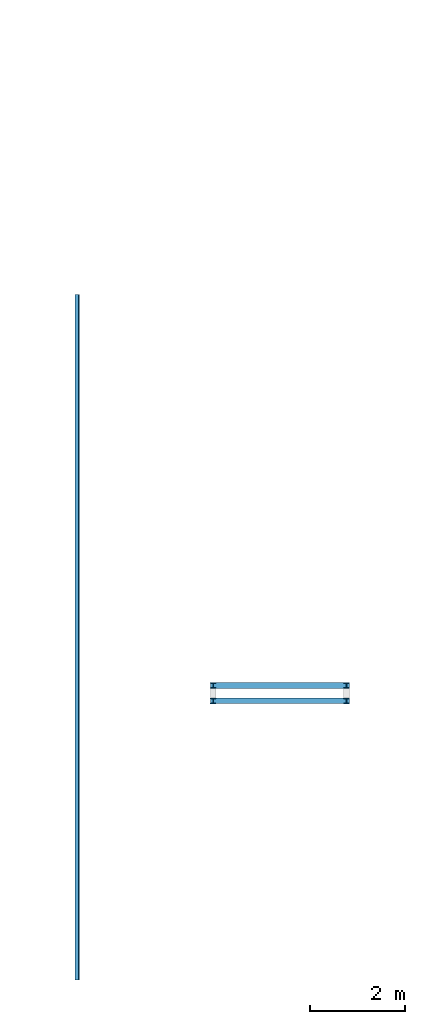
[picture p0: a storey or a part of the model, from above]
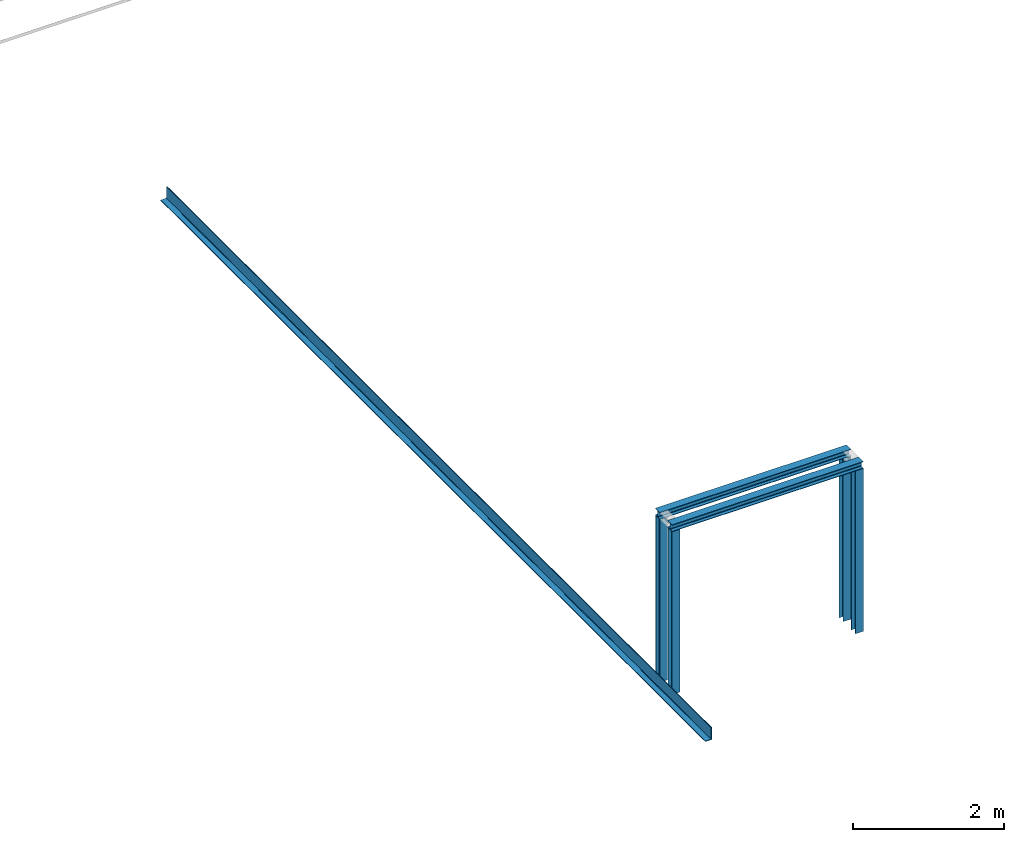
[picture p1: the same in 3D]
Properties of the parts of a building model (IFC4X3_ADD2), part 1 of 4

# File
Description: ViewDefinition [CoordinationView_V2.0], ExchangeRequirement [Architecture], Option [IfcExportBaseQuantities: Off], Option [IfcExportElementOnOffAndFrozenLayers: On], Option [IfcExplodeExternalReferences: Off], Option [IfcTesselateBSplineCurvesAndSurfaces: Off], Option [IfcExportSweptSolidAsBRep: Off], Option [IfcExportProfileCenterOfGravity: Off], Option [IfcExportMultiPlyElementsAsAggregated: Off], Option [IfcExportTesselation: 0.000000], Option [IfcCreateUniqueGuidForBlocks: On], Option [IfcCreateUniqueGuidForXrefs: On], Option [IfcExportSubtractOpenings: Off], Option [IfcExportAllVisibilityStates: Off]
File name: C:\\Users\\info\\Documents\\00 Elearning geodata BIMform\\1.2 Coördinatensystemen en projecties\\1.2.2 Georeferentie in IFC modellen\\IFC files\\BIM_Architecture__stabilite-IFC4_subset.ifc
Time: 2026-02-23T21:27:19
Author: Undefined
Organization: Undefined
Written by: BricsCAD BIM 26.1.08
Made in: BricsCAD BIM 26.1.08
Authorization: Undefined

# IfcSite, Site
RefLatitude: 42, 23, 13, 199999; RefLongitude: -71, -14, -31, -199998; RefElevation: 0 mm

# IfcBuilding, IFC Building Story
ElevationOfRefHeight: 0 mm; ElevationOfTerrain: 0 mm

# IfcBuildingStorey (6)
In: IFC Building Story
Name | LongName | Elevation (mm)
ETAGE -1 | ETAGE -1 | -3000
FOND 00 (0) | FOND 00 (0) | -800
ETAGE 00 (0) | ETAGE 00 (0) | 0
ETAGE 10 (1) | ETAGE 10 (1) | 4370
ETAGE 20 (2) | ETAGE 20 (2) | 8640
ACROTERE (4) | ACROTERE (4) | 10000

# IfcBeam: 1*1 (8)
Description: 1*1; Group: Groupe de modèles:IFC ERGON 14122021 (membre exclu):2154686
Pset_XX_AsBuilt - Catégorie: Ossature; Famille: Forme directe; Type: 1*1; Durée de garantie (mois): 0; Périodicité de contrôle (mois): 0
Pset_XX_Poutres - Résistance au feu: RF60
Name | In | Identifiant
RAV200 | ETAGE 00 (0) | 57 | Material: STEEL/Accessory
2 x ZW1 | ETAGE 00 (0) | 62 | Material: STEEL/Accessory_invisible
RAV200 | ETAGE 00 (0) | 58 | Material: STEEL/Accessory
4 x MP15 | ETAGE 20 (2) | 336

# IfcBeam: 1*1 10 (12)
In: ETAGE 10 (1)
Description: 1*1; Material: STEEL/Accessory_invisible; Group: Groupe de modèles:IFC ERGON 14122021 (membre exclu):2154686
Pset_XX_AsBuilt - Catégorie: Ossature; Famille: Forme directe; Type: 1*1; Identifiant: 193; Durée de garantie (mois): 0; Périodicité de contrôle (mois): 0
Pset_XX_Poutres - Résistance au feu: RF60

# IfcBeam: 1*1 11 (6)
In: ETAGE 10 (1)
Description: 1*1; Material: STEEL/Accessory_invisible; Group: Groupe de modèles:IFC ERGON 14122021 (membre exclu):2154686
Pset_XX_AsBuilt - Catégorie: Ossature; Famille: Forme directe; Type: 1*1; Identifiant: 296; Durée de garantie (mois): 0; Périodicité de contrôle (mois): 0
Pset_XX_Poutres - Résistance au feu: RF60

# IfcBeam: 1*1 12 (29)
Description: 1*1; Material: STEEL/Accessory_invisible; Group: Groupe de modèles:IFC ERGON 14122021 (membre exclu):2154686
Pset_XX_AsBuilt - Catégorie: Ossature; Famille: Forme directe; Type: 1*1; Identifiant: 310; Durée de garantie (mois): 0; Périodicité de contrôle (mois): 0
Pset_XX_Poutres - Résistance au feu: RF60
Name | In
19 x ZW1 | ETAGE 10 (1)
10 x ZW1 | ETAGE 20 (2)

# IfcBeam: 1*1 13 (12)
In: ETAGE 10 (1)
Description: 1*1; Material: STEEL/Accessory_invisible 261; Group: Groupe de modèles:IFC ERGON 14122021 (membre exclu):2154686
Pset_XX_AsBuilt - Catégorie: Ossature; Famille: Forme directe; Type: 1*1; Identifiant: 291; Durée de garantie (mois): 0; Périodicité de contrôle (mois): 0
Pset_XX_Poutres - Résistance au feu: RF60

# IfcBeam: 1*1 14 (12)
In: ETAGE 10 (1)
Description: 1*1; Material: STEEL/Accessory_invisible; Group: Groupe de modèles:IFC ERGON 14122021 (membre exclu):2154686
Pset_XX_AsBuilt - Catégorie: Ossature; Famille: Forme directe; Type: 1*1; Identifiant: 293; Durée de garantie (mois): 0; Périodicité de contrôle (mois): 0
Pset_XX_Poutres - Résistance au feu: RF60

# IfcBeam: 1*1 15 (3)
In: ETAGE 10 (1)
Description: 1*1; Material: STEEL/Accessory_invisible; Group: Groupe de modèles:IFC ERGON 14122021 (membre exclu):2154686
Pset_XX_AsBuilt - Catégorie: Ossature; Famille: Forme directe; Type: 1*1; Identifiant: 314; Durée de garantie (mois): 0; Périodicité de contrôle (mois): 0
Pset_XX_Poutres - Résistance au feu: RF60

# IfcBeam: 1*1 16 (4)
In: ETAGE 20 (2)
Description: 1*1; Material: STEEL/Accessory_invisible; Group: Groupe de modèles:IFC ERGON 14122021 (membre exclu):2154686
Pset_XX_AsBuilt - Catégorie: Ossature; Famille: Forme directe; Type: 1*1; Identifiant: 180; Durée de garantie (mois): 0; Périodicité de contrôle (mois): 0
Pset_XX_Poutres - Résistance au feu: RF60

# IfcBeam: 1*1 17 (6)
In: ETAGE 20 (2)
Description: 1*1; Material: STEEL/Accessory_invisible; Group: Groupe de modèles:IFC ERGON 14122021 (membre exclu):2154686
Pset_XX_AsBuilt - Catégorie: Ossature; Famille: Forme directe; Type: 1*1; Identifiant: 188; Durée de garantie (mois): 0; Périodicité de contrôle (mois): 0
Pset_XX_Poutres - Résistance au feu: RF60

# IfcBeam: 1*1 18 (12)
In: ETAGE 20 (2)
Description: 1*1; Material: STEEL/Accessory_invisible 261; Group: Groupe de modèles:IFC ERGON 14122021 (membre exclu):2154686
Pset_XX_AsBuilt - Catégorie: Ossature; Famille: Forme directe; Type: 1*1; Durée de garantie (mois): 0; Périodicité de contrôle (mois): 0
Pset_XX_Poutres - Résistance au feu: RF60
Name | Identifiant
6 x 50 | L1
6 x ZN342 | L2

# IfcBeam: 1*1 19 (6)
In: ETAGE 20 (2)
Description: 1*1; Material: STEEL/Accessory_invisible 261; Group: Groupe de modèles:IFC ERGON 14122021 (membre exclu):2154686
Pset_XX_AsBuilt - Catégorie: Ossature; Famille: Forme directe; Type: 1*1; Identifiant: L3; Durée de garantie (mois): 0; Périodicité de contrôle (mois): 0
Pset_XX_Poutres - Résistance au feu: RF60

# IfcBeam: 1*1 2 (66)
In: ETAGE 00 (0)
Description: 1*1; Material: STEEL/Accessory_invisible 261; Group: Groupe de modèles:IFC ERGON 14122021 (membre exclu):2154686
Pset_XX_AsBuilt - Catégorie: Ossature; Famille: Forme directe; Type: 1*1; Identifiant: 47; Durée de garantie (mois): 0; Périodicité de contrôle (mois): 0
Pset_XX_Poutres - Résistance au feu: RF60

# IfcBeam: 1*1 20 (12)
In: ETAGE 20 (2)
Description: 1*1; Material: STEEL/Accessory_invisible; Group: Groupe de modèles:IFC ERGON 14122021 (membre exclu):2154686
Pset_XX_AsBuilt - Catégorie: Ossature; Famille: Forme directe; Type: 1*1; Durée de garantie (mois): 0; Périodicité de contrôle (mois): 0
Pset_XX_Poutres - Résistance au feu: RF60
Name | Identifiant
6 x MP14 | 331
6 x MP14 | 332

# IfcBeam: 1*1 21 (4)
In: ETAGE 20 (2)
Description: 1*1; Material: STEEL/Accessory_invisible; Group: Groupe de modèles:IFC ERGON 14122021 (membre exclu):2154686
Pset_XX_AsBuilt - Catégorie: Ossature; Famille: Forme directe; Type: 1*1; Identifiant: 337; Durée de garantie (mois): 0; Périodicité de contrôle (mois): 0
Pset_XX_Poutres - Résistance au feu: RF60

# IfcBeam: 1*1 22, ZW1
In: ETAGE 20 (2)
Description: 1*1; Material: STEEL/Accessory_invisible; Group: Groupe de modèles:IFC ERGON 14122021 (membre exclu):2154686
Pset_XX_AsBuilt - Catégorie: Ossature; Famille: Forme directe; Type: 1*1; Identifiant: 333; Durée de garantie (mois): 0; Périodicité de contrôle (mois): 0
Pset_XX_Poutres - Résistance au feu: RF60

# IfcBeam: 1*1 3 (239)
Description: 1*1; Group: Groupe de modèles:IFC ERGON 14122021 (membre exclu):2154686
Pset_XX_AsBuilt - Catégorie: Ossature; Famille: Forme directe; Type: 1*1; Durée de garantie (mois): 0; Périodicité de contrôle (mois): 0
Pset_XX_Poutres - Résistance au feu: RF60
Name | In | Material | Identifiant
46 x ES31 | ETAGE 00 (0) | STEEL/Accessory_invisible 261 | 48
9 x ES31 | ETAGE 00 (0) | STEEL/Accessory_invisible 261 | 100
2 x ES31 | ETAGE 00 (0) | STEEL/Accessory_invisible 261 | 101
ES31 | ETAGE 00 (0) | STEEL/Accessory_invisible 261 | 103
2 x ES31 | ETAGE 00 (0) | STEEL/Accessory_invisible 261 | 104
ES31 | ETAGE 00 (0) | STEEL/Accessory_invisible 261 | 105
ES31 | ETAGE 00 (0) | STEEL/Accessory_invisible 261 | 106
2 x ES31 | ETAGE 00 (0) | STEEL/Accessory_invisible 261 | 260
4 x ES31 | ETAGE 00 (0) | STEEL/Accessory_invisible 261 | 262
8 x ZW3 | ETAGE 00 (0) | STEEL/Accessory_invisible | 282
4 x ZW3 | ETAGE 00 (0) | STEEL/Accessory_invisible | 283
9 x ZW3 | ETAGE 00 (0) | STEEL/Accessory_invisible | 284
10 x ZW3 | ETAGE 00 (0) | STEEL/Accessory_invisible | 285
6 x ZW3 | ETAGE 00 (0) | STEEL/Accessory_invisible | 280
ZW3 | ETAGE 00 (0) | STEEL/Accessory_invisible | 286
3 x 51 | ETAGE 00 (0) | STEEL/Accessory_invisible 261 | 303
ZW3 | ETAGE 00 (0) | STEEL/Accessory_invisible | 278
2 x ZW3 | ETAGE 00 (0) | STEEL/Accessory_invisible | 275
16 x RH14 | ETAGE 10 (1) | STEEL/Accessory_invisible | 264
16 x MP21 | ETAGE 10 (1) | STEEL/Accessory_invisible | 267
2 x RH15 | ETAGE 10 (1) | STEEL/Accessory_invisible | 188
6 x ZW3 | ETAGE 10 (1) | STEEL/Accessory_invisible | 296
MP12 | ETAGE 10 (1) | STEEL/Accessory_invisible | 182
4 x RH15 | ETAGE 10 (1) | STEEL/Accessory_invisible | 199
4 x RH14 | ETAGE 20 (2) | STEEL/Accessory_invisible | 264
16 x MP21 | ETAGE 20 (2) | STEEL/Accessory_invisible | 267
4 x ZW3 | ETAGE 20 (2) | STEEL/Accessory_invisible | 296
12 x ZW1 | ETAGE 20 (2) | STEEL/Accessory_invisible | 333
4 x ZW3 | ETAGE 20 (2) | STEEL/Accessory_invisible | 280
3 x 52 | ETAGE 10 (1) | STEEL/Accessory_invisible 261 | 307
11 x 54 | ETAGE 10 (1) | STEEL/Accessory_invisible 261 | 321
8 x 54 | ETAGE 10 (1) | STEEL/Accessory_invisible 261 | 319
10 x 54 | ETAGE 20 (2) | STEEL/Accessory_invisible 261 | 319
3 x 53 | ETAGE 10 (1) | STEEL/Accessory_invisible 261 | 311
MP12 | ETAGE 10 (1) | STEEL/Accessory_invisible | 183
5 x ZW3 | ETAGE 10 (1) | STEEL/Accessory_invisible | 280
55 | ETAGE 20 (2) | STEEL/Accessory_invisible | 338

# IfcBeam: 1*1 4 (3)
In: ETAGE 00 (0)
Description: 1*1; Material: STEEL/Accessory_invisible; Group: Groupe de modèles:IFC ERGON 14122021 (membre exclu):2154686
Pset_XX_AsBuilt - Catégorie: Ossature; Famille: Forme directe; Type: 1*1; Identifiant: 306; Durée de garantie (mois): 0; Périodicité de contrôle (mois): 0
Pset_XX_Poutres - Résistance au feu: RF60

# IfcBeam: 1*1 5 (6)
In: ETAGE 00 (0)
Description: 1*1; Material: STEEL/Accessory_invisible; Group: Groupe de modèles:IFC ERGON 14122021 (membre exclu):2154686
Pset_XX_AsBuilt - Catégorie: Ossature; Famille: Forme directe; Type: 1*1; Identifiant: 343; Durée de garantie (mois): 0; Périodicité de contrôle (mois): 0
Pset_XX_Poutres - Résistance au feu: RF60

# IfcBeam: 1*1 6 (20)
Description: 1*1; Material: STEEL/Accessory_invisible; Group: Groupe de modèles:IFC ERGON 14122021 (membre exclu):2154686
Pset_XX_AsBuilt - Catégorie: Ossature; Famille: Forme directe; Type: 1*1; Identifiant: 264; Durée de garantie (mois): 0; Périodicité de contrôle (mois): 0
Pset_XX_Poutres - Résistance au feu: RF60
Name | In
10 x RH14 | ETAGE 10 (1)
10 x RH14 | ETAGE 20 (2)

# IfcBeam: 1*1 7 (2)
In: ETAGE 10 (1)
Description: 1*1; Material: STEEL/Accessory_invisible; Group: Groupe de modèles:IFC ERGON 14122021 (membre exclu):2154686
Pset_XX_AsBuilt - Catégorie: Ossature; Famille: Forme directe; Type: 1*1; Durée de garantie (mois): 0; Périodicité de contrôle (mois): 0
Pset_XX_Poutres - Résistance au feu: RF60
Name | Identifiant
MP12 | 182
MP12 | 183

# IfcBeam: 1*1 8 (4)
In: ETAGE 10 (1)
Description: 1*1; Material: STEEL/Accessory_invisible; Group: Groupe de modèles:IFC ERGON 14122021 (membre exclu):2154686
Pset_XX_AsBuilt - Catégorie: Ossature; Famille: Forme directe; Type: 1*1; Identifiant: 185; Durée de garantie (mois): 0; Périodicité de contrôle (mois): 0
Pset_XX_Poutres - Résistance au feu: RF60

# IfcBeam: 1*1 9 (35)
Description: 1*1; Material: STEEL/Accessory_invisible; Group: Groupe de modèles:IFC ERGON 14122021 (membre exclu):2154686
Pset_XX_AsBuilt - Catégorie: Ossature; Famille: Forme directe; Type: 1*1; Durée de garantie (mois): 0; Périodicité de contrôle (mois): 0
Pset_XX_Poutres - Résistance au feu: RF60
Name | In | Identifiant
28 x MP21 | ETAGE 10 (1) | 267
3 x ZW1 | ETAGE 10 (1) | 310
4 x MP21 | ETAGE 20 (2) | 267

# IfcBeam: 10*1 (5)
In: ETAGE 10 (1)
Description: 10*1; Material: STEEL/Accessory_invisible 261; Group: Groupe de modèles:IFC ERGON 14122021 (membre exclu):2154686
Pset_XX_AsBuilt - Catégorie: Ossature; Famille: Forme directe; Type: 10*1; Durée de garantie (mois): 0; Périodicité de contrôle (mois): 0
Pset_XX_Poutres - Résistance au feu: RF60
Name | Identifiant
2 x BEK4 | 134
3 x BEK4 | 151

# IfcBeam: 100*100 (221)
In: ETAGE 00 (0)
Description: 100*100; Material: STEEL/Accessory_invisible; Group: Groupe de modèles:IFC ERGON 14122021 (membre exclu):2154686
Pset_XX_AsBuilt - Catégorie: Ossature; Famille: Forme directe; Type: 100*100; Identifiant: 46; Durée de garantie (mois): 0; Périodicité de contrôle (mois): 0
Pset_XX_Poutres - Résistance au feu: RF60

# IfcBeam: 100*80 (6)
In: ETAGE 00 (0)
Description: 100*80; Material: STEEL/Accessory_invisible; Group: Groupe de modèles:IFC ERGON 14122021 (membre exclu):2154686
Pset_XX_AsBuilt - Catégorie: Ossature; Famille: Forme directe; Type: 100*80; Identifiant: 102; Durée de garantie (mois): 0; Périodicité de contrôle (mois): 0
Pset_XX_Poutres - Résistance au feu: RF60

# IfcBeam: 11*1 (2)
In: ETAGE 10 (1)
Description: 11*1; Material: STEEL/Accessory_invisible 261; Group: Groupe de modèles:IFC ERGON 14122021 (membre exclu):2154686
Pset_XX_AsBuilt - Catégorie: Ossature; Famille: Forme directe; Type: 11*1; Durée de garantie (mois): 0; Périodicité de contrôle (mois): 0
Pset_XX_Poutres - Résistance au feu: RF60
Name | Identifiant
BEK4 | 126
BEK4 | 146

# IfcBeam: 11*1 2, BEK4
In: ETAGE 10 (1)
Description: 11*1; Material: STEEL/Accessory_invisible 261; Group: Groupe de modèles:IFC ERGON 14122021 (membre exclu):2154686
Pset_XX_AsBuilt - Catégorie: Ossature; Famille: Forme directe; Type: 11*1; Identifiant: 242; Durée de garantie (mois): 0; Périodicité de contrôle (mois): 0
Pset_XX_Poutres - Résistance au feu: RF60

# IfcBeam: 11*1 3, BEK4
In: ETAGE 10 (1)
Description: 11*1; Material: STEEL/Accessory_invisible 261; Group: Groupe de modèles:IFC ERGON 14122021 (membre exclu):2154686
Pset_XX_AsBuilt - Catégorie: Ossature; Famille: Forme directe; Type: 11*1; Identifiant: 117; Durée de garantie (mois): 0; Périodicité de contrôle (mois): 0
Pset_XX_Poutres - Résistance au feu: RF60

# IfcBeam: 11*1 4, BEK4
In: ETAGE 10 (1)
Description: 11*1; Material: STEEL/Accessory_invisible 261; Group: Groupe de modèles:IFC ERGON 14122021 (membre exclu):2154686
Pset_XX_AsBuilt - Catégorie: Ossature; Famille: Forme directe; Type: 11*1; Identifiant: 146; Durée de garantie (mois): 0; Périodicité de contrôle (mois): 0
Pset_XX_Poutres - Résistance au feu: RF60

# IfcBeam: 11*1 5, BEK4
In: ETAGE 20 (2)
Description: 11*1; Material: STEEL/Accessory_invisible 261; Group: Groupe de modèles:IFC ERGON 14122021 (membre exclu):2154686
Pset_XX_AsBuilt - Catégorie: Ossature; Famille: Forme directe; Type: 11*1; Identifiant: 117; Durée de garantie (mois): 0; Périodicité de contrôle (mois): 0
Pset_XX_Poutres - Résistance au feu: RF60

# IfcBeam: 11*1 6, BEK4
In: ETAGE 20 (2)
Description: 11*1; Material: STEEL/Accessory_invisible 261; Group: Groupe de modèles:IFC ERGON 14122021 (membre exclu):2154686
Pset_XX_AsBuilt - Catégorie: Ossature; Famille: Forme directe; Type: 11*1; Identifiant: 111; Durée de garantie (mois): 0; Périodicité de contrôle (mois): 0
Pset_XX_Poutres - Résistance au feu: RF60

# IfcBeam: 11*1 7, BEK4
In: ETAGE 20 (2)
Description: 11*1; Material: STEEL/Accessory_invisible 261; Group: Groupe de modèles:IFC ERGON 14122021 (membre exclu):2154686
Pset_XX_AsBuilt - Catégorie: Ossature; Famille: Forme directe; Type: 11*1; Identifiant: 111; Durée de garantie (mois): 0; Périodicité de contrôle (mois): 0
Pset_XX_Poutres - Résistance au feu: RF60

# IfcBeam: 11*1 8, BEK4
In: ETAGE 20 (2)
Description: 11*1; Material: STEEL/Accessory_invisible 261; Group: Groupe de modèles:IFC ERGON 14122021 (membre exclu):2154686
Pset_XX_AsBuilt - Catégorie: Ossature; Famille: Forme directe; Type: 11*1; Identifiant: 126; Durée de garantie (mois): 0; Périodicité de contrôle (mois): 0
Pset_XX_Poutres - Résistance au feu: RF60

# IfcBeam: 11*1 9, BEK4
In: ETAGE 20 (2)
Description: 11*1; Material: STEEL/Accessory_invisible 261; Group: Groupe de modèles:IFC ERGON 14122021 (membre exclu):2154686
Pset_XX_AsBuilt - Catégorie: Ossature; Famille: Forme directe; Type: 11*1; Identifiant: 126; Durée de garantie (mois): 0; Périodicité de contrôle (mois): 0
Pset_XX_Poutres - Résistance au feu: RF60

# IfcBeam: 12*1 (3)
In: ETAGE 10 (1)
Description: 12*1; Material: STEEL/Accessory_invisible 261; Group: Groupe de modèles:IFC ERGON 14122021 (membre exclu):2154686
Pset_XX_AsBuilt - Catégorie: Ossature; Famille: Forme directe; Type: 12*1; Identifiant: 248; Durée de garantie (mois): 0; Périodicité de contrôle (mois): 0
Pset_XX_Poutres - Résistance au feu: RF60

# IfcBeam: 200*170 (2)
In: ETAGE 00 (0)
Description: 200*170; Material: STEEL/Accessory_invisible; Group: Groupe de modèles:IFC ERGON 14122021 (membre exclu):2154686
Pset_XX_AsBuilt - Catégorie: Ossature; Famille: Forme directe; Type: 200*170; Durée de garantie (mois): 0; Périodicité de contrôle (mois): 0
Pset_XX_Poutres - Résistance au feu: RF60
Name | Identifiant
ES32 | 76
ES32 | 157

# IfcBeam: 200*190 (2)
In: ETAGE 00 (0)
Description: 200*190; Material: STEEL/Accessory_invisible; Group: Groupe de modèles:IFC ERGON 14122021 (membre exclu):2154686
Pset_XX_AsBuilt - Catégorie: Ossature; Famille: Forme directe; Type: 200*190; Identifiant: 263; Durée de garantie (mois): 0; Périodicité de contrôle (mois): 0
Pset_XX_Poutres - Résistance au feu: RF60

# IfcBeam: 200*210 (2)
In: ETAGE 00 (0)
Description: 200*210; Material: STEEL/Accessory_invisible; Group: Groupe de modèles:IFC ERGON 14122021 (membre exclu):2154686
Pset_XX_AsBuilt - Catégorie: Ossature; Famille: Forme directe; Type: 200*210; Identifiant: 43; Durée de garantie (mois): 0; Périodicité de contrôle (mois): 0
Pset_XX_Poutres - Résistance au feu: RF60

# IfcBeam: 200*260, ES32
In: ETAGE 00 (0)
Description: 200*260; Material: STEEL/Accessory_invisible; Group: Groupe de modèles:IFC ERGON 14122021 (membre exclu):2154686
Pset_XX_AsBuilt - Catégorie: Ossature; Famille: Forme directe; Type: 200*260; Identifiant: 75; Durée de garantie (mois): 0; Périodicité de contrôle (mois): 0
Pset_XX_Poutres - Résistance au feu: RF60

# IfcBeam: 200*350, ES32
In: ETAGE 00 (0)
Description: 200*350; Material: STEEL/Accessory_invisible; Group: Groupe de modèles:IFC ERGON 14122021 (membre exclu):2154686
Pset_XX_AsBuilt - Catégorie: Ossature; Famille: Forme directe; Type: 200*350; Identifiant: 70; Durée de garantie (mois): 0; Périodicité de contrôle (mois): 0
Pset_XX_Poutres - Résistance au feu: RF60

# IfcBeam: 200*360, ES32
In: ETAGE 00 (0)
Description: 200*360; Material: STEEL/Accessory_invisible; Group: Groupe de modèles:IFC ERGON 14122021 (membre exclu):2154686
Pset_XX_AsBuilt - Catégorie: Ossature; Famille: Forme directe; Type: 200*360; Identifiant: 261; Durée de garantie (mois): 0; Périodicité de contrôle (mois): 0
Pset_XX_Poutres - Résistance au feu: RF60

# IfcBeam: 200*380, ES32
In: ETAGE 00 (0)
Description: 200*380; Material: STEEL/Accessory_invisible; Group: Groupe de modèles:IFC ERGON 14122021 (membre exclu):2154686
Pset_XX_AsBuilt - Catégorie: Ossature; Famille: Forme directe; Type: 200*380; Identifiant: 54; Durée de garantie (mois): 0; Périodicité de contrôle (mois): 0
Pset_XX_Poutres - Résistance au feu: RF60

# IfcBeam: 200*410 (2)
In: ETAGE 00 (0)
Description: 200*410; Material: STEEL/Accessory_invisible; Group: Groupe de modèles:IFC ERGON 14122021 (membre exclu):2154686
Pset_XX_AsBuilt - Catégorie: Ossature; Famille: Forme directe; Type: 200*410; Identifiant: 72; Durée de garantie (mois): 0; Périodicité de contrôle (mois): 0
Pset_XX_Poutres - Résistance au feu: RF60

# IfcBeam: 200*430 (4)
In: ETAGE 00 (0)
Description: 200*430; Material: STEEL/Accessory_invisible; Group: Groupe de modèles:IFC ERGON 14122021 (membre exclu):2154686
Pset_XX_AsBuilt - Catégorie: Ossature; Famille: Forme directe; Type: 200*430; Identifiant: 158; Durée de garantie (mois): 0; Périodicité de contrôle (mois): 0
Pset_XX_Poutres - Résistance au feu: RF60

# IfcBeam: 200*460, ES32
In: ETAGE 00 (0)
Description: 200*460; Material: STEEL/Accessory_invisible; Group: Groupe de modèles:IFC ERGON 14122021 (membre exclu):2154686
Pset_XX_AsBuilt - Catégorie: Ossature; Famille: Forme directe; Type: 200*460; Identifiant: 78; Durée de garantie (mois): 0; Périodicité de contrôle (mois): 0
Pset_XX_Poutres - Résistance au feu: RF60

# IfcBeam: 200*490, ES32
In: ETAGE 00 (0)
Description: 200*490; Material: STEEL/Accessory_invisible; Group: Groupe de modèles:IFC ERGON 14122021 (membre exclu):2154686
Pset_XX_AsBuilt - Catégorie: Ossature; Famille: Forme directe; Type: 200*490; Identifiant: 96; Durée de garantie (mois): 0; Périodicité de contrôle (mois): 0
Pset_XX_Poutres - Résistance au feu: RF60

# IfcBeam: 200*50 (2)
In: ETAGE 00 (0)
Description: 200*50; Material: STEEL/Accessory_invisible; Group: Groupe de modèles:IFC ERGON 14122021 (membre exclu):2154686
Pset_XX_AsBuilt - Catégorie: Ossature; Famille: Forme directe; Type: 200*50; Durée de garantie (mois): 0; Périodicité de contrôle (mois): 0
Pset_XX_Poutres - Résistance au feu: RF60
Name | Identifiant
ES32 | 55
ES32 | 56

# IfcBeam: 200*560 (2)
In: ETAGE 00 (0)
Description: 200*560; Material: STEEL/Accessory_invisible; Group: Groupe de modèles:IFC ERGON 14122021 (membre exclu):2154686
Pset_XX_AsBuilt - Catégorie: Ossature; Famille: Forme directe; Type: 200*560; Identifiant: 69; Durée de garantie (mois): 0; Périodicité de contrôle (mois): 0
Pset_XX_Poutres - Résistance au feu: RF60

# IfcBeam: 200*90, ES32
In: ETAGE 00 (0)
Description: 200*90; Material: STEEL/Accessory_invisible; Group: Groupe de modèles:IFC ERGON 14122021 (membre exclu):2154686
Pset_XX_AsBuilt - Catégorie: Ossature; Famille: Forme directe; Type: 200*90; Identifiant: 71; Durée de garantie (mois): 0; Périodicité de contrôle (mois): 0
Pset_XX_Poutres - Résistance au feu: RF60

# IfcBeam: 203*1, BEK4
In: ETAGE 10 (1)
Description: 203*1; Material: STEEL/Accessory_invisible 261; Group: Groupe de modèles:IFC ERGON 14122021 (membre exclu):2154686
Pset_XX_AsBuilt - Catégorie: Ossature; Famille: Forme directe; Type: 203*1; Identifiant: 255; Durée de garantie (mois): 0; Périodicité de contrôle (mois): 0
Pset_XX_Poutres - Résistance au feu: RF60

# IfcBeam: 210*1 (4)
In: ETAGE 10 (1)
Description: 210*1; Material: STEEL/Accessory_invisible 261; Group: Groupe de modèles:IFC ERGON 14122021 (membre exclu):2154686
Pset_XX_AsBuilt - Catégorie: Ossature; Famille: Forme directe; Type: 210*1; Durée de garantie (mois): 0; Périodicité de contrôle (mois): 0
Pset_XX_Poutres - Résistance au feu: RF60
Name | Identifiant
3 x BEK4 | 137
BEK4 | 145

# IfcBeam: 210*1 2 (2)
In: ETAGE 10 (1)
Description: 210*1; Material: STEEL/Accessory_invisible 261; Group: Groupe de modèles:IFC ERGON 14122021 (membre exclu):2154686
Pset_XX_AsBuilt - Catégorie: Ossature; Famille: Forme directe; Type: 210*1; Durée de garantie (mois): 0; Périodicité de contrôle (mois): 0
Pset_XX_Poutres - Résistance au feu: RF60
Name | Identifiant
BEK4 | 145
BEK4 | 137

# IfcBeam: 210*1 3, BEK4
In: ETAGE 10 (1)
Description: 210*1; Material: STEEL/Accessory_invisible 261; Group: Groupe de modèles:IFC ERGON 14122021 (membre exclu):2154686
Pset_XX_AsBuilt - Catégorie: Ossature; Famille: Forme directe; Type: 210*1; Identifiant: 145; Durée de garantie (mois): 0; Périodicité de contrôle (mois): 0
Pset_XX_Poutres - Résistance au feu: RF60

# IfcBeam: 211*1, BEK4
In: ETAGE 10 (1)
Description: 211*1; Material: STEEL/Accessory_invisible 261; Group: Groupe de modèles:IFC ERGON 14122021 (membre exclu):2154686
Pset_XX_AsBuilt - Catégorie: Ossature; Famille: Forme directe; Type: 211*1; Identifiant: 250; Durée de garantie (mois): 0; Périodicité de contrôle (mois): 0
Pset_XX_Poutres - Résistance au feu: RF60

# IfcBeam: 218*1, BEK4
In: ETAGE 10 (1)
Description: 218*1; Material: STEEL/Accessory_invisible 261; Group: Groupe de modèles:IFC ERGON 14122021 (membre exclu):2154686
Pset_XX_AsBuilt - Catégorie: Ossature; Famille: Forme directe; Type: 218*1; Identifiant: 252; Durée de garantie (mois): 0; Périodicité de contrôle (mois): 0
Pset_XX_Poutres - Résistance au feu: RF60

# IfcBeam: 30*200, POL4
In: ETAGE 10 (1)
Description: 30*200; Material: STEEL/Accessory_EPS; Group: Groupe de modèles:IFC ERGON 14122021 (membre exclu):2154686
Pset_XX_AsBuilt - Catégorie: Ossature; Famille: Forme directe; Type: 30*200; Identifiant: 231; Durée de garantie (mois): 0; Périodicité de contrôle (mois): 0
Pset_XX_Poutres - Résistance au feu: RF60

# IfcBeam: 30*300 (19)
Description: 30*300; Material: STEEL/Accessory_EPS; Group: Groupe de modèles:IFC ERGON 14122021 (membre exclu):2154686
Pset_XX_AsBuilt - Catégorie: Ossature; Famille: Forme directe; Type: 30*300; Identifiant: 13; Durée de garantie (mois): 0; Périodicité de contrôle (mois): 0
Pset_XX_Poutres - Résistance au feu: RF60
Name | In
17 x POL4 | ETAGE 00 (0)
2 x POL4 | ETAGE 10 (1)

# IfcBeam: 30*300 2 (5)
In: ETAGE 00 (0)
Description: 30*300; Material: STEEL/Accessory_EPS; Group: Groupe de modèles:IFC ERGON 14122021 (membre exclu):2154686
Pset_XX_AsBuilt - Catégorie: Ossature; Famille: Forme directe; Type: 30*300; Identifiant: 226; Durée de garantie (mois): 0; Périodicité de contrôle (mois): 0
Pset_XX_Poutres - Résistance au feu: RF60

# IfcBeam: 30*300 3 (3)
In: ETAGE 00 (0)
Description: 30*300; Material: STEEL/Accessory_EPS; Group: Groupe de modèles:IFC ERGON 14122021 (membre exclu):2154686
Pset_XX_AsBuilt - Catégorie: Ossature; Famille: Forme directe; Type: 30*300; Identifiant: 81; Durée de garantie (mois): 0; Périodicité de contrôle (mois): 0
Pset_XX_Poutres - Résistance au feu: RF60

# IfcBeam: 30*300 4 (10)
In: ETAGE 10 (1)
Description: 30*300; Material: STEEL/Accessory_EPS; Group: Groupe de modèles:IFC ERGON 14122021 (membre exclu):2154686
Pset_XX_AsBuilt - Catégorie: Ossature; Famille: Forme directe; Type: 30*300; Identifiant: 81; Durée de garantie (mois): 0; Périodicité de contrôle (mois): 0
Pset_XX_Poutres - Résistance au feu: RF60

# IfcBeam: 30*340, POL4
In: ETAGE 00 (0)
Description: 30*340; Material: STEEL/Accessory_EPS; Group: Groupe de modèles:IFC ERGON 14122021 (membre exclu):2154686
Pset_XX_AsBuilt - Catégorie: Ossature; Famille: Forme directe; Type: 30*340; Identifiant: 9; Durée de garantie (mois): 0; Périodicité de contrôle (mois): 0
Pset_XX_Poutres - Résistance au feu: RF60

# IfcBeam: 4*1 (5)
In: ETAGE 20 (2)
Description: 4*1; Material: STEEL/Accessory_invisible 261; Group: Groupe de modèles:IFC ERGON 14122021 (membre exclu):2154686
Pset_XX_AsBuilt - Catégorie: Ossature; Famille: Forme directe; Type: 4*1; Durée de garantie (mois): 0; Périodicité de contrôle (mois): 0
Pset_XX_Poutres - Résistance au feu: RF60
Name | Identifiant
4 x BEK4 | 112
BEK4 | 208

# IfcBeam: 4*1 2 (3)
In: ETAGE 20 (2)
Description: 4*1; Material: STEEL/Accessory_invisible 261; Group: Groupe de modèles:IFC ERGON 14122021 (membre exclu):2154686
Pset_XX_AsBuilt - Catégorie: Ossature; Famille: Forme directe; Type: 4*1; Identifiant: 115; Durée de garantie (mois): 0; Périodicité de contrôle (mois): 0
Pset_XX_Poutres - Résistance au feu: RF60

# IfcBeam: 4*1 3 (2)
In: ETAGE 20 (2)
Description: 4*1; Material: STEEL/Accessory_invisible 261; Group: Groupe de modèles:IFC ERGON 14122021 (membre exclu):2154686
Pset_XX_AsBuilt - Catégorie: Ossature; Famille: Forme directe; Type: 4*1; Durée de garantie (mois): 0; Périodicité de contrôle (mois): 0
Pset_XX_Poutres - Résistance au feu: RF60
Name | Identifiant
BEK4 | 161
BEK4 | 209

# IfcBeam: 4*30 (2)
In: ETAGE 00 (0)
Description: 4*30; Material: STEEL/Accessory_Rubber; Group: Groupe de modèles:IFC ERGON 14122021 (membre exclu):2154686
Pset_XX_AsBuilt - Catégorie: Ossature; Famille: Forme directe; Type: 4*30; Identifiant: 36; Durée de garantie (mois): 0; Périodicité de contrôle (mois): 0
Pset_XX_Poutres - Résistance au feu: RF60

# IfcBeam: 4*30 10, NE6
In: ETAGE 00 (0)
Description: 4*30; Material: STEEL/Accessory_Rubber; Group: Groupe de modèles:IFC ERGON 14122021 (membre exclu):2154686
Pset_XX_AsBuilt - Catégorie: Ossature; Famille: Forme directe; Type: 4*30; Identifiant: 31; Durée de garantie (mois): 0; Périodicité de contrôle (mois): 0
Pset_XX_Poutres - Résistance au feu: RF60

# IfcBeam: 4*30 11, NE6
In: ETAGE 00 (0)
Description: 4*30; Material: STEEL/Accessory_Rubber; Group: Groupe de modèles:IFC ERGON 14122021 (membre exclu):2154686
Pset_XX_AsBuilt - Catégorie: Ossature; Famille: Forme directe; Type: 4*30; Identifiant: 30; Durée de garantie (mois): 0; Périodicité de contrôle (mois): 0
Pset_XX_Poutres - Résistance au feu: RF60

# IfcBeam: 4*30 12, NE6
In: ETAGE 00 (0)
Description: 4*30; Material: STEEL/Accessory_Rubber; Group: Groupe de modèles:IFC ERGON 14122021 (membre exclu):2154686
Pset_XX_AsBuilt - Catégorie: Ossature; Famille: Forme directe; Type: 4*30; Identifiant: 29; Durée de garantie (mois): 0; Périodicité de contrôle (mois): 0
Pset_XX_Poutres - Résistance au feu: RF60

# IfcBeam: 4*30 13, NE6
In: ETAGE 00 (0)
Description: 4*30; Material: STEEL/Accessory_Rubber; Group: Groupe de modèles:IFC ERGON 14122021 (membre exclu):2154686
Pset_XX_AsBuilt - Catégorie: Ossature; Famille: Forme directe; Type: 4*30; Identifiant: 53; Durée de garantie (mois): 0; Périodicité de contrôle (mois): 0
Pset_XX_Poutres - Résistance au feu: RF60

# IfcBeam: 4*30 14 (4)
In: ETAGE 00 (0)
Description: 4*30; Material: STEEL/Accessory_Rubber; Group: Groupe de modèles:IFC ERGON 14122021 (membre exclu):2154686
Pset_XX_AsBuilt - Catégorie: Ossature; Famille: Forme directe; Type: 4*30; Identifiant: 25; Durée de garantie (mois): 0; Périodicité de contrôle (mois): 0
Pset_XX_Poutres - Résistance au feu: RF60

# IfcBeam: 4*30 15 (4)
In: ETAGE 00 (0)
Description: 4*30; Material: STEEL/Accessory_Rubber; Group: Groupe de modèles:IFC ERGON 14122021 (membre exclu):2154686
Pset_XX_AsBuilt - Catégorie: Ossature; Famille: Forme directe; Type: 4*30; Identifiant: 20; Durée de garantie (mois): 0; Périodicité de contrôle (mois): 0
Pset_XX_Poutres - Résistance au feu: RF60

# IfcBeam: 4*30 2 (2)
In: ETAGE 00 (0)
Description: 4*30; Material: STEEL/Accessory_Rubber; Group: Groupe de modèles:IFC ERGON 14122021 (membre exclu):2154686
Pset_XX_AsBuilt - Catégorie: Ossature; Famille: Forme directe; Type: 4*30; Identifiant: 37; Durée de garantie (mois): 0; Périodicité de contrôle (mois): 0
Pset_XX_Poutres - Résistance au feu: RF60

# IfcBeam: 4*30 3 (2)
In: ETAGE 00 (0)
Description: 4*30; Material: STEEL/Accessory_Rubber; Group: Groupe de modèles:IFC ERGON 14122021 (membre exclu):2154686
Pset_XX_AsBuilt - Catégorie: Ossature; Famille: Forme directe; Type: 4*30; Identifiant: 38; Durée de garantie (mois): 0; Périodicité de contrôle (mois): 0
Pset_XX_Poutres - Résistance au feu: RF60

# IfcBeam: 4*30 4 (2)
In: ETAGE 00 (0)
Description: 4*30; Material: STEEL/Accessory_Rubber; Group: Groupe de modèles:IFC ERGON 14122021 (membre exclu):2154686
Pset_XX_AsBuilt - Catégorie: Ossature; Famille: Forme directe; Type: 4*30; Identifiant: 39; Durée de garantie (mois): 0; Périodicité de contrôle (mois): 0
Pset_XX_Poutres - Résistance au feu: RF60

# IfcBeam: 4*30 5, NE6
In: ETAGE 00 (0)
Description: 4*30; Material: STEEL/Accessory_Rubber; Group: Groupe de modèles:IFC ERGON 14122021 (membre exclu):2154686
Pset_XX_AsBuilt - Catégorie: Ossature; Famille: Forme directe; Type: 4*30; Identifiant: 41; Durée de garantie (mois): 0; Périodicité de contrôle (mois): 0
Pset_XX_Poutres - Résistance au feu: RF60

# IfcBeam: 4*30 6, NE6
In: ETAGE 00 (0)
Description: 4*30; Material: STEEL/Accessory_Rubber; Group: Groupe de modèles:IFC ERGON 14122021 (membre exclu):2154686
Pset_XX_AsBuilt - Catégorie: Ossature; Famille: Forme directe; Type: 4*30; Identifiant: 42; Durée de garantie (mois): 0; Périodicité de contrôle (mois): 0
Pset_XX_Poutres - Résistance au feu: RF60

# IfcBeam: 4*30 7, NE6
In: ETAGE 00 (0)
Description: 4*30; Material: STEEL/Accessory_Rubber; Group: Groupe de modèles:IFC ERGON 14122021 (membre exclu):2154686
Pset_XX_AsBuilt - Catégorie: Ossature; Famille: Forme directe; Type: 4*30; Identifiant: 32; Durée de garantie (mois): 0; Périodicité de contrôle (mois): 0
Pset_XX_Poutres - Résistance au feu: RF60

# IfcBeam: 4*30 8 (2)
In: ETAGE 00 (0)
Description: 4*30; Material: STEEL/Accessory_Rubber; Group: Groupe de modèles:IFC ERGON 14122021 (membre exclu):2154686
Pset_XX_AsBuilt - Catégorie: Ossature; Famille: Forme directe; Type: 4*30; Identifiant: 179; Durée de garantie (mois): 0; Périodicité de contrôle (mois): 0
Pset_XX_Poutres - Résistance au feu: RF60

# IfcBeam: 4*30 9, NE6
In: ETAGE 00 (0)
Description: 4*30; Material: STEEL/Accessory_Rubber; Group: Groupe de modèles:IFC ERGON 14122021 (membre exclu):2154686
Pset_XX_AsBuilt - Catégorie: Ossature; Famille: Forme directe; Type: 4*30; Identifiant: 160; Durée de garantie (mois): 0; Périodicité de contrôle (mois): 0
Pset_XX_Poutres - Résistance au feu: RF60

# IfcBeam: 5*1 (3)
In: ETAGE 20 (2)
Description: 5*1; Material: STEEL/Accessory_invisible 261; Group: Groupe de modèles:IFC ERGON 14122021 (membre exclu):2154686
Pset_XX_AsBuilt - Catégorie: Ossature; Famille: Forme directe; Type: 5*1; Identifiant: 141; Durée de garantie (mois): 0; Périodicité de contrôle (mois): 0
Pset_XX_Poutres - Résistance au feu: RF60

# IfcBeam: 5*1 2 (3)
In: ETAGE 20 (2)
Description: 5*1; Material: STEEL/Accessory_invisible 261; Group: Groupe de modèles:IFC ERGON 14122021 (membre exclu):2154686
Pset_XX_AsBuilt - Catégorie: Ossature; Famille: Forme directe; Type: 5*1; Identifiant: 142; Durée de garantie (mois): 0; Périodicité de contrôle (mois): 0
Pset_XX_Poutres - Résistance au feu: RF60

# IfcBeam: 500*102 (8)
In: ETAGE 00 (0)
Description: 500*102; Group: Groupe de modèles:IFC ERGON 14122021 (membre exclu):2154686
Pset_XX_AsBuilt - Catégorie: Ossature; Famille: Forme directe; Type: 500*102; Identifiant: 99; Durée de garantie (mois): 0; Périodicité de contrôle (mois): 0
Pset_XX_Poutres - Résistance au feu: RF60

# IfcBeam: 500*149 (24)
In: ETAGE 00 (0)
Description: 500*149; Group: Groupe de modèles:IFC ERGON 14122021 (membre exclu):2154686
Pset_XX_AsBuilt - Catégorie: Ossature; Famille: Forme directe; Type: 500*149; Identifiant: 257; Durée de garantie (mois): 0; Périodicité de contrôle (mois): 0
Pset_XX_Poutres - Résistance au feu: RF60

# IfcBeam: 6*1 (5)
In: ETAGE 10 (1)
Description: 6*1; Material: STEEL/Accessory_invisible 261; Group: Groupe de modèles:IFC ERGON 14122021 (membre exclu):2154686
Pset_XX_AsBuilt - Catégorie: Ossature; Famille: Forme directe; Type: 6*1; Durée de garantie (mois): 0; Périodicité de contrôle (mois): 0
Pset_XX_Poutres - Résistance au feu: RF60
Name | Identifiant
4 x BEK4 | 130
BEK4 | 149

# IfcBeam: 6*1 2, BEK4
In: ETAGE 10 (1)
Description: 6*1; Material: STEEL/Accessory_invisible 261; Group: Groupe de modèles:IFC ERGON 14122021 (membre exclu):2154686
Pset_XX_AsBuilt - Catégorie: Ossature; Famille: Forme directe; Type: 6*1; Identifiant: 249; Durée de garantie (mois): 0; Périodicité de contrôle (mois): 0
Pset_XX_Poutres - Résistance au feu: RF60

# IfcBeam: 6*1 3 (4)
In: ETAGE 10 (1)
Description: 6*1; Material: STEEL/Accessory_invisible 261; Group: Groupe de modèles:IFC ERGON 14122021 (membre exclu):2154686
Pset_XX_AsBuilt - Catégorie: Ossature; Famille: Forme directe; Type: 6*1; Durée de garantie (mois): 0; Périodicité de contrôle (mois): 0
Pset_XX_Poutres - Résistance au feu: RF60
Name | Identifiant
2 x BEK4 | 127
2 x BEK4 | 150

# IfcBeam: 6*1 4 (5)
In: ETAGE 10 (1)
Description: 6*1; Material: STEEL/Accessory_invisible 261; Group: Groupe de modèles:IFC ERGON 14122021 (membre exclu):2154686
Pset_XX_AsBuilt - Catégorie: Ossature; Famille: Forme directe; Type: 6*1; Durée de garantie (mois): 0; Périodicité de contrôle (mois): 0
Pset_XX_Poutres - Résistance au feu: RF60
Name | Identifiant
2 x BEK4 | 135
3 x BEK4 | 152

# IfcBeam: 6*1 5 (3)
In: ETAGE 10 (1)
Description: 6*1; Material: STEEL/Accessory_invisible 261; Group: Groupe de modèles:IFC ERGON 14122021 (membre exclu):2154686
Pset_XX_AsBuilt - Catégorie: Ossature; Famille: Forme directe; Type: 6*1; Identifiant: 138; Durée de garantie (mois): 0; Périodicité de contrôle (mois): 0
Pset_XX_Poutres - Résistance au feu: RF60

# IfcBeam: 6*1 6, BEK4
In: ETAGE 10 (1)
Description: 6*1; Material: STEEL/Accessory_invisible 261; Group: Groupe de modèles:IFC ERGON 14122021 (membre exclu):2154686
Pset_XX_AsBuilt - Catégorie: Ossature; Famille: Forme directe; Type: 6*1; Identifiant: 253; Durée de garantie (mois): 0; Périodicité de contrôle (mois): 0
Pset_XX_Poutres - Résistance au feu: RF60

# IfcBeam: 6*1 7, BEK4
In: ETAGE 10 (1)
Description: 6*1; Material: STEEL/Accessory_invisible 261; Group: Groupe de modèles:IFC ERGON 14122021 (membre exclu):2154686
Pset_XX_AsBuilt - Catégorie: Ossature; Famille: Forme directe; Type: 6*1; Identifiant: 243; Durée de garantie (mois): 0; Périodicité de contrôle (mois): 0
Pset_XX_Poutres - Résistance au feu: RF60

# IfcBeam: 6*1 8, BEK4
In: ETAGE 10 (1)
Description: 6*1; Material: STEEL/Accessory_invisible 261; Group: Groupe de modèles:IFC ERGON 14122021 (membre exclu):2154686
Pset_XX_AsBuilt - Catégorie: Ossature; Famille: Forme directe; Type: 6*1; Identifiant: 147; Durée de garantie (mois): 0; Périodicité de contrôle (mois): 0
Pset_XX_Poutres - Résistance au feu: RF60

# IfcBeam: 6*1 9, BEK4
In: ETAGE 10 (1)
Description: 6*1; Material: STEEL/Accessory_invisible 261; Group: Groupe de modèles:IFC ERGON 14122021 (membre exclu):2154686
Pset_XX_AsBuilt - Catégorie: Ossature; Famille: Forme directe; Type: 6*1; Identifiant: 150; Durée de garantie (mois): 0; Périodicité de contrôle (mois): 0
Pset_XX_Poutres - Résistance au feu: RF60

# IfcBeam: 8*1 (11)
Description: 8*1; Material: STEEL/Accessory_invisible 261; Group: Groupe de modèles:IFC ERGON 14122021 (membre exclu):2154686
Pset_XX_AsBuilt - Catégorie: Ossature; Famille: Forme directe; Type: 8*1; Durée de garantie (mois): 0; Périodicité de contrôle (mois): 0
Pset_XX_Poutres - Résistance au feu: RF60
Name | In | Identifiant
4 x BEK4 | ETAGE 10 (1) | 129
BEK4 | ETAGE 10 (1) | 114
3 x BEK4 | ETAGE 20 (2) | 129
3 x BEK4 | ETAGE 20 (2) | 114

# IfcBeam: 8*1 2, BEK4
In: ETAGE 10 (1)
Description: 8*1; Material: STEEL/Accessory_invisible 261; Group: Groupe de modèles:IFC ERGON 14122021 (membre exclu):2154686
Pset_XX_AsBuilt - Catégorie: Ossature; Famille: Forme directe; Type: 8*1; Identifiant: 114; Durée de garantie (mois): 0; Périodicité de contrôle (mois): 0
Pset_XX_Poutres - Résistance au feu: RF60

# IfcBeam: 8*1 3 (2)
In: ETAGE 20 (2)
Description: 8*1; Material: STEEL/Accessory_invisible 261; Group: Groupe de modèles:IFC ERGON 14122021 (membre exclu):2154686
Pset_XX_AsBuilt - Catégorie: Ossature; Famille: Forme directe; Type: 8*1; Identifiant: 129; Durée de garantie (mois): 0; Périodicité de contrôle (mois): 0
Pset_XX_Poutres - Résistance au feu: RF60

# IfcBeam: 8*1 4 (3)
In: ETAGE 20 (2)
Description: 8*1; Material: STEEL/Accessory_invisible 261; Group: Groupe de modèles:IFC ERGON 14122021 (membre exclu):2154686
Pset_XX_AsBuilt - Catégorie: Ossature; Famille: Forme directe; Type: 8*1; Durée de garantie (mois): 0; Périodicité de contrôle (mois): 0
Pset_XX_Poutres - Résistance au feu: RF60
Name | Identifiant
2 x BEK4 | 114
BEK4 | 129

# IfcBeam: 9*1 (2)
In: ETAGE 10 (1)
Description: 9*1; Material: STEEL/Accessory_invisible 261; Group: Groupe de modèles:IFC ERGON 14122021 (membre exclu):2154686
Pset_XX_AsBuilt - Catégorie: Ossature; Famille: Forme directe; Type: 9*1; Identifiant: 132; Durée de garantie (mois): 0; Périodicité de contrôle (mois): 0
Pset_XX_Poutres - Résistance au feu: RF60

# IfcBeam: 9*1 2, BEK4
In: ETAGE 10 (1)
Description: 9*1; Material: STEEL/Accessory_invisible 261; Group: Groupe de modèles:IFC ERGON 14122021 (membre exclu):2154686
Pset_XX_AsBuilt - Catégorie: Ossature; Famille: Forme directe; Type: 9*1; Identifiant: 251; Durée de garantie (mois): 0; Périodicité de contrôle (mois): 0
Pset_XX_Poutres - Résistance au feu: RF60

# IfcBeam: ACC_ANKRA_A5 (30)
In: ETAGE 20 (2)
Description: ACC_ANKRA_A5; Group: Groupe de modèles:IFC ERGON 14122021 (membre exclu):2154686
Pset_XX_AsBuilt - Catégorie: Ossature; Famille: Forme directe; Type: ACC_ANKRA_A5; Durée de garantie (mois): 0; Périodicité de contrôle (mois): 0
Pset_XX_Poutres - Résistance au feu: RF60
Name | Identifiant
7 x RA51 | 327
5 x RA51 | 326
2 x RA51 | 328
2 x RA51 | 329
14 x RA51 | 330

# IfcBeam: B.A. 20x(23+27)cm (C30/37) (2)
In: ETAGE 00 (0)
Classification: 28. OSSATURE (https://www.csiresources.org/standards/uniformat); Material: BS_28_Ossature en béton armé - Eléments coulé sur place
Pset_XX_AsBuilt - Catégorie: Ossature; Classification BBsfB: 28.; Numéro d'article du CCTB: 22.11.1a; Fabricant: De Graeve; Fournisseur/Installateur: De Graeve; Famille: BS_28_SF_LE_Poutre rectangulaire_coulé; Type: B.A. 20x(23+27)cm (C30/37); Durée de garantie (mois): 0; Périodicité de contrôle (mois): 0
Pset_XX_Poutres - Résistance au feu: RF60
Name (BS_28_SF_LE_Poutre rectangulaire_coulé:B.A. 20x(23+27)cm (C30/37):...)
1304709
1304804

# IfcBeam: B.A. 20x60cm (3)
In: FOND 00 (0)
Classification: 17. PIEUX (https://www.csiresources.org/standards/uniformat); Material: BS_16_Plot en béton armé coulé sur place
Pset_XX_AsBuilt - Catégorie: Ossature; Classification BBsfB: 17.; Numéro d'article du CCTB: 13.31.1a.05; Fabricant: De Graeve; Fournisseur/Installateur: De Graeve; Famille: BS_17_SFO_LE_Poutre de fondation; Type: B.A. 20x60cm; Durée de garantie (mois): 0; Périodicité de contrôle (mois): 0
Pset_XX_Poutres - Résistance au feu: RF60; Construction: Coulé; Taux de ferraillage (kg/m³): 140; sets with these values: 2
Name (BS_17_SFO_LE_Poutre de fondation:B.A. 20x60cm:...)
1702620
1703419
1703609

# IfcBeam: B.A. 40x40cm (6)
In: FOND 00 (0)
Classification: 17. PIEUX (https://www.csiresources.org/standards/uniformat); Material: BS_16_Plot en béton armé coulé sur place
Pset_XX_AsBuilt - Catégorie: Ossature; Classification BBsfB: 17.; Numéro d'article du CCTB: 13.31.1a.05; Fabricant: De Graeve; Fournisseur/Installateur: De Graeve; Famille: BS_17_SFO_LE_Poutre de fondation; Type: B.A. 40x40cm; Durée de garantie (mois): 0; Périodicité de contrôle (mois): 0
Pset_XX_Poutres - Résistance au feu: RF60; Construction: Coulé; Taux de ferraillage (kg/m³): 140; sets with these values: 2
Name (BS_17_SFO_LE_Poutre de fondation:B.A. 40x40cm:...)
2034028
2034478
2034841
2037518
2047790
2048141

# IfcBeam: B.A. 40x50cm (noeud CSP), BS_28_SF_LE_Poutre rectangulaire_coulé:B.A. 40x50cm (noeud CSP):1981608
In: ETAGE 00 (0)
Classification: 28. OSSATURE (https://www.csiresources.org/standards/uniformat); Material: BS_28_Ossature en béton armé - Eléments coulé sur place
Pset_XX_AsBuilt - Catégorie: Ossature; Classification BBsfB: 28.; Numéro d'article du CCTB: 22.15.3d; Fabricant: De Graeve; Fournisseur/Installateur: De Graeve; Famille: BS_28_SF_LE_Poutre rectangulaire_coulé; Type: B.A. 40x50cm (noeud CSP); Durée de garantie (mois): 0; Périodicité de contrôle (mois): 0
Pset_XX_Poutres - Résistance au feu: RF60

# IfcBeam: B.A. 40x50cm (noeud CSP) 2, BS_28_SF_LE_Poutre rectangulaire_coulé:B.A. 40x50cm (noeud CSP):1981722
In: ETAGE 00 (0)
Classification: 28. OSSATURE (https://www.csiresources.org/standards/uniformat); Material: BS_28_Ossature en béton armé - Eléments coulé sur place
Pset_XX_AsBuilt - Catégorie: Ossature; Classification BBsfB: 28.; Numéro d'article du CCTB: 22.15.3d; Fabricant: De Graeve; Fournisseur/Installateur: De Graeve; Famille: BS_28_SF_LE_Poutre rectangulaire_coulé; Type: B.A. 40x50cm (noeud CSP); Durée de garantie (mois): 0; Périodicité de contrôle (mois): 0
Pset_XX_Poutres - Résistance au feu: RF60

# IfcBeam: B.A. 40x50cm (noeud CSP) 3, BS_28_SF_LE_Poutre rectangulaire_coulé:B.A. 40x50cm (noeud CSP):1981756
In: ETAGE 00 (0)
Classification: 28. OSSATURE (https://www.csiresources.org/standards/uniformat); Material: BS_28_Ossature en béton armé - Eléments coulé sur place
Pset_XX_AsBuilt - Catégorie: Ossature; Classification BBsfB: 28.; Numéro d'article du CCTB: 22.15.3d; Fabricant: De Graeve; Fournisseur/Installateur: De Graeve; Famille: BS_28_SF_LE_Poutre rectangulaire_coulé; Type: B.A. 40x50cm (noeud CSP); Durée de garantie (mois): 0; Périodicité de contrôle (mois): 0
Pset_XX_Poutres - Résistance au feu: RF60

# IfcBeam: B.A. 60x40cm (2)
In: FOND 00 (0)
Classification: 17. PIEUX (https://www.csiresources.org/standards/uniformat); Material: BS_16_Plot en béton armé coulé sur place
Pset_XX_AsBuilt - Catégorie: Ossature; Classification BBsfB: 17.; Numéro d'article du CCTB: 13.31.1a.05; Fabricant: De Graeve; Fournisseur/Installateur: De Graeve; Famille: BS_17_SFO_LE_Poutre de fondation; Type: B.A. 60x40cm; Durée de garantie (mois): 0; Périodicité de contrôle (mois): 0
Pset_XX_Poutres - Résistance au feu: RF60; Construction: Coulé; Taux de ferraillage (kg/m³): 140; sets with these values: 2
Name (BS_17_SFO_LE_Poutre de fondation:B.A. 60x40cm:...)
2022326
2022633

# IfcBeam: CORBEL200-150-180 (17)
In: ETAGE 00 (0)
Description: CORBEL200-150-180; Classification: 28. OSSATURE (https://www.csiresources.org/standards/uniformat); Material: STEEL/Accessory_C50/60 64192; Group: Groupe de modèles:IFC ERGON 14122021 (membre exclu):2154686
Pset_XX_AsBuilt - Catégorie: Ossature; Classification BBsfB: 28.; Numéro d'article du CCTB: 22.14.3a; Fabricant: ERGON; Fournisseur/Installateur: De Graeve; Famille: Forme directe; Type: CORBEL200-150-180; Durée de garantie (mois): 0; Périodicité de contrôle (mois): 0
Pset_XX_Poutres - Résistance au feu: RF60; Construction: Préfabriqué
Name | Identifiant
13 x BEK1 | 79
3 x BEK1 | 80
BEK1 | 8

# IfcBeam: CORBEL200-200-175 (10)
In: ETAGE 10 (1)
Description: CORBEL200-200-175; Classification: 28. OSSATURE (https://www.csiresources.org/standards/uniformat); Material: STEEL/Accessory_C60/75; Group: Groupe de modèles:IFC ERGON 14122021 (membre exclu):2154686
Pset_XX_AsBuilt - Catégorie: Ossature; Classification BBsfB: 28.; Numéro d'article du CCTB: 22.14.3a; Fabricant: ERGON; Fournisseur/Installateur: De Graeve; Famille: Forme directe; Type: CORBEL200-200-175; Durée de garantie (mois): 0; Périodicité de contrôle (mois): 0
Pset_XX_Poutres - Résistance au feu: RF60; Construction: Préfabriqué
Name | Identifiant
5 x BEK1 | 297
5 x BEK1 | 298

# IfcBeam: CORBEL300-300-260 (24)
Description: CORBEL300-300-260; Classification: 28. OSSATURE (https://www.csiresources.org/standards/uniformat); Group: Groupe de modèles:IFC ERGON 14122021 (membre exclu):2154686
Pset_XX_AsBuilt - Catégorie: Ossature; Classification BBsfB: 28.; Numéro d'article du CCTB: 22.14.3a; Fabricant: ERGON; Fournisseur/Installateur: De Graeve; Famille: Forme directe; Type: CORBEL300-300-260; Durée de garantie (mois): 0; Périodicité de contrôle (mois): 0
Pset_XX_Poutres - Résistance au feu: RF60; Construction: Préfabriqué
Name | In | Material | Identifiant
6 x BEK1 | ETAGE 00 (0) | STEEL/Accessory_C50/60 64192 | 11
6 x BEK1 | ETAGE 00 (0) | STEEL/Accessory_C50/60 64192 | 12
5 x BEK1 | ETAGE 00 (0) | STEEL/Accessory_C50/60 64192 | 16
BEK1 | ETAGE 00 (0) | STEEL/Accessory_C60/75 | 223
BEK1 | ETAGE 10 (1) | STEEL/Accessory_C50/60 64192 | 224
BEK1 | ETAGE 10 (1) | STEEL/Accessory_C50/60 64192 | 245
BEK1 | ETAGE 10 (1) | STEEL/Accessory_C50/60 64192 | 230
BEK1 | ETAGE 10 (1) | STEEL/Accessory_C50/60 64192 | 5
BEK1 | ETAGE 10 (1) | STEEL/Accessory_C60/75 | 223
BEK1 | ETAGE 10 (1) | STEEL/Accessory_C50/60 64192 | 16

# IfcBeam: CORBEL400-300-360 (6)
In: ETAGE 00 (0)
Description: CORBEL400-300-360; Classification: 28. OSSATURE (https://www.csiresources.org/standards/uniformat); Group: Groupe de modèles:IFC ERGON 14122021 (membre exclu):2154686
Pset_XX_AsBuilt - Catégorie: Ossature; Classification BBsfB: 28.; Numéro d'article du CCTB: 22.14.3a; Fabricant: ERGON; Fournisseur/Installateur: De Graeve; Famille: Forme directe; Type: CORBEL400-300-360; Durée de garantie (mois): 0; Périodicité de contrôle (mois): 0
Pset_XX_Poutres - Résistance au feu: RF60; Construction: Préfabriqué
Name | Material | Identifiant
BEK1 | STEEL/Accessory_C50/60 64192 | 225
BEK1 | STEEL/Accessory_C50/60 64192 | 10
2 x BEK1 | STEEL/Accessory_C60/75 | 227
BEK1 | STEEL/Accessory_C50/60 64192 | 228
BEK1 | STEEL/Accessory_C50/60 64192 | 229

# IfcBeam: CRH_R_300*290*15 (4)
In: ETAGE 20 (2)
Description: CRH_R_300*290*15; Classification: 28. OSSATURE (https://www.csiresources.org/standards/uniformat); Group: Groupe de modèles:IFC ERGON 14122021 (membre exclu):2154686
Pset_XX_AsBuilt - Catégorie: Ossature; Classification BBsfB: 28.; Numéro d'article du CCTB: 22.11.3c; Fabricant: ERGON; Fournisseur/Installateur: De Graeve; Famille: Forme directe; Type: CRH_R_300*290*15; Durée de garantie (mois): 0; Périodicité de contrôle (mois): 0; Référence FT**: PLA_022
Pset_XX_Poutres - Résistance au feu: RF60; Construction: Préfabriqué
Name | Identifiant | Taux de ferraillage (kg/m³)
BEAM | B32 | 122.49
BEAM | B31 | 118.96
BEAM | B30 | 111.39
BEAM | B33 | 106.16

# IfcBeam: CRH_R_300*390*15 (4)
In: ETAGE 20 (2)
Description: CRH_R_300*390*15; Classification: 28. OSSATURE (https://www.csiresources.org/standards/uniformat); Group: Groupe de modèles:IFC ERGON 14122021 (membre exclu):2154686
Pset_XX_AsBuilt - Catégorie: Ossature; Classification BBsfB: 28.; Numéro d'article du CCTB: 22.11.3c; Fabricant: ERGON; Fournisseur/Installateur: De Graeve; Famille: Forme directe; Type: CRH_R_300*390*15; Durée de garantie (mois): 0; Périodicité de contrôle (mois): 0; Référence FT**: PLA_022
Pset_XX_Poutres - Résistance au feu: RF60; Construction: Préfabriqué
Name | Identifiant | Taux de ferraillage (kg/m³)
BEAM | B20 | 124.39
BEAM | B21 | 124.2
BEAM | B19 | 127.29
BEAM | B22 | 124.38

# IfcBeam: CRH_R_400*290*15 (12)
In: ETAGE 10 (1)
Description: CRH_R_400*290*15; Classification: 28. OSSATURE (https://www.csiresources.org/standards/uniformat); Group: Groupe de modèles:IFC ERGON 14122021 (membre exclu):2154686
Pset_XX_AsBuilt - Catégorie: Ossature; Classification BBsfB: 28.; Numéro d'article du CCTB: 22.11.3c; Fabricant: ERGON; Fournisseur/Installateur: De Graeve; Famille: Forme directe; Type: CRH_R_400*290*15; Durée de garantie (mois): 0; Périodicité de contrôle (mois): 0; Référence FT**: PLA_022
Pset_XX_Poutres - Résistance au feu: RF60; Construction: Préfabriqué
Name | Identifiant | Taux de ferraillage (kg/m³)
BEAM | B43 | 105.66
BEAM | B44 | 105.66
BEAM | B46 | 116.91
BEAM | B42 | 149.51
BEAM | B27 | 116.91
2 x BEAM | B37 | 116.66
2 x BEAM | B47 | 102.67
BEAM | B24 | 105.17
BEAM | B28 | 105.17
BEAM | B29 | 93.34

# IfcBeam: CRH_R_400*390*15 (5)
In: ETAGE 10 (1)
Description: CRH_R_400*390*15; Classification: 28. OSSATURE (https://www.csiresources.org/standards/uniformat); Group: Groupe de modèles:IFC ERGON 14122021 (membre exclu):2154686
Pset_XX_AsBuilt - Catégorie: Ossature; Classification BBsfB: 28.; Numéro d'article du CCTB: 22.11.3c; Fabricant: ERGON; Fournisseur/Installateur: De Graeve; Famille: Forme directe; Type: CRH_R_400*390*15; Durée de garantie (mois): 0; Périodicité de contrôle (mois): 0; Référence FT**: PLA_022
Pset_XX_Poutres - Résistance au feu: RF60; Construction: Préfabriqué
Name | Identifiant | Taux de ferraillage (kg/m³)
BEAM | B36 | 118.1
BEAM | B26 | 91.13
BEAM | B25 | 71.14
BEAM | B34 | 116.64
BEAM | B35 | 102.93

# IfcBeam: D14 (12)
In: ETAGE 00 (0)
Description: D14; Material: STEEL/Accessory 32414; Group: Groupe de modèles:IFC ERGON 14122021 (membre exclu):2154686
Pset_XX_AsBuilt - Catégorie: Ossature; Famille: Forme directe; Type: D14; Durée de garantie (mois): 0; Périodicité de contrôle (mois): 0
Pset_XX_Poutres - Résistance au feu: RF60
Name | Identifiant
4 x ZW6 | 279
4 x ZW6 | 270
4 x ZW6 | 269

# IfcBeam: D15 (12)
In: ETAGE 00 (0)
Description: D15; Material: STEEL/Accessory; Group: Groupe de modèles:IFC ERGON 14122021 (membre exclu):2154686
Pset_XX_AsBuilt - Catégorie: Ossature; Famille: Forme directe; Type: D15; Durée de garantie (mois): 0; Périodicité de contrôle (mois): 0
Pset_XX_Poutres - Résistance au feu: RF60
Name | Identifiant
6 x SD12 | 93
6 x SD12 | 90

# IfcBeam: D19 (12)
In: ETAGE 00 (0)
Description: D19; Material: STEEL/Accessory; Group: Groupe de modèles:IFC ERGON 14122021 (membre exclu):2154686
Pset_XX_AsBuilt - Catégorie: Ossature; Famille: Forme directe; Type: D19; Durée de garantie (mois): 0; Périodicité de contrôle (mois): 0
Pset_XX_Poutres - Résistance au feu: RF60
Name | Identifiant
6 x SD12 | 92
6 x SD12 | 87

# IfcBeam: D24 (18)
In: ETAGE 10 (1)
Description: D24; Group: Groupe de modèles:IFC ERGON 14122021 (membre exclu):2154686
Pset_XX_AsBuilt - Catégorie: Ossature; Famille: Forme directe; Type: D24; Durée de garantie (mois): 0; Périodicité de contrôle (mois): 0
Pset_XX_Poutres - Résistance au feu: RF60
Name | Identifiant
16 x SD11 | 237
2 x SD11 | 222

# IfcBeam: D30 (72)
Description: D30; Group: Groupe de modèles:IFC ERGON 14122021 (membre exclu):2154686
Pset_XX_AsBuilt - Catégorie: Ossature; Famille: Forme directe; Type: D30; Durée de garantie (mois): 0; Périodicité de contrôle (mois): 0
Pset_XX_Poutres - Résistance au feu: RF60
Name | In | Identifiant
32 x SD11 | ETAGE 00 (0) | 15
11 x SD11 | ETAGE 00 (0) | 235
SD11 | ETAGE 00 (0) | 238
16 x SD12 | ETAGE 00 (0) | 347 | Material: STEEL/Accessory
12 x SD12 | ETAGE 10 (1) | 317 | Material: STEEL/Accessory

# IfcBeam: D35 (24)
In: ETAGE 10 (1)
Description: D35; Material: STEEL/Accessory_Hole_Concrete 8616; Group: Groupe de modèles:IFC ERGON 14122021 (membre exclu):2154686
Pset_XX_AsBuilt - Catégorie: Ossature; Famille: Forme directe; Type: D35; Durée de garantie (mois): 0; Périodicité de contrôle (mois): 0
Pset_XX_Poutres - Résistance au feu: RF60
Name | Identifiant
12 x ZW9 | 309
12 x ZW9 | 313

# IfcBeam: D56 (80)
Description: D56; Material: STEEL/Accessory 22919; Group: Groupe de modèles:IFC ERGON 14122021 (membre exclu):2154686
Pset_XX_AsBuilt - Catégorie: Ossature; Famille: Forme directe; Type: D56; Identifiant: 213; Durée de garantie (mois): 0; Périodicité de contrôle (mois): 0
Pset_XX_Poutres - Résistance au feu: RF60
Name | In
39 x TA4 | ETAGE 00 (0)
41 x TA4 | ETAGE 10 (1)

# IfcBeam: D7 (32)
In: ETAGE 00 (0)
Description: D7; Group: Groupe de modèles:IFC ERGON 14122021 (membre exclu):2154686
Pset_XX_AsBuilt - Catégorie: Ossature; Famille: Forme directe; Type: D7; Identifiant: 95; Durée de garantie (mois): 0; Périodicité de contrôle (mois): 0
Pset_XX_Poutres - Résistance au feu: RF60

# IfcBeam: EB_I_A290*100*90*60*150*290*120*900*15 (6)
In: ETAGE 10 (1)
Description: EB_I_A290*100*90*60*150*290*120*900*15; Classification: 28. OSSATURE (https://www.csiresources.org/standards/uniformat); Group: Groupe de modèles:IFC ERGON 14122021 (membre exclu):2154686
Pset_XX_AsBuilt - Catégorie: Ossature; Classification BBsfB: 28.; Numéro d'article du CCTB: 22.11.3c; Fabricant: ERGON; Fournisseur/Installateur: De Graeve; Famille: Forme directe; Type: EB_I_A290*100*90*60*150*290*120*900*15; Durée de garantie (mois): 0; Périodicité de contrôle (mois): 0; Référence FT**: PLA_022
Pset_XX_Poutres - Résistance au feu: RF60; Construction: Préfabriqué; Taux de ferraillage (kg/m³): 88.43
Name | Identifiant
BEAM | B50
BEAM | B54
BEAM | B53
BEAM | B52
BEAM | B51
BEAM | B49

# IfcBeam: EB_RL_A500*390*225*150*15 (4)
In: ETAGE 00 (0)
Description: EB_RL_A500*390*225*150*15; Classification: 28. OSSATURE (https://www.csiresources.org/standards/uniformat); Group: Groupe de modèles:IFC ERGON 14122021 (membre exclu):2154686
Pset_XX_AsBuilt - Catégorie: Ossature; Classification BBsfB: 28.; Numéro d'article du CCTB: 22.11.3c; Fabricant: ERGON; Fournisseur/Installateur: De Graeve; Famille: Forme directe; Type: EB_RL_A500*390*225*150*15; Durée de garantie (mois): 0; Périodicité de contrôle (mois): 0; Référence FT**: PLA_022
Pset_XX_Poutres - Résistance au feu: RF60; Construction: Préfabriqué
Name | Identifiant | Taux de ferraillage (kg/m³)
BEAM | B1 | 315.29
BEAM | B2 | 318.35 | Material: CONCRETE/C60/75 114932
BEAM | B4 | 315.36
BEAM | B3 | 318.44 | Material: CONCRETE/C60/75 114932

# IfcBeam: EB_RT_A400*590*225*150*225*150*15 (2)
In: ETAGE 00 (0)
Description: EB_RT_A400*590*225*150*225*150*15; Classification: 28. OSSATURE (https://www.csiresources.org/standards/uniformat); Group: Groupe de modèles:IFC ERGON 14122021 (membre exclu):2154686
Pset_XX_AsBuilt - Catégorie: Ossature; Classification BBsfB: 28.; Numéro d'article du CCTB: 22.11.3c; Fabricant: ERGON; Fournisseur/Installateur: De Graeve; Famille: Forme directe; Type: EB_RT_A400*590*225*150*225*150*15; Durée de garantie (mois): 0; Périodicité de contrôle (mois): 0; Référence FT**: PLA_022
Pset_XX_Poutres - Résistance au feu: RF60; Construction: Préfabriqué
Name | Identifiant | Taux de ferraillage (kg/m³)
BEAM | B5 | 324.54
BEAM | B6 | 256.59 | Material: CONCRETE/C60/75 114932

# IfcBeam: EB_R_300*390*15 (8)
In: ETAGE 00 (0)
Description: EB_R_300*390*15; Classification: 28. OSSATURE (https://www.csiresources.org/standards/uniformat); Material: CONCRETE/C50/60 61830; Group: Groupe de modèles:IFC ERGON 14122021 (membre exclu):2154686
Pset_XX_AsBuilt - Catégorie: Ossature; Classification BBsfB: 28.; Numéro d'article du CCTB: 22.11.3c; Fabricant: ERGON; Fournisseur/Installateur: De Graeve; Famille: Forme directe; Type: EB_R_300*390*15; Durée de garantie (mois): 0; Périodicité de contrôle (mois): 0; Référence FT**: PLA_022
Pset_XX_Poutres - Résistance au feu: RF60; Construction: Préfabriqué
Name | Identifiant | Taux de ferraillage (kg/m³)
BEAM | B11 | 174.62
BEAM | B45 | 164.47
BEAM | B41 | 153.59
BEAM | B48 | 164.47
BEAM | B10 | 157.89
BEAM | B9 | 180.25
BEAM | B8 | 175.64
BEAM | B7 | 165.16

# IfcBeam: EB_R_400*490*15 (4)
In: ETAGE 00 (0)
Description: EB_R_400*490*15; Classification: 28. OSSATURE (https://www.csiresources.org/standards/uniformat); Material: CONCRETE/C50/60 61830; Group: Groupe de modèles:IFC ERGON 14122021 (membre exclu):2154686
Pset_XX_AsBuilt - Catégorie: Ossature; Classification BBsfB: 28.; Numéro d'article du CCTB: 22.11.3c; Fabricant: ERGON; Fournisseur/Installateur: De Graeve; Famille: Forme directe; Type: EB_R_400*490*15; Durée de garantie (mois): 0; Périodicité de contrôle (mois): 0; Référence FT**: PLA_022
Pset_XX_Poutres - Résistance au feu: RF60; Construction: Préfabriqué
Name | Identifiant | Taux de ferraillage (kg/m³)
BEAM | B13 | 120.26
BEAM | B14 | 124.86
BEAM | B15 | 124.82
BEAM | B16 | 143.33

# IfcBeam: EB_R_500*390*15 (2)
In: ETAGE 00 (0)
Description: EB_R_500*390*15; Classification: 28. OSSATURE (https://www.csiresources.org/standards/uniformat); Material: CONCRETE/C50/60 61830; Group: Groupe de modèles:IFC ERGON 14122021 (membre exclu):2154686
Pset_XX_AsBuilt - Catégorie: Ossature; Classification BBsfB: 28.; Numéro d'article du CCTB: 22.11.3c; Fabricant: ERGON; Fournisseur/Installateur: De Graeve; Famille: Forme directe; Type: EB_R_500*390*15; Durée de garantie (mois): 0; Périodicité de contrôle (mois): 0; Référence FT**: PLA_022
Pset_XX_Poutres - Résistance au feu: RF60; Construction: Préfabriqué
Name | Identifiant | Taux de ferraillage (kg/m³)
BEAM | B18 | 134.63
BEAM | B17 | 120.66

# IfcBeam: EB_SP200 (64)
In: ETAGE 00 (0)
Description: EB_SP200; Classification: 28. OSSATURE (https://www.csiresources.org/standards/uniformat); Group: Groupe de modèles:IFC ERGON 14122021 (membre exclu):2154686
Pset_XX_AsBuilt - Catégorie: Ossature; Classification BBsfB: 28.; Numéro d'article du CCTB: 22.15.3d; Fabricant: ERGON; Fournisseur/Installateur: De Graeve; Famille: Forme directe; Type: EB_SP200; Durée de garantie (mois): 0; Périodicité de contrôle (mois): 0; Référence FT**: PLA_004
Pset_XX_Hourdis - Construction: Préfabriqué; Résistance au feu: RF60
Name | Identifiant | Surcharge admissible
2 x HOLLOWCORE SLAB | P28 | 5
HOLLOWCORE SLAB | P22 | 3
HOLLOWCORE SLAB | P23 | 3
11 x HOLLOWCORE SLAB | P13 | 3
HOLLOWCORE SLAB | P24 | 3
HOLLOWCORE SLAB | P14 | 3
4 x HOLLOWCORE SLAB | P29 | 3
HOLLOWCORE SLAB | P20 | 5
9 x HOLLOWCORE SLAB | P12 | 5
HOLLOWCORE SLAB | P17 | 5
HOLLOWCORE SLAB | P16 | 3
HOLLOWCORE SLAB | P26 | 3
HOLLOWCORE SLAB | P19 | 5
HOLLOWCORE SLAB | P18 | 5
HOLLOWCORE SLAB | P21 | 5
2 x HOLLOWCORE SLAB | P34 | 3
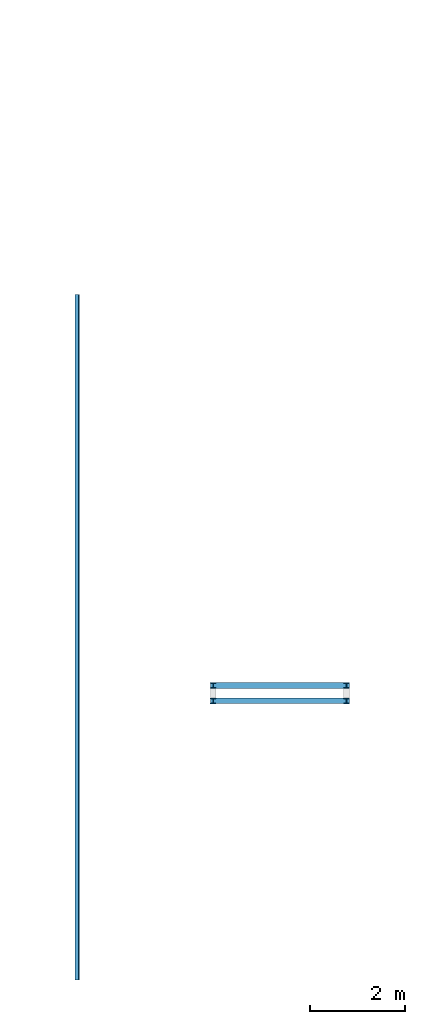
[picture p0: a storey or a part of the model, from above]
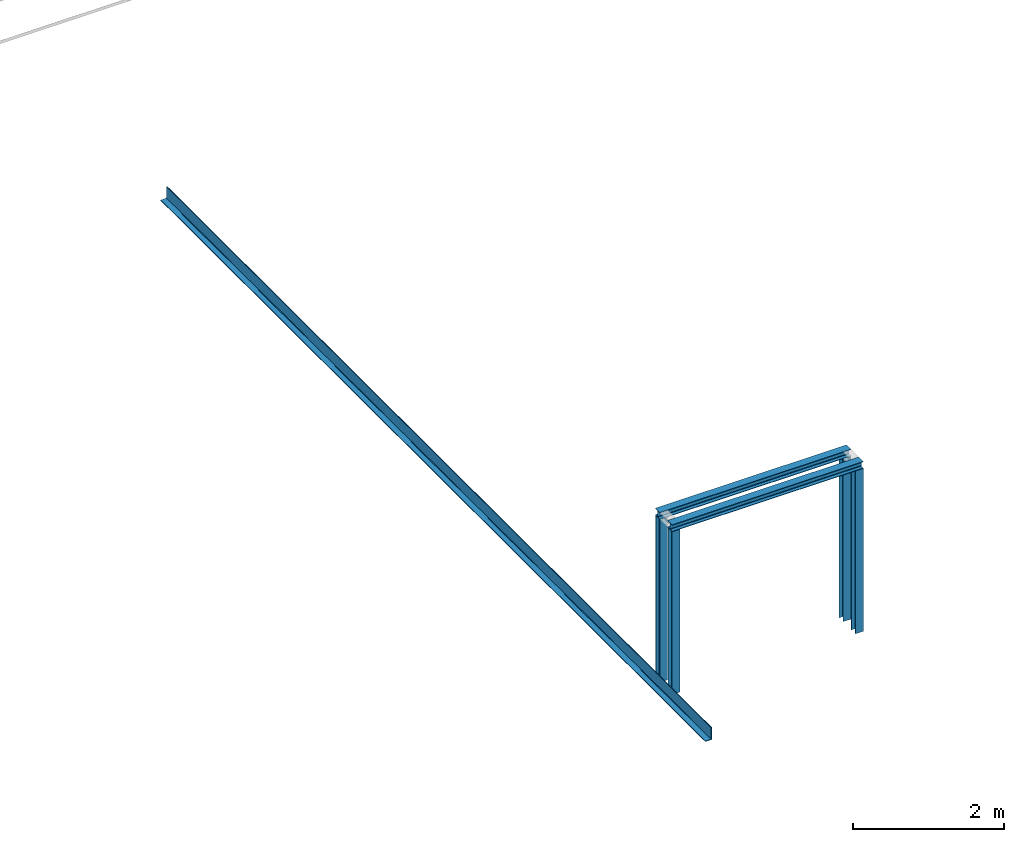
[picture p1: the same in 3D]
Properties of the parts of a building model (IFC4X3_ADD2), part 2 of 4

# IfcBeam: EB_SP200 (64)
Name | Identifiant | Surcharge admissible
5 x HOLLOWCORE SLAB | P30 | 3
3 x HOLLOWCORE SLAB | P3 | 3
HOLLOWCORE SLAB | P1 | 3
HOLLOWCORE SLAB | P32 | 3
HOLLOWCORE SLAB | P31 | 3
HOLLOWCORE SLAB | P2 | 3
HOLLOWCORE SLAB | P35
8 x HOLLOWCORE SLAB | P6 | 3
2 x HOLLOWCORE SLAB | P33 | 3
HOLLOWCORE SLAB | P5 | 3
HOLLOWCORE SLAB | P7 | 3

# IfcBeam: EB_SPN200 (4)
In: ETAGE 00 (0)
Description: EB_SPN200; Classification: 28. OSSATURE (https://www.csiresources.org/standards/uniformat); Group: Groupe de modèles:IFC ERGON 14122021 (membre exclu):2154686
Pset_XX_AsBuilt - Catégorie: Ossature; Classification BBsfB: 28.; Numéro d'article du CCTB: 22.15.3d; Fabricant: ERGON; Fournisseur/Installateur: De Graeve; Famille: Forme directe; Type: EB_SPN200; Durée de garantie (mois): 0; Périodicité de contrôle (mois): 0; Référence FT**: PLA_004
Pset_XX_Hourdis - Construction: Préfabriqué; Résistance au feu: RF60
Name | Identifiant | Surcharge admissible
HOLLOWCORE SLAB | P9 | 5
HOLLOWCORE SLAB | P11 | 5
HOLLOWCORE SLAB | P10 | 5
HOLLOWCORE SLAB | P8 | 3

# IfcBeam: HALF_IPE270_100 (12)
In: ETAGE 10 (1)
Description: HALF_IPE270_100; Classification: 28. OSSATURE (https://www.csiresources.org/standards/uniformat); Group: Groupe de modèles:IFC ERGON 14122021 (membre exclu):2154686
Pset_XX_AsBuilt - Catégorie: Ossature; Classification BBsfB: 28.; Numéro d'article du CCTB: 23.14.1; Fabricant: RS Contruction; Fournisseur/Installateur: De Graeve; Famille: Forme directe; Type: HALF_IPE270_100; Durée de garantie (mois): 0; Périodicité de contrôle (mois): 0; Référence FT**: PLA_015
Pset_XX_Poutres - Résistance au feu: RF60
Name | Identifiant
3 x PS6 | 202
PS6 | 206
2 x PS6 | 194
PS6 | 207
PS6 | 192
PS6 | 195
3 x PS6 | 211

# IfcBeam: HALF_IPE270_135 (6)
In: ETAGE 10 (1)
Description: HALF_IPE270_135; Classification: 28. OSSATURE (https://www.csiresources.org/standards/uniformat); Group: Groupe de modèles:IFC ERGON 14122021 (membre exclu):2154686
Pset_XX_AsBuilt - Catégorie: Ossature; Classification BBsfB: 28.; Numéro d'article du CCTB: 23.14.1; Fabricant: RS Contruction; Fournisseur/Installateur: De Graeve; Famille: Forme directe; Type: HALF_IPE270_135; Identifiant: 203; Durée de garantie (mois): 0; Périodicité de contrôle (mois): 0; Référence FT**: PLA_015
Pset_XX_Poutres - Résistance au feu: RF60

# IfcBeam: HEA120 2 (4)
In: ETAGE -1
Classification: 28. OSSATURE (https://www.csiresources.org/standards/uniformat); Material: BS_28_Métal
Pset_XX_AsBuilt - Catégorie: Ossature; Classification BBsfB: 28.; Numéro d'article du CCTB: 23.11.1a.01; Fabricant: RS Contruction; Fournisseur/Installateur: De Graeve; Famille: BS_28_SF_LE_HE-A; Type: HEA120; Durée de garantie (mois): 0; Périodicité de contrôle (mois): 0; Référence FT**: PLA_015
Pset_XX_Poutres - Résistance au feu: RF60
Name (BS_28_SF_LE_HE-A:HEA120:...)
1698743
1698812
1698873
1698971

# IfcBeam: HEA140 (13)
In: ETAGE 10 (1)
Classification: 28. OSSATURE (https://www.csiresources.org/standards/uniformat); Material: BS_28_Métal
Pset_XX_AsBuilt - Catégorie: Ossature; Classification BBsfB: 28.; Numéro d'article du CCTB: 23.11.1a.02; Fabricant: RS Contruction; Fournisseur/Installateur: De Graeve; Famille: BS_28_SF_LE_HE-A; Type: HEA140; Durée de garantie (mois): 0; Périodicité de contrôle (mois): 0; Référence FT**: PLA_015
Pset_XX_Poutres - Résistance au feu: RF60
Name (BS_28_SF_LE_HE-A:HEA140:...)
1304236
1304326
1377792
1484936
1673888
1678551
1678624
1679880
1945066
1955336
1955462
1955736
2917694

# IfcBeam: HEA180 (21)
Classification: 28. OSSATURE (https://www.csiresources.org/standards/uniformat); Material: BS_28_Métal
Pset_XX_AsBuilt - Catégorie: Ossature; Classification BBsfB: 28.; Numéro d'article du CCTB: 23.11.1a.03; Fabricant: RS Contruction; Fournisseur/Installateur: De Graeve; Famille: BS_28_SF_LE_HE-A; Type: HEA180; Durée de garantie (mois): 0; Périodicité de contrôle (mois): 0; Référence FT**: PLA_015
Pset_XX_Poutres - Résistance au feu: RF60
Name (BS_28_SF_LE_HE-A:HEA180:...) | In
1285061 | ETAGE 10 (1)
1287887 | ETAGE 10 (1)
1287898 | ETAGE 10 (1)
1287967 | ETAGE 10 (1)
1288028 | ETAGE 10 (1)
1288108 | ETAGE 10 (1)
1288121 | ETAGE 10 (1)
1288505 | ETAGE 10 (1)
1288511 | ETAGE 10 (1)
1288513 | ETAGE 10 (1)
1288515 | ETAGE 10 (1)
1288517 | ETAGE 10 (1)
1288519 | ETAGE 10 (1)
1288521 | ETAGE 10 (1)
1391088 | ETAGE 10 (1)
1478971 | ETAGE 10 (1)
1481763 | ETAGE 10 (1)
1481857 | ETAGE 10 (1)
1638472 | ETAGE 10 (1)
1391194 | ETAGE 20 (2)
1391243 | ETAGE 20 (2)

# IfcBeam: HEA200 2 (4)
In: ETAGE 00 (0)
Classification: 28. OSSATURE (https://www.csiresources.org/standards/uniformat); Material: BS_28_Métal
Pset_XX_AsBuilt - Catégorie: Ossature; Classification BBsfB: 28.; Numéro d'article du CCTB: 23.11.1a.04; Fabricant: RS Contruction; Fournisseur/Installateur: De Graeve; Famille: BS_28_SF_LE_HE-A; Type: HEA200; Durée de garantie (mois): 0; Périodicité de contrôle (mois): 0; Référence FT**: PLA_015
Pset_XX_Poutres - Résistance au feu: RF60
Name (BS_28_SF_LE_HE-A:HEA200:...)
1379323
1391495
3634405
3635041

# IfcBeam: HEA300 (2)
In: ETAGE 00 (0)
Classification: 28. OSSATURE (https://www.csiresources.org/standards/uniformat); Material: BS_28_Métal
Pset_XX_AsBuilt - Catégorie: Ossature; Classification BBsfB: 28.; Numéro d'article du CCTB: 23.11.1a.06; Fabricant: RS Contruction; Fournisseur/Installateur: De Graeve; Famille: BS_28_SF_LE_HE-A; Type: HEA300; Durée de garantie (mois): 0; Périodicité de contrôle (mois): 0; Référence FT**: PLA_015
Pset_XX_Poutres - Résistance au feu: RF60
Name (BS_28_SF_LE_HE-A:HEA300:...)
2166231
2166743

# IfcBeam: IPE100 (8)
In: ETAGE 10 (1)
Classification: 28. OSSATURE (https://www.csiresources.org/standards/uniformat); Material: BS_28_Métal
Pset_XX_AsBuilt - Catégorie: Ossature; Classification BBsfB: 28.; Numéro d'article du CCTB: 23.11.1; Fabricant: RS Contruction; Fournisseur/Installateur: De Graeve; Famille: BS_28_SF_LE_IPE; Type: IPE100; Durée de garantie (mois): 0; Périodicité de contrôle (mois): 0; Référence FT**: PLA_015
Pset_XX_Poutres - Résistance au feu: RF60
Name (BS_28_SF_LE_IPE:IPE100:...)
1784736
1784941
1785070
1785072
1785127
1785129
1785147
1785149

# IfcBeam: IPE120 (4)
In: ETAGE -1
Classification: 28 (https://www.csiresources.org/standards/uniformat); Material: BS_28_Métal
Pset_XX_AsBuilt - Catégorie: Ossature; Classification BBsfB: 28; Numéro d'article du CCTB: 23.11.1; Famille: BS_28_SF_LE_IPE; Type: IPE120; Durée de garantie (mois): 0; Périodicité de contrôle (mois): 0
Pset_XX_Poutres - Résistance au feu: RF60
Name (BS_28_SF_LE_IPE:IPE120:...)
1977812
1979261
1979417
1979671

# IfcBeam: IPE220 (4)
In: ETAGE 00 (0)
Classification: 28 (https://www.csiresources.org/standards/uniformat); Material: BS_28_Métal
Pset_XX_AsBuilt - Catégorie: Ossature; Classification BBsfB: 28; Numéro d'article du CCTB: 23.11.1; Famille: BS_28_SF_LE_IPE; Type: IPE220
Name (BS_28_SF_LE_IPE:IPE220:...)
3682893
3682930
3683006
3683008

# IfcBeam: IPE330 (7)
In: ETAGE 10 (1)
Classification: 28. OSSATURE (https://www.csiresources.org/standards/uniformat); Material: BS_28_Métal
Pset_XX_AsBuilt - Catégorie: Ossature; Classification BBsfB: 28.; Numéro d'article du CCTB: 23.11.1; Fabricant: RS Contruction; Fournisseur/Installateur: De Graeve; Famille: BS_28_SF_LE_IPE; Type: IPE330; Durée de garantie (mois): 0; Périodicité de contrôle (mois): 0; Référence FT**: PLA_015
Pset_XX_Poutres - Résistance au feu: RF60
Name (BS_28_SF_LE_IPE:IPE330:...)
1295857
1296301
1298009
1299168
1299181
1299194
1784659

# IfcBeam: K50*80*2 (186)
Description: K50*80*2; Group: Groupe de modèles:IFC ERGON 14122021 (membre exclu):2154686
Pset_XX_AsBuilt - Catégorie: Ossature; Famille: Forme directe; Type: K50*80*2; Durée de garantie (mois): 0; Périodicité de contrôle (mois): 0
Pset_XX_Poutres - Résistance au feu: RF60
Name | In | Identifiant
18 x PS9 | ETAGE 00 (0) | 35
10 x PS9 | ETAGE 00 (0) | 24
32 x PS9 | ETAGE 00 (0) | 28
2 x PS9 | ETAGE 00 (0) | 23
24 x PS9 | ETAGE 10 (1) | 156
12 x PS9 | ETAGE 10 (1) | 131
10 x PS9 | ETAGE 10 (1) | 244
10 x PS9 | ETAGE 10 (1) | 128
2 x PS9 | ETAGE 10 (1) | 256
2 x PS9 | ETAGE 10 (1) | 254
2 x PS9 | ETAGE 10 (1) | 133
6 x PS9 | ETAGE 10 (1) | 139
24 x PS9 | ETAGE 10 (1) | 122
22 x PS9 | ETAGE 20 (2) | 116
2 x PS9 | ETAGE 20 (2) | 118
6 x PS9 | ETAGE 20 (2) | 113
2 x PS9 | ETAGE 20 (2) | 120

# IfcBeam: L.P. (6)
In: ETAGE 00 (0)
Classification: 28. OSSATURE (https://www.csiresources.org/standards/uniformat); Material: BS_28_Ossature en béton armé - Eléments coulé sur place
Pset_XX_AsBuilt - Catégorie: Ossature; Classification BBsfB: 28.; Numéro d'article du CCTB: 26.25; Fabricant: De Graeve; Fournisseur/Installateur: De Graeve; Famille: BS_28_SF_LE_Poutre rectangulaire_coulé; Type: L.P.; Durée de garantie (mois): 0; Périodicité de contrôle (mois): 0
Pset_XX_Poutres - Résistance au feu: RF60
Name (BS_28_SF_LE_Poutre rectangulaire_coulé:L.P.:...)
1396800
1397631
1399059
1399778
1825529
1943534

# IfcBeam: L100/100/10 (4)
In: ETAGE 10 (1)
Description: L100/100/10; Group: Groupe de modèles:IFC ERGON 14122021 (membre exclu):2154686
Pset_XX_AsBuilt - Catégorie: Ossature; Famille: Forme directe; Type: L100/100/10; Durée de garantie (mois): 0; Périodicité de contrôle (mois): 0
Pset_XX_Poutres - Résistance au feu: RF60
Name | Identifiant
2 x PS3 | 184
2 x PS3 | 196

# IfcBeam: L120x120x12 (30)
Classification: 28. OSSATURE (https://www.csiresources.org/standards/uniformat); Material: BS_28_Métal
Pset_XX_AsBuilt - Catégorie: Ossature; Classification BBsfB: 28.; Numéro d'article du CCTB: 23.11.1a; Fabricant: RS Contruction; Fournisseur/Installateur: De Graeve; Famille: C_28_104 - Cornière symétrique; Type: L120x120x12; Durée de garantie (mois): 0; Périodicité de contrôle (mois): 0; Référence FT**: PLA_015
Pset_XX_Poutres - Résistance au feu: RF60
Name (C_28_104 - Cornière symétrique:L120x120x12:...) | In
2737837 | ETAGE 10 (1)
2742375 | ETAGE 10 (1)
2742473 | ETAGE 10 (1)
2742529 | ETAGE 10 (1)
2742641 | ETAGE 10 (1)
2742700 | ETAGE 10 (1)
2742913 | ETAGE 10 (1)
2742982 | ETAGE 10 (1)
2743073 | ETAGE 10 (1)
2743151 | ETAGE 10 (1)
2743987 | ETAGE 10 (1)
2744029 | ETAGE 10 (1)
2744086 | ETAGE 10 (1)
2744656 | ETAGE 10 (1)
2749529 | ETAGE 10 (1)
2751230 | ETAGE 10 (1)
2751583 | ETAGE 10 (1)
2751664 | ETAGE 10 (1)
2751760 | ETAGE 10 (1)
2762928 | ETAGE 10 (1)
2763097 | ETAGE 10 (1)
2763282 | ETAGE 20 (2)
2763438 | ETAGE 20 (2)
2768105 | ETAGE 20 (2)
2768107 | ETAGE 20 (2)
2768223 | ETAGE 20 (2)
2768323 | ETAGE 20 (2)
2768412 | ETAGE 20 (2)
2917075 | ETAGE 20 (2)
2918111 | ETAGE 20 (2)

# IfcBeam: L150/100/10 (2)
In: ETAGE 00 (0)
Description: L150/100/10; Material: STEEL/Accessory; Group: Groupe de modèles:IFC ERGON 14122021 (membre exclu):2154686
Pset_XX_AsBuilt - Catégorie: Ossature; Famille: Forme directe; Type: L150/100/10; Identifiant: 59; Durée de garantie (mois): 0; Périodicité de contrôle (mois): 0
Pset_XX_Poutres - Résistance au feu: RF60

# IfcBeam: L150/100/10 2 (2)
In: ETAGE 00 (0)
Description: L150/100/10; Material: STEEL/Accessory; Group: Groupe de modèles:IFC ERGON 14122021 (membre exclu):2154686
Pset_XX_AsBuilt - Catégorie: Ossature; Famille: Forme directe; Type: L150/100/10; Identifiant: 59; Durée de garantie (mois): 0; Périodicité de contrôle (mois): 0
Pset_XX_Poutres - Résistance au feu: RF60

# IfcBeam: L200/100/10, PS3
In: ETAGE 00 (0)
Description: L200/100/10; Material: STEEL/Accessory; Group: Groupe de modèles:IFC ERGON 14122021 (membre exclu):2154686
Pset_XX_AsBuilt - Catégorie: Ossature; Famille: Forme directe; Type: L200/100/10; Identifiant: 61; Durée de garantie (mois): 0; Périodicité de contrôle (mois): 0
Pset_XX_Poutres - Résistance au feu: RF60

# IfcBeam: L200/100/10 2, PS3
In: ETAGE 00 (0)
Description: L200/100/10; Material: STEEL/Accessory; Group: Groupe de modèles:IFC ERGON 14122021 (membre exclu):2154686
Pset_XX_AsBuilt - Catégorie: Ossature; Famille: Forme directe; Type: L200/100/10; Identifiant: 61; Durée de garantie (mois): 0; Périodicité de contrôle (mois): 0
Pset_XX_Poutres - Résistance au feu: RF60

# IfcBeam: L200x100x10 (4)
In: ETAGE -1
Classification: 28. OSSATURE (https://www.csiresources.org/standards/uniformat); Material: BS_28_Métal
Pset_XX_AsBuilt - Catégorie: Ossature; Classification BBsfB: 28.; Numéro d'article du CCTB: 23.11.1a.12; Fabricant: Phoenix metalworks; Fournisseur/Installateur: Phoenix metalworks; Famille: BS_28_SF_LE_Cornière à ailes inégales; Type: L200x100x10; Durée de garantie (mois): 0; Périodicité de contrôle (mois): 0
Pset_XX_Poutres - Résistance au feu: RF60
Name (BS_28_SF_LE_Cornière à ailes inégales:L200x100x10:...)
1952930
1953076
1953255
2033600

# IfcBeam: L50x5 (16)
In: ETAGE -1
Classification: 28. OSSATURE (https://www.csiresources.org/standards/uniformat); Material: BS_28_Métal
Pset_XX_AsBuilt - Catégorie: Ossature; Classification BBsfB: 28.; Numéro d'article du CCTB: 23.11.1a.09; Famille: BS_28_SF_LE_Cornière à ailes égales; Type: L50x5; Durée de garantie (mois): 0; Périodicité de contrôle (mois): 0
Pset_XX_Poutres - Résistance au feu: RF60
Name (BS_28_SF_LE_Cornière à ailes égales:L50x5:...)
1977269
1977422
1977590
1977935
1978023
1978128
1978187
1978299
1978408
1978580
1978645
1979042
1996418
1997920
1997985
1998049

# IfcBeam: L60x4 (6)
In: ETAGE 10 (1)
Classification: 28. OSSATURE (https://www.csiresources.org/standards/uniformat); Material: BS_28_Métal
Pset_XX_AsBuilt - Catégorie: Ossature; Classification BBsfB: 28.; Numéro d'article du CCTB: 23.11.1a.10; Fabricant: RS Contruction; Fournisseur/Installateur: De Graeve; Famille: BS_28_SF_LE_Cornière à ailes égales; Type: L60x4; Durée de garantie (mois): 0; Périodicité de contrôle (mois): 0; Référence FT**: PLA_015
Pset_XX_Poutres - Résistance au feu: RF60
Name (BS_28_SF_LE_Cornière à ailes égales:L60x4:...)
1786672
1786726
1786883
1787303
1787521
2676332

# IfcBeam: L80x8 (12)
Classification: 28. OSSATURE (https://www.csiresources.org/standards/uniformat); Material: BS_28_Métal
Pset_XX_AsBuilt - Catégorie: Ossature; Classification BBsfB: 28.; Numéro d'article du CCTB: 23.11.1a.11; Fabricant: RS Contruction; Fournisseur/Installateur: De Graeve; Famille: BS_28_SF_LE_Cornière à ailes égales; Type: L80x8; Durée de garantie (mois): 0; Périodicité de contrôle (mois): 0; Référence FT**: PLA_015
Pset_XX_Poutres - Résistance au feu: RF60
Name (BS_28_SF_LE_Cornière à ailes égales:L80x8:...) | In
1315745 | ETAGE 10 (1)
1421327 | ETAGE 10 (1)
1766494 | ETAGE 10 (1)
1767077 | ETAGE 10 (1)
1400006 | ETAGE 20 (2)
1401163 | ETAGE 20 (2)
1403211 | ETAGE 20 (2)
1403213 | ETAGE 20 (2)
1403228 | ETAGE 20 (2)
1403230 | ETAGE 20 (2)
2664624 | ETAGE 20 (2)
2664794 | ETAGE 20 (2)

# IfcBeam: O160*3.2 (72)
In: ETAGE 20 (2)
Description: O160*3.2; Material: STEEL/Accessory_PVC; Group: Groupe de modèles:IFC ERGON 14122021 (membre exclu):2154686
Pset_XX_AsBuilt - Catégorie: Ossature; Famille: Forme directe; Type: O160*3.2; Identifiant: 295; Durée de garantie (mois): 0; Périodicité de contrôle (mois): 0
Pset_XX_Poutres - Résistance au feu: RF60

# IfcBeam: O56*3 (80)
Description: O56*3; Material: STEEL/Accessory_PVC; Group: Groupe de modèles:IFC ERGON 14122021 (membre exclu):2154686
Pset_XX_AsBuilt - Catégorie: Ossature; Famille: Forme directe; Type: O56*3; Identifiant: 214; Durée de garantie (mois): 0; Périodicité de contrôle (mois): 0
Pset_XX_Poutres - Résistance au feu: RF60
Name | In
39 x PS13 | ETAGE 00 (0)
41 x PS13 | ETAGE 10 (1)

# IfcBeam: SHS100x6, SHS (EN 10219-2):SHS100x6:2741738
In: ETAGE 10 (1)
Classification: 28. OSSATURE (https://www.csiresources.org/standards/uniformat); Material: BS_28_Métal
Pset_XX_AsBuilt - Catégorie: Ossature; Classification BBsfB: 28.; Numéro d'article du CCTB: 23.11.1; Fabricant: RS Contruction; Fournisseur/Installateur: De Graeve; Famille: SHS (EN 10219-2); Type: SHS100x6; Durée de garantie (mois): 0; Périodicité de contrôle (mois): 0; Référence FT**: PLA_015
Pset_XX_Poutres - Résistance au feu: RF60

# IfcBuildingElementProxy: 1, 1:708:3640410
In: ETAGE 00 (0)
Material: <Unnamed>; Group: Groupe de modèles:Garde-corps escalier intérieur:3641175
Pset_XX_AsBuilt - Catégorie: Modèles génériques; Famille: 1; Type: 708

# IfcBuildingElementProxy: 101, 51:18385:3640788
In: ETAGE 00 (0)
Material: <Unnamed>; Group: Groupe de modèles:Garde-corps escalier intérieur:3641175
Pset_XX_AsBuilt - Catégorie: Modèles génériques; Famille: 51; Type: 18385

# IfcBuildingElementProxy: 103, 52:18714:3640795
In: ETAGE 00 (0)
Material: <Unnamed>; Group: Groupe de modèles:Garde-corps escalier intérieur:3641175
Pset_XX_AsBuilt - Catégorie: Modèles génériques; Famille: 52; Type: 18714

# IfcBuildingElementProxy: 105, 53:19291:3640802
In: ETAGE 00 (0)
Material: <Unnamed>; Group: Groupe de modèles:Garde-corps escalier intérieur:3641175
Pset_XX_AsBuilt - Catégorie: Modèles génériques; Famille: 53; Type: 19291

# IfcBuildingElementProxy: 107, 54:19872:3640809
In: ETAGE 00 (0)
Material: <Unnamed>; Group: Groupe de modèles:Garde-corps escalier intérieur:3641175
Pset_XX_AsBuilt - Catégorie: Modèles génériques; Famille: 54; Type: 19872

# IfcBuildingElementProxy: 109, 55:20643:3640816
In: ETAGE 00 (0)
Material: <Unnamed>; Group: Groupe de modèles:Garde-corps escalier intérieur:3641175
Pset_XX_AsBuilt - Catégorie: Modèles génériques; Famille: 55; Type: 20643

# IfcBuildingElementProxy: 11, 6:2062:3640473
In: ETAGE 00 (0)
Material: <Unnamed>; Group: Groupe de modèles:Garde-corps escalier intérieur:3641175
Pset_XX_AsBuilt - Catégorie: Modèles génériques; Famille: 6; Type: 2062

# IfcBuildingElementProxy: 111, 56:20991:3640823
In: ETAGE 00 (0)
Material: <Unnamed>; Group: Groupe de modèles:Garde-corps escalier intérieur:3641175
Pset_XX_AsBuilt - Catégorie: Modèles génériques; Famille: 56; Type: 20991

# IfcBuildingElementProxy: 113, 57:21283:3640830
In: ETAGE 00 (0)
Material: <Unnamed>; Group: Groupe de modèles:Garde-corps escalier intérieur:3641175
Pset_XX_AsBuilt - Catégorie: Modèles génériques; Famille: 57; Type: 21283

# IfcBuildingElementProxy: 115, 60:22682:3640851
In: ETAGE 00 (0)
Material: <Unnamed>; Group: Groupe de modèles:Garde-corps escalier intérieur:3641175
Pset_XX_AsBuilt - Catégorie: Modèles génériques; Famille: 60; Type: 22682

# IfcBuildingElementProxy: 117, 61:22734:3640858
In: ETAGE 00 (0)
Material: <Unnamed>; Group: Groupe de modèles:Garde-corps escalier intérieur:3641175
Pset_XX_AsBuilt - Catégorie: Modèles génériques; Famille: 61; Type: 22734

# IfcBuildingElementProxy: 119, 62:23064:3640865
In: ETAGE 00 (0)
Material: <Unnamed>; Group: Groupe de modèles:Garde-corps escalier intérieur:3641175
Pset_XX_AsBuilt - Catégorie: Modèles génériques; Famille: 62; Type: 23064

# IfcBuildingElementProxy: 121, 63:23116:3640872
In: ETAGE 00 (0)
Material: <Unnamed>; Group: Groupe de modèles:Garde-corps escalier intérieur:3641175
Pset_XX_AsBuilt - Catégorie: Modèles génériques; Famille: 63; Type: 23116

# IfcBuildingElementProxy: 123, 64:23738:3640879
In: ETAGE 00 (0)
Material: <Unnamed>; Group: Groupe de modèles:Garde-corps escalier intérieur:3641175
Pset_XX_AsBuilt - Catégorie: Modèles génériques; Famille: 64; Type: 23738

# IfcBuildingElementProxy: 125, 66:24636:3640893
In: ETAGE 00 (0)
Material: <Unnamed>; Group: Groupe de modèles:Garde-corps escalier intérieur:3641175
Pset_XX_AsBuilt - Catégorie: Modèles génériques; Famille: 66; Type: 24636

# IfcBuildingElementProxy: 127, 67:24688:3640900
In: ETAGE 00 (0)
Material: <Unnamed>; Group: Groupe de modèles:Garde-corps escalier intérieur:3641175
Pset_XX_AsBuilt - Catégorie: Modèles génériques; Famille: 67; Type: 24688

# IfcBuildingElementProxy: 129, 68:24962:3640907
In: ETAGE 00 (0)
Material: <Unnamed>; Group: Groupe de modèles:Garde-corps escalier intérieur:3641175
Pset_XX_AsBuilt - Catégorie: Modèles génériques; Famille: 68; Type: 24962

# IfcBuildingElementProxy: 13, 7:2333:3640480
In: ETAGE 00 (0)
Material: <Unnamed>; Group: Groupe de modèles:Garde-corps escalier intérieur:3641175
Pset_XX_AsBuilt - Catégorie: Modèles génériques; Famille: 7; Type: 2333

# IfcBuildingElementProxy: 131, 70:25571:3640921
In: ETAGE 00 (0)
Material: <Unnamed>; Group: Groupe de modèles:Garde-corps escalier intérieur:3641175
Pset_XX_AsBuilt - Catégorie: Modèles génériques; Famille: 70; Type: 25571

# IfcBuildingElementProxy: 133, 71:25901:3640928
In: ETAGE 00 (0)
Material: <Unnamed>; Group: Groupe de modèles:Garde-corps escalier intérieur:3641175
Pset_XX_AsBuilt - Catégorie: Modèles génériques; Famille: 71; Type: 25901

# IfcBuildingElementProxy: 135, 73:26678:3640942
In: ETAGE 00 (0)
Material: <Unnamed>; Group: Groupe de modèles:Garde-corps escalier intérieur:3641175
Pset_XX_AsBuilt - Catégorie: Modèles génériques; Famille: 73; Type: 26678

# IfcBuildingElementProxy: 137, 74:26966:3640949
In: ETAGE 00 (0)
Material: <Unnamed>; Group: Groupe de modèles:Garde-corps escalier intérieur:3641175
Pset_XX_AsBuilt - Catégorie: Modèles génériques; Famille: 74; Type: 26966

# IfcBuildingElementProxy: 139, 75:27403:3640956
In: ETAGE 00 (0)
Material: <Unnamed>; Group: Groupe de modèles:Garde-corps escalier intérieur:3641175
Pset_XX_AsBuilt - Catégorie: Modèles génériques; Famille: 75; Type: 27403

# IfcBuildingElementProxy: 141, 76:27929:3640963
In: ETAGE 00 (0)
Material: <Unnamed>; Group: Groupe de modèles:Garde-corps escalier intérieur:3641175
Pset_XX_AsBuilt - Catégorie: Modèles génériques; Famille: 76; Type: 27929

# IfcBuildingElementProxy: 143, 77:28467:3640970
In: ETAGE 00 (0)
Material: <Unnamed>; Group: Groupe de modèles:Garde-corps escalier intérieur:3641175
Pset_XX_AsBuilt - Catégorie: Modèles génériques; Famille: 77; Type: 28467

# IfcBuildingElementProxy: 145, 78:28881:3640977
In: ETAGE 00 (0)
Material: <Unnamed>; Group: Groupe de modèles:Garde-corps escalier intérieur:3641175
Pset_XX_AsBuilt - Catégorie: Modèles génériques; Famille: 78; Type: 28881

# IfcBuildingElementProxy: 147, 79:29308:3640984
In: ETAGE 00 (0)
Material: <Unnamed>; Group: Groupe de modèles:Garde-corps escalier intérieur:3641175
Pset_XX_AsBuilt - Catégorie: Modèles génériques; Famille: 79; Type: 29308

# IfcBuildingElementProxy: 149, 80:29731:3640991
In: ETAGE 00 (0)
Material: <Unnamed>; Group: Groupe de modèles:Garde-corps escalier intérieur:3641175
Pset_XX_AsBuilt - Catégorie: Modèles génériques; Famille: 80; Type: 29731

# IfcBuildingElementProxy: 15, 8:2784:3640487
In: ETAGE 00 (0)
Material: <Unnamed>; Group: Groupe de modèles:Garde-corps escalier intérieur:3641175
Pset_XX_AsBuilt - Catégorie: Modèles génériques; Famille: 8; Type: 2784

# IfcBuildingElementProxy: 151, 81:30156:3640998
In: ETAGE 00 (0)
Material: <Unnamed>; Group: Groupe de modèles:Garde-corps escalier intérieur:3641175
Pset_XX_AsBuilt - Catégorie: Modèles génériques; Famille: 81; Type: 30156

# IfcBuildingElementProxy: 153, 82:30581:3641005
In: ETAGE 00 (0)
Material: <Unnamed>; Group: Groupe de modèles:Garde-corps escalier intérieur:3641175
Pset_XX_AsBuilt - Catégorie: Modèles génériques; Famille: 82; Type: 30581

# IfcBuildingElementProxy: 155, 83:30985:3641012
In: ETAGE 00 (0)
Material: <Unnamed>; Group: Groupe de modèles:Garde-corps escalier intérieur:3641175
Pset_XX_AsBuilt - Catégorie: Modèles génériques; Famille: 83; Type: 30985

# IfcBuildingElementProxy: 157, 84:31403:3641019
In: ETAGE 00 (0)
Material: <Unnamed>; Group: Groupe de modèles:Garde-corps escalier intérieur:3641175
Pset_XX_AsBuilt - Catégorie: Modèles génériques; Famille: 84; Type: 31403

# IfcBuildingElementProxy: 159, 85:31802:3641026
In: ETAGE 00 (0)
Material: <Unnamed>; Group: Groupe de modèles:Garde-corps escalier intérieur:3641175
Pset_XX_AsBuilt - Catégorie: Modèles génériques; Famille: 85; Type: 31802

# IfcBuildingElementProxy: 161, 86:31854:3641033
In: ETAGE 00 (0)
Material: <Unnamed>; Group: Groupe de modèles:Garde-corps escalier intérieur:3641175
Pset_XX_AsBuilt - Catégorie: Modèles génériques; Famille: 86; Type: 31854

# IfcBuildingElementProxy: 163, 87:31888:3641040
In: ETAGE 00 (0)
Material: <Unnamed>; Group: Groupe de modèles:Garde-corps escalier intérieur:3641175
Pset_XX_AsBuilt - Catégorie: Modèles génériques; Famille: 87; Type: 31888

# IfcBuildingElementProxy: 165, 88:31924:3641047
In: ETAGE 00 (0)
Material: <Unnamed>; Group: Groupe de modèles:Garde-corps escalier intérieur:3641175
Pset_XX_AsBuilt - Catégorie: Modèles génériques; Famille: 88; Type: 31924

# IfcBuildingElementProxy: 167, 89:32303:3641054
In: ETAGE 00 (0)
Material: <Unnamed>; Group: Groupe de modèles:Garde-corps escalier intérieur:3641175
Pset_XX_AsBuilt - Catégorie: Modèles génériques; Famille: 89; Type: 32303

# IfcBuildingElementProxy: 169, 90:32357:3641061
In: ETAGE 00 (0)
Material: <Unnamed>; Group: Groupe de modèles:Garde-corps escalier intérieur:3641175
Pset_XX_AsBuilt - Catégorie: Modèles génériques; Famille: 90; Type: 32357

# IfcBuildingElementProxy: 17, 9:3076:3640494
In: ETAGE 00 (0)
Material: <Unnamed>; Group: Groupe de modèles:Garde-corps escalier intérieur:3641175
Pset_XX_AsBuilt - Catégorie: Modèles génériques; Famille: 9; Type: 3076

# IfcBuildingElementProxy: 171, 91:32393:3641068
In: ETAGE 00 (0)
Material: <Unnamed>; Group: Groupe de modèles:Garde-corps escalier intérieur:3641175
Pset_XX_AsBuilt - Catégorie: Modèles génériques; Famille: 91; Type: 32393

# IfcBuildingElementProxy: 173, 96:35491:3641103
In: ETAGE 00 (0)
Material: <Unnamed>; Group: Groupe de modèles:Garde-corps escalier intérieur:3641175
Pset_XX_AsBuilt - Catégorie: Modèles génériques; Famille: 96; Type: 35491

# IfcBuildingElementProxy: 175, 97:35853:3641110
In: ETAGE 00 (0)
Material: <Unnamed>; Group: Groupe de modèles:Garde-corps escalier intérieur:3641175
Pset_XX_AsBuilt - Catégorie: Modèles génériques; Famille: 97; Type: 35853

# IfcBuildingElementProxy: 177, 98:35913:3641117
In: ETAGE 00 (0)
Material: <Unnamed>; Group: Groupe de modèles:Garde-corps escalier intérieur:3641175
Pset_XX_AsBuilt - Catégorie: Modèles génériques; Famille: 98; Type: 35913

# IfcBuildingElementProxy: 179, 99:36429:3641124
In: ETAGE 00 (0)
Material: <Unnamed>; Group: Groupe de modèles:Garde-corps escalier intérieur:3641175
Pset_XX_AsBuilt - Catégorie: Modèles génériques; Famille: 99; Type: 36429

# IfcBuildingElementProxy: 181, 100:37131:3641131
In: ETAGE 00 (0)
Material: <Unnamed>; Group: Groupe de modèles:Garde-corps escalier intérieur:3641175
Pset_XX_AsBuilt - Catégorie: Modèles génériques; Famille: 100; Type: 37131

# IfcBuildingElementProxy: 183, 101:37639:3641138
In: ETAGE 00 (0)
Material: <Unnamed>; Group: Groupe de modèles:Garde-corps escalier intérieur:3641175
Pset_XX_AsBuilt - Catégorie: Modèles génériques; Famille: 101; Type: 37639

# IfcBuildingElementProxy: 185, 102:37691:3641145
In: ETAGE 00 (0)
Material: <Unnamed>; Group: Groupe de modèles:Garde-corps escalier intérieur:3641175
Pset_XX_AsBuilt - Catégorie: Modèles génériques; Famille: 102; Type: 37691

# IfcBuildingElementProxy: 187, 103:38028:3641152
In: ETAGE 00 (0)
Material: <Unnamed>; Group: Groupe de modèles:Garde-corps escalier intérieur:3641175
Pset_XX_AsBuilt - Catégorie: Modèles génériques; Famille: 103; Type: 38028

# IfcBuildingElementProxy: 189, 104:38816:3641159
In: ETAGE 00 (0)
Material: <Unnamed>; Group: Groupe de modèles:Garde-corps escalier intérieur:3641175
Pset_XX_AsBuilt - Catégorie: Modèles génériques; Famille: 104; Type: 38816

# IfcBuildingElementProxy: 19, 10:3443:3640501
In: ETAGE 00 (0)
Material: <Unnamed>; Group: Groupe de modèles:Garde-corps escalier intérieur:3641175
Pset_XX_AsBuilt - Catégorie: Modèles génériques; Famille: 10; Type: 3443

# IfcBuildingElementProxy: 191, 105:39211:3641166
In: ETAGE 00 (0)
Material: <Unnamed>; Group: Groupe de modèles:Garde-corps escalier intérieur:3641175
Pset_XX_AsBuilt - Catégorie: Modèles génériques; Famille: 105; Type: 39211

# IfcBuildingElementProxy: 193, 106:39573:3641173
In: ETAGE 00 (0)
Material: <Unnamed>; Group: Groupe de modèles:Garde-corps escalier intérieur:3641175
Pset_XX_AsBuilt - Catégorie: Modèles génériques; Famille: 106; Type: 39573

# IfcBuildingElementProxy: 195, 58:21833:3640837
In: ETAGE 10 (1)
Material: <Unnamed>; Group: Groupe de modèles:Garde-corps escalier intérieur:3641175
Pset_XX_AsBuilt - Catégorie: Modèles génériques; Famille: 58; Type: 21833

# IfcBuildingElementProxy: 197, 59:22390:3640844
In: ETAGE 10 (1)
Material: <Unnamed>; Group: Groupe de modèles:Garde-corps escalier intérieur:3641175
Pset_XX_AsBuilt - Catégorie: Modèles génériques; Famille: 59; Type: 22390

# IfcBuildingElementProxy: 199, 65:24288:3640886
In: ETAGE 10 (1)
Material: <Unnamed>; Group: Groupe de modèles:Garde-corps escalier intérieur:3641175
Pset_XX_AsBuilt - Catégorie: Modèles génériques; Famille: 65; Type: 24288

# IfcBuildingElementProxy: 201, 69:25519:3640914
In: ETAGE 10 (1)
Material: <Unnamed>; Group: Groupe de modèles:Garde-corps escalier intérieur:3641175
Pset_XX_AsBuilt - Catégorie: Modèles génériques; Famille: 69; Type: 25519

# IfcBuildingElementProxy: 203, 72:26626:3640935
In: ETAGE 10 (1)
Material: <Unnamed>; Group: Groupe de modèles:Garde-corps escalier intérieur:3641175
Pset_XX_AsBuilt - Catégorie: Modèles génériques; Famille: 72; Type: 26626

# IfcBuildingElementProxy: 205, 92:33109:3641075
In: ETAGE 10 (1)
Material: <Unnamed>; Group: Groupe de modèles:Garde-corps escalier intérieur:3641175
Pset_XX_AsBuilt - Catégorie: Modèles génériques; Famille: 92; Type: 33109

# IfcBuildingElementProxy: 207, 93:33715:3641082
In: ETAGE 10 (1)
Material: <Unnamed>; Group: Groupe de modèles:Garde-corps escalier intérieur:3641175
Pset_XX_AsBuilt - Catégorie: Modèles génériques; Famille: 93; Type: 33715

# IfcBuildingElementProxy: 209, 94:34482:3641089
In: ETAGE 10 (1)
Material: <Unnamed>; Group: Groupe de modèles:Garde-corps escalier intérieur:3641175
Pset_XX_AsBuilt - Catégorie: Modèles génériques; Famille: 94; Type: 34482

# IfcBuildingElementProxy: 21, 11:3812:3640508
In: ETAGE 00 (0)
Material: <Unnamed>; Group: Groupe de modèles:Garde-corps escalier intérieur:3641175
Pset_XX_AsBuilt - Catégorie: Modèles génériques; Famille: 11; Type: 3812

# IfcBuildingElementProxy: 211, 95:35094:3641096
In: ETAGE 10 (1)
Material: <Unnamed>; Group: Groupe de modèles:Garde-corps escalier intérieur:3641175
Pset_XX_AsBuilt - Catégorie: Modèles génériques; Famille: 95; Type: 35094

# IfcBuildingElementProxy: 23, 12:4188:3640515
In: ETAGE 00 (0)
Material: <Unnamed>; Group: Groupe de modèles:Garde-corps escalier intérieur:3641175
Pset_XX_AsBuilt - Catégorie: Modèles génériques; Famille: 12; Type: 4188

# IfcBuildingElementProxy: 25, 13:4557:3640522
In: ETAGE 00 (0)
Material: <Unnamed>; Group: Groupe de modèles:Garde-corps escalier intérieur:3641175
Pset_XX_AsBuilt - Catégorie: Modèles génériques; Famille: 13; Type: 4557

# IfcBuildingElementProxy: 27, 14:4938:3640529
In: ETAGE 00 (0)
Material: <Unnamed>; Group: Groupe de modèles:Garde-corps escalier intérieur:3641175
Pset_XX_AsBuilt - Catégorie: Modèles génériques; Famille: 14; Type: 4938

# IfcBuildingElementProxy: 29, 15:4990:3640536
In: ETAGE 00 (0)
Material: <Unnamed>; Group: Groupe de modèles:Garde-corps escalier intérieur:3641175
Pset_XX_AsBuilt - Catégorie: Modèles génériques; Famille: 15; Type: 4990

# IfcBuildingElementProxy: 3, 2:774:3640424
In: ETAGE 00 (0)
Material: <Unnamed>; Group: Groupe de modèles:Garde-corps escalier intérieur:3641175
Pset_XX_AsBuilt - Catégorie: Modèles génériques; Famille: 2; Type: 774

# IfcBuildingElementProxy: 31, 16:5236:3640543
In: ETAGE 00 (0)
Material: <Unnamed>; Group: Groupe de modèles:Garde-corps escalier intérieur:3641175
Pset_XX_AsBuilt - Catégorie: Modèles génériques; Famille: 16; Type: 5236

# IfcBuildingElementProxy: 33, 17:5593:3640550
In: ETAGE 00 (0)
Material: <Unnamed>; Group: Groupe de modèles:Garde-corps escalier intérieur:3641175
Pset_XX_AsBuilt - Catégorie: Modèles génériques; Famille: 17; Type: 5593

# IfcBuildingElementProxy: 35, 18:5941:3640557
In: ETAGE 00 (0)
Material: <Unnamed>; Group: Groupe de modèles:Garde-corps escalier intérieur:3641175
Pset_XX_AsBuilt - Catégorie: Modèles génériques; Famille: 18; Type: 5941

# IfcBuildingElementProxy: 37, 19:5993:3640564
In: ETAGE 00 (0)
Material: <Unnamed>; Group: Groupe de modèles:Garde-corps escalier intérieur:3641175
Pset_XX_AsBuilt - Catégorie: Modèles génériques; Famille: 19; Type: 5993

# IfcBuildingElementProxy: 39, 20:6516:3640571
In: ETAGE 00 (0)
Material: <Unnamed>; Group: Groupe de modèles:Garde-corps escalier intérieur:3641175
Pset_XX_AsBuilt - Catégorie: Modèles génériques; Famille: 20; Type: 6516

# IfcBuildingElementProxy: 41, 21:6932:3640578
In: ETAGE 00 (0)
Material: <Unnamed>; Group: Groupe de modèles:Garde-corps escalier intérieur:3641175
Pset_XX_AsBuilt - Catégorie: Modèles génériques; Famille: 21; Type: 6932

# IfcBuildingElementProxy: 43, 22:7336:3640585
In: ETAGE 00 (0)
Material: <Unnamed>; Group: Groupe de modèles:Garde-corps escalier intérieur:3641175
Pset_XX_AsBuilt - Catégorie: Modèles génériques; Famille: 22; Type: 7336

# IfcBuildingElementProxy: 45, 23:7860:3640592
In: ETAGE 00 (0)
Material: <Unnamed>; Group: Groupe de modèles:Garde-corps escalier intérieur:3641175
Pset_XX_AsBuilt - Catégorie: Modèles génériques; Famille: 23; Type: 7860

# IfcBuildingElementProxy: 47, 24:8250:3640599
In: ETAGE 00 (0)
Material: <Unnamed>; Group: Groupe de modèles:Garde-corps escalier intérieur:3641175
Pset_XX_AsBuilt - Catégorie: Modèles génériques; Famille: 24; Type: 8250

# IfcBuildingElementProxy: 49, 25:8304:3640606
In: ETAGE 00 (0)
Material: <Unnamed>; Group: Groupe de modèles:Garde-corps escalier intérieur:3641175
Pset_XX_AsBuilt - Catégorie: Modèles génériques; Famille: 25; Type: 8304

# IfcBuildingElementProxy: 5, 3:924:3640438
In: ETAGE 00 (0)
Material: <Unnamed>; Group: Groupe de modèles:Garde-corps escalier intérieur:3641175
Pset_XX_AsBuilt - Catégorie: Modèles génériques; Famille: 3; Type: 924

# IfcBuildingElementProxy: 51, 26:8578:3640613
In: ETAGE 00 (0)
Material: <Unnamed>; Group: Groupe de modèles:Garde-corps escalier intérieur:3641175
Pset_XX_AsBuilt - Catégorie: Modèles génériques; Famille: 26; Type: 8578

# IfcBuildingElementProxy: 53, 27:9202:3640620
In: ETAGE 00 (0)
Material: <Unnamed>; Group: Groupe de modèles:Garde-corps escalier intérieur:3641175
Pset_XX_AsBuilt - Catégorie: Modèles génériques; Famille: 27; Type: 9202

# IfcBuildingElementProxy: 55, 28:9258:3640627
In: ETAGE 00 (0)
Material: <Unnamed>; Group: Groupe de modèles:Garde-corps escalier intérieur:3641175
Pset_XX_AsBuilt - Catégorie: Modèles génériques; Famille: 28; Type: 9258

# IfcBuildingElementProxy: 57, 29:9689:3640634
In: ETAGE 00 (0)
Material: <Unnamed>; Group: Groupe de modèles:Garde-corps escalier intérieur:3641175
Pset_XX_AsBuilt - Catégorie: Modèles génériques; Famille: 29; Type: 9689

# IfcBuildingElementProxy: 59, 30:10067:3640641
In: ETAGE 00 (0)
Material: <Unnamed>; Group: Groupe de modèles:Garde-corps escalier intérieur:3641175
Pset_XX_AsBuilt - Catégorie: Modèles génériques; Famille: 30; Type: 10067

# IfcBuildingElementProxy: 61, 31:10481:3640648
In: ETAGE 00 (0)
Material: <Unnamed>; Group: Groupe de modèles:Garde-corps escalier intérieur:3641175
Pset_XX_AsBuilt - Catégorie: Modèles génériques; Famille: 31; Type: 10481

# IfcBuildingElementProxy: 63, 32:10533:3640655
In: ETAGE 00 (0)
Material: <Unnamed>; Group: Groupe de modèles:Garde-corps escalier intérieur:3641175
Pset_XX_AsBuilt - Catégorie: Modèles génériques; Famille: 32; Type: 10533

# IfcBuildingElementProxy: 65, 33:10945:3640662
In: ETAGE 00 (0)
Material: <Unnamed>; Group: Groupe de modèles:Garde-corps escalier intérieur:3641175
Pset_XX_AsBuilt - Catégorie: Modèles génériques; Famille: 33; Type: 10945

# IfcBuildingElementProxy: 67, 34:11481:3640669
In: ETAGE 00 (0)
Material: <Unnamed>; Group: Groupe de modèles:Garde-corps escalier intérieur:3641175
Pset_XX_AsBuilt - Catégorie: Modèles génériques; Famille: 34; Type: 11481

# IfcBuildingElementProxy: 69, 35:12058:3640676
In: ETAGE 00 (0)
Material: <Unnamed>; Group: Groupe de modèles:Garde-corps escalier intérieur:3641175
Pset_XX_AsBuilt - Catégorie: Modèles génériques; Famille: 35; Type: 12058

# IfcBuildingElementProxy: 7, 4:990:3640452
In: ETAGE 00 (0)
Material: <Unnamed>; Group: Groupe de modèles:Garde-corps escalier intérieur:3641175
Pset_XX_AsBuilt - Catégorie: Modèles génériques; Famille: 4; Type: 990

# IfcBuildingElementProxy: 71, 36:12112:3640683
In: ETAGE 00 (0)
Material: <Unnamed>; Group: Groupe de modèles:Garde-corps escalier intérieur:3641175
Pset_XX_AsBuilt - Catégorie: Modèles génériques; Famille: 36; Type: 12112

# IfcBuildingElementProxy: 73, 37:12512:3640690
In: ETAGE 00 (0)
Material: <Unnamed>; Group: Groupe de modèles:Garde-corps escalier intérieur:3641175
Pset_XX_AsBuilt - Catégorie: Modèles génériques; Famille: 37; Type: 12512

# IfcBuildingElementProxy: 75, 38:12804:3640697
In: ETAGE 00 (0)
Material: <Unnamed>; Group: Groupe de modèles:Garde-corps escalier intérieur:3641175
Pset_XX_AsBuilt - Catégorie: Modèles génériques; Famille: 38; Type: 12804

# IfcBuildingElementProxy: 77, 39:13173:3640704
In: ETAGE 00 (0)
Material: <Unnamed>; Group: Groupe de modèles:Garde-corps escalier intérieur:3641175
Pset_XX_AsBuilt - Catégorie: Modèles génériques; Famille: 39; Type: 13173

# IfcBuildingElementProxy: 79, 40:13556:3640711
In: ETAGE 00 (0)
Material: <Unnamed>; Group: Groupe de modèles:Garde-corps escalier intérieur:3641175
Pset_XX_AsBuilt - Catégorie: Modèles génériques; Famille: 40; Type: 13556

# IfcBuildingElementProxy: 81, 41:13925:3640718
In: ETAGE 00 (0)
Material: <Unnamed>; Group: Groupe de modèles:Garde-corps escalier intérieur:3641175
Pset_XX_AsBuilt - Catégorie: Modèles génériques; Famille: 41; Type: 13925

# IfcBuildingElementProxy: 83, 42:14306:3640725
In: ETAGE 00 (0)
Material: <Unnamed>; Group: Groupe de modèles:Garde-corps escalier intérieur:3641175
Pset_XX_AsBuilt - Catégorie: Modèles génériques; Famille: 42; Type: 14306

# IfcBuildingElementProxy: 85, 43:14358:3640732
In: ETAGE 00 (0)
Material: <Unnamed>; Group: Groupe de modèles:Garde-corps escalier intérieur:3641175
Pset_XX_AsBuilt - Catégorie: Modèles génériques; Famille: 43; Type: 14358

# IfcBuildingElementProxy: 87, 44:14890:3640739
In: ETAGE 00 (0)
Material: <Unnamed>; Group: Groupe de modèles:Garde-corps escalier intérieur:3641175
Pset_XX_AsBuilt - Catégorie: Modèles génériques; Famille: 44; Type: 14890

# IfcBuildingElementProxy: 89, 45:15440:3640746
In: ETAGE 00 (0)
Material: <Unnamed>; Group: Groupe de modèles:Garde-corps escalier intérieur:3641175
Pset_XX_AsBuilt - Catégorie: Modèles génériques; Famille: 45; Type: 15440

# IfcBuildingElementProxy: 9, 5:1758:3640466
In: ETAGE 00 (0)
Material: <Unnamed>; Group: Groupe de modèles:Garde-corps escalier intérieur:3641175
Pset_XX_AsBuilt - Catégorie: Modèles génériques; Famille: 5; Type: 1758

# IfcBuildingElementProxy: 91, 46:15990:3640753
In: ETAGE 00 (0)
Material: <Unnamed>; Group: Groupe de modèles:Garde-corps escalier intérieur:3641175
Pset_XX_AsBuilt - Catégorie: Modèles génériques; Famille: 46; Type: 15990

# IfcBuildingElementProxy: 93, 47:16540:3640760
In: ETAGE 00 (0)
Material: <Unnamed>; Group: Groupe de modèles:Garde-corps escalier intérieur:3641175
Pset_XX_AsBuilt - Catégorie: Modèles génériques; Famille: 47; Type: 16540

# IfcBuildingElementProxy: 95, 48:16888:3640767
In: ETAGE 00 (0)
Material: <Unnamed>; Group: Groupe de modèles:Garde-corps escalier intérieur:3641175
Pset_XX_AsBuilt - Catégorie: Modèles génériques; Famille: 48; Type: 16888

# IfcBuildingElementProxy: 97, 49:17217:3640774
In: ETAGE 00 (0)
Material: <Unnamed>; Group: Groupe de modèles:Garde-corps escalier intérieur:3641175
Pset_XX_AsBuilt - Catégorie: Modèles génériques; Famille: 49; Type: 17217

# IfcBuildingElementProxy: 99, 50:18056:3640781
In: ETAGE 00 (0)
Material: <Unnamed>; Group: Groupe de modèles:Garde-corps escalier intérieur:3641175
Pset_XX_AsBuilt - Catégorie: Modèles génériques; Famille: 50; Type: 18056

# IfcBuildingElementProxy: ASSA ABLOY BE_Architectural and Accessory Hardware_TONIC LINE_Litto ASSA ABLOY_TL1102LSS 3D_4XTL1102LSS, ASSA ABLOY BE_Architectural and Accessory Hardware_TONIC LINE_Litto ASSA ABLOY_TL1102LSS 3D:4XTL1102LSS:3514577
In: ETAGE 00 (0)
Pset_XX_AsBuilt - Catégorie: Equipement spécialisé; Fabricant: ASSA ABLOY; Famille: ASSA ABLOY BE_Architectural and Accessory Hardware_TONIC LINE_Litto ASSA ABLOY_TL1102LSS 3D; Type: 4XTL1102LSS; Niveau: ETAGE 00 (0); Durée de garantie (mois): 0; Périodicité de contrôle (mois): 0; Modèle: ASSA ABLOY BE_Architectural and Accessory Hardware_TONIC LINE_Litto ASSA ABLOY_TL1102LSS 3D

# IfcBuildingElementProxy: ASSA ABLOY BE_Door Closers_Cam-Motion®_ASSA ABLOY_DC500 3D_DC500, ASSA ABLOY BE_Door Closers_Cam-Motion®_ASSA ABLOY_DC500 3D:DC500:3514576
In: ETAGE 00 (0)
Pset_XX_AsBuilt - Catégorie: Equipement spécialisé; Fabricant: ASSA ABLOY; Famille: ASSA ABLOY BE_Door Closers_Cam-Motion®_ASSA ABLOY_DC500 3D; Type: DC500; Niveau: ETAGE 00 (0); Durée de garantie (mois): 0; Périodicité de contrôle (mois): 0; Modèle: ASSA ABLOY BE_Door Closers_Cam-Motion®_ASSA ABLOY_DC500 3D

# IfcBuildingElementProxy: ASSA ABLOY BE_Panic and Exit Devices_PUSH_Vachette ASSA ABLOY 3D_VLPE6840X, ASSA ABLOY BE_Panic and Exit Devices_PUSH_Vachette ASSA ABLOY 3D:VLPE6840X:3514575
In: ETAGE 00 (0)
Pset_XX_AsBuilt - Catégorie: Equipement spécialisé; Fabricant: ASSA ABLOY; Famille: ASSA ABLOY BE_Panic and Exit Devices_PUSH_Vachette ASSA ABLOY 3D; Type: VLPE6840X; Niveau: ETAGE 00 (0); Durée de garantie (mois): 0; Périodicité de contrôle (mois): 0; Modèle: ASSA ABLOY BE_Panic and Exit Devices_PUSH_Vachette ASSA ABLOY 3D

# IfcBuildingElementProxy: Console métal10_Console métal, Console métal10:Console métal:2106674
In: ETAGE 10 (1)
Material: BS_28_Métal
Pset_XX_AsBuilt - Catégorie: Ossature; Classification BBsfB: 28.; Numéro d'article du CCTB: 23.42.1a; Fabricant: RS Contruction; Fournisseur/Installateur: De Graeve; Famille: Console métal10; Type: Console métal; Durée de garantie (mois): 0; Périodicité de contrôle (mois): 0; Référence FT**: PLA_015
Pset_XX_Poutres - Résistance au feu: RF60

# IfcBuildingElementProxy: Console métal11_Console métal, Console métal11:Console métal:2106686
In: ETAGE 10 (1)
Material: BS_28_Métal
Pset_XX_AsBuilt - Catégorie: Ossature; Classification BBsfB: 28.; Numéro d'article du CCTB: 23.42.1a; Fabricant: RS Contruction; Fournisseur/Installateur: De Graeve; Famille: Console métal11; Type: Console métal; Durée de garantie (mois): 0; Périodicité de contrôle (mois): 0; Référence FT**: PLA_015
Pset_XX_Poutres - Résistance au feu: RF60

# IfcBuildingElementProxy: Console métal33_Console métal, Console métal33:Console métal:2106710
In: ETAGE 10 (1)
Material: BS_28_Console métal
Pset_XX_AsBuilt - Catégorie: Ossature; Classification BBsfB: 28.; Numéro d'article du CCTB: 23.42.1a; Fabricant: RS Contruction; Fournisseur/Installateur: De Graeve; Famille: Console métal33; Type: Console métal; Durée de garantie (mois): 0; Périodicité de contrôle (mois): 0; Référence FT**: PLA_015
Pset_XX_Poutres - Résistance au feu: RF60

# IfcBuildingElementProxy: Console métal34_Console métal, Console métal34:Console métal:2106722
In: ETAGE 10 (1)
Material: BS_28_Métal
Pset_XX_AsBuilt - Catégorie: Ossature; Classification BBsfB: 28.; Numéro d'article du CCTB: 23.42.1a; Fabricant: RS Contruction; Fournisseur/Installateur: De Graeve; Famille: Console métal34; Type: Console métal; Durée de garantie (mois): 0; Périodicité de contrôle (mois): 0; Référence FT**: PLA_015
Pset_XX_Poutres - Résistance au feu: RF60

# IfcBuildingElementProxy: Console métal38_Console métal, Console métal38:Console métal:2106698
In: ETAGE 10 (1)
Material: BS_28_Métal
Pset_XX_AsBuilt - Catégorie: Ossature; Classification BBsfB: 28.; Numéro d'article du CCTB: 23.42.1a; Fabricant: RS Contruction; Fournisseur/Installateur: De Graeve; Famille: Console métal38; Type: Console métal; Durée de garantie (mois): 0; Périodicité de contrôle (mois): 0; Référence FT**: PLA_015
Pset_XX_Poutres - Résistance au feu: RF60

# IfcBuildingElementProxy: Console métal3_Console métal, Console métal3:Console métal:2106501
In: ETAGE 00 (0)
Material: BS_28_Console métal
Pset_XX_AsBuilt - Catégorie: Ossature; Classification BBsfB: 28.; Numéro d'article du CCTB: 23.42.1a; Fabricant: RS Contruction; Fournisseur/Installateur: De Graeve; Famille: Console métal3; Type: Console métal; Durée de garantie (mois): 0; Périodicité de contrôle (mois): 0; Référence FT**: PLA_015
Pset_XX_Poutres - Résistance au feu: RF60

# IfcBuildingElementProxy: Console métal4_Console métal, Console métal4:Console métal:2106513
In: ETAGE 00 (0)
Material: BS_28_Métal
Pset_XX_AsBuilt - Catégorie: Ossature; Classification BBsfB: 28.; Numéro d'article du CCTB: 23.42.1a; Fabricant: RS Contruction; Fournisseur/Installateur: De Graeve; Famille: Console métal4; Type: Console métal; Durée de garantie (mois): 0; Périodicité de contrôle (mois): 0; Référence FT**: PLA_015
Pset_XX_Poutres - Résistance au feu: RF60

# IfcBuildingElementProxy: Console métal5_Console métal, Console métal5:Console métal:2106525
In: ETAGE 00 (0)
Material: BS_28_Métal
Pset_XX_AsBuilt - Catégorie: Ossature; Classification BBsfB: 28.; Numéro d'article du CCTB: 23.42.1a; Fabricant: RS Contruction; Fournisseur/Installateur: De Graeve; Famille: Console métal5; Type: Console métal; Durée de garantie (mois): 0; Périodicité de contrôle (mois): 0; Référence FT**: PLA_015
Pset_XX_Poutres - Résistance au feu: RF60

# IfcBuildingElementProxy: Console métal6_Console métal, Console métal6:Console métal:2106549
In: ETAGE 00 (0)
Material: BS_28_Console métal
Pset_XX_AsBuilt - Catégorie: Ossature; Classification BBsfB: 28.; Numéro d'article du CCTB: 23.42.1a; Fabricant: RS Contruction; Fournisseur/Installateur: De Graeve; Famille: Console métal6; Type: Console métal; Durée de garantie (mois): 0; Périodicité de contrôle (mois): 0; Référence FT**: PLA_015
Pset_XX_Poutres - Résistance au feu: RF60

# IfcBuildingElementProxy: Console métal7_Console métal, Console métal7:Console métal:2106561
In: ETAGE 00 (0)
Material: BS_28_Métal
Pset_XX_AsBuilt - Catégorie: Ossature; Classification BBsfB: 28.; Numéro d'article du CCTB: 23.42.1a; Fabricant: RS Contruction; Fournisseur/Installateur: De Graeve; Famille: Console métal7; Type: Console métal; Durée de garantie (mois): 0; Périodicité de contrôle (mois): 0; Référence FT**: PLA_015
Pset_XX_Poutres - Résistance au feu: RF60

# IfcBuildingElementProxy: Console métal8_Console métal, Console métal8:Console métal:2106537
In: ETAGE 00 (0)
Material: BS_28_Métal
Pset_XX_AsBuilt - Catégorie: Ossature; Classification BBsfB: 28.; Numéro d'article du CCTB: 23.42.1a; Fabricant: RS Contruction; Fournisseur/Installateur: De Graeve; Famille: Console métal8; Type: Console métal; Durée de garantie (mois): 0; Périodicité de contrôle (mois): 0; Référence FT**: PLA_015
Pset_XX_Poutres - Résistance au feu: RF60

# IfcBuildingElementProxy: Console métal9_Console métal, Console métal9:Console métal:2106662
In: ETAGE 10 (1)
Material: BS_28_Console métal
Pset_XX_AsBuilt - Catégorie: Ossature; Classification BBsfB: 28.; Numéro d'article du CCTB: 23.42.1a; Fabricant: RS Contruction; Fournisseur/Installateur: De Graeve; Famille: Console métal9; Type: Console métal; Durée de garantie (mois): 0; Périodicité de contrôle (mois): 0; Référence FT**: PLA_015
Pset_XX_Poutres - Résistance au feu: RF60

# IfcBuildingElementProxy: DGLI-P1B-PL-204_Initiale - Base, DGLI-P1B-PL-204_Initiale - Base:DGLI-P1B-PL-204_Initiale - Base:3801655
In: ETAGE 00 (0)
Material: <Unnamed>
Pset_XX_AsBuilt - Catégorie: Modèles génériques; Famille: DGLI-P1B-PL-204_Initiale - Base; Type: DGLI-P1B-PL-204_Initiale - Base; Durée de garantie (mois): 0; Périodicité de contrôle (mois): 0

# IfcBuildingElementProxy: DG_28_SF_LE_Plat métallique1_Plat 50x30_1, DG_28_SF_LE_Plat métallique1:Plat 50x30_1:2167241
In: ETAGE 10 (1)
Material: BS_28_Métal
Pset_XX_AsBuilt - Catégorie: Ossature; Classification BBsfB: 28.; Numéro d'article du CCTB: 23.11.1; Fabricant: RS Contruction; Fournisseur/Installateur: De Graeve; Famille: DG_28_SF_LE_Plat métallique1; Type: Plat 50x30_1; Durée de garantie (mois): 0; Périodicité de contrôle (mois): 0; Référence FT**: PLA_015
Pset_XX_Poutres - Résistance au feu: RF60

# IfcBuildingElementProxy: DG_28_SF_LE_Plat métallique_Plat 50x30, DG_28_SF_LE_Plat métallique:Plat 50x30:2167012
In: ETAGE 10 (1)
Material: BS_28_Métal
Pset_XX_AsBuilt - Catégorie: Ossature; Classification BBsfB: 28.; Numéro d'article du CCTB: 23.11.1; Fabricant: RS Contruction; Fournisseur/Installateur: De Graeve; Famille: DG_28_SF_LE_Plat métallique; Type: Plat 50x30; Durée de garantie (mois): 0; Périodicité de contrôle (mois): 0; Référence FT**: PLA_015
Pset_XX_Poutres - Résistance au feu: RF60

# IfcBuildingElementProxy: Ossature 3_Ossature 3, Ossature 3:Ossature 3:2174359
In: ETAGE 00 (0)
Material: BS_28_Ossature en béton armé - Eléments coulé sur place
Pset_XX_AsBuilt - Catégorie: Ossature; Famille: Ossature 3; Type: Ossature 3; Durée de garantie (mois): 0; Périodicité de contrôle (mois): 0
Pset_XX_Poutres - Résistance au feu: RF60

# IfcBuildingElementProxy: Ossature 5_Ossature 3, Ossature 5:Ossature 3:2174792
In: ETAGE 00 (0)
Material: BS_28_Ossature en béton armé - Eléments coulé sur place
Pset_XX_AsBuilt - Catégorie: Ossature; Famille: Ossature 5; Type: Ossature 3; Durée de garantie (mois): 0; Périodicité de contrôle (mois): 0
Pset_XX_Poutres - Résistance au feu: RF60

# IfcColumn: BS_16_SFO_LE_Colonne rectangulaire_coulé_B.A. 40x40cm, BS_16_SFO_LE_Colonne rectangulaire_coulé:B.A. 40x40cm:2202920
In: FOND 00 (0)
Classification: 16. FONDATIONS - MURS DE SOUTENEMENT (https://www.csiresources.org/standards/uniformat); Material: BS_16_Plot en béton armé coulé sur place
Pset_XX_AsBuilt - Catégorie: Poteaux porteurs; Classification BBsfB: 16.; Numéro d'article du CCTB: 12.32.; Fabricant: De Graeve; Fournisseur/Installateur: De Graeve; Famille: BS_16_SFO_LE_Colonne rectangulaire_coulé; Type: B.A. 40x40cm; Niveau: FOND 00 (0); Durée de garantie (mois): 0; Périodicité de contrôle (mois): 0
Pset_XX_Colonnes - Résistance au feu: RF60; Construction: Coulé

# IfcColumn: BS_16_SFO_LE_Colonne rectangulaire_coulé_B.A. 40x40cm1, BS_16_SFO_LE_Colonne rectangulaire_coulé:B.A. 40x40cm:2203835
In: ETAGE 00 (0)
Classification: 16. FONDATIONS - MURS DE SOUTENEMENT (https://www.csiresources.org/standards/uniformat); Material: BS_16_Plot en béton armé coulé sur place
Pset_XX_AsBuilt - Catégorie: Poteaux porteurs; Classification BBsfB: 16.; Numéro d'article du CCTB: 12.32.; Fabricant: De Graeve; Fournisseur/Installateur: De Graeve; Famille: BS_16_SFO_LE_Colonne rectangulaire_coulé; Type: B.A. 40x40cm; Niveau: ETAGE 00 (0); Durée de garantie (mois): 0; Périodicité de contrôle (mois): 0
Pset_XX_Colonnes - Résistance au feu: RF60; Construction: Coulé

# IfcColumn: BS_16_SFO_LE_Colonne rectangulaire_coulé_B.A. 40x40cm3, BS_16_SFO_LE_Colonne rectangulaire_coulé:B.A. 40x40cm:2204038
In: ETAGE 00 (0)
Classification: 16. FONDATIONS - MURS DE SOUTENEMENT (https://www.csiresources.org/standards/uniformat); Material: BS_16_Plot en béton armé coulé sur place
Pset_XX_AsBuilt - Catégorie: Poteaux porteurs; Classification BBsfB: 16.; Numéro d'article du CCTB: 12.32.; Fabricant: De Graeve; Fournisseur/Installateur: De Graeve; Famille: BS_16_SFO_LE_Colonne rectangulaire_coulé; Type: B.A. 40x40cm; Niveau: ETAGE 00 (0); Durée de garantie (mois): 0; Périodicité de contrôle (mois): 0
Pset_XX_Colonnes - Résistance au feu: RF60; Construction: Coulé

# IfcColumn: BS_28_SCO_LE_Poteau HE-A_HEA120, BS_28_SCO_LE_Poteau HE-A:HEA120:1698522
In: ETAGE -1
Classification: 28. OSSATURE (https://www.csiresources.org/standards/uniformat); Material: BS_28_Métal
Pset_XX_AsBuilt - Catégorie: Poteaux porteurs; Classification BBsfB: 28.; Numéro d'article du CCTB: 23.14.1a.01; Fabricant: RS Construction; Fournisseur/Installateur: De Graeve; Famille: BS_28_SCO_LE_Poteau HE-A; Type: HEA120; Identifiant: C.0.42; Niveau: ETAGE 00 (0); Durée de garantie (mois): 0; Périodicité de contrôle (mois): 0
Pset_XX_Colonnes - Résistance au feu: RF60

# IfcColumn: BS_28_SCO_LE_Poteau HE-A_HEA120_1, BS_28_SCO_LE_Poteau HE-A:HEA120:1698604
In: ETAGE -1
Classification: 28. OSSATURE (https://www.csiresources.org/standards/uniformat); Material: BS_28_Métal
Pset_XX_AsBuilt - Catégorie: Poteaux porteurs; Classification BBsfB: 28.; Numéro d'article du CCTB: 23.14.1a.01; Fabricant: RS Construction; Fournisseur/Installateur: De Graeve; Famille: BS_28_SCO_LE_Poteau HE-A; Type: HEA120; Identifiant: C.0.43; Niveau: ETAGE 00 (0); Durée de garantie (mois): 0; Périodicité de contrôle (mois): 0
Pset_XX_Colonnes - Résistance au feu: RF60

# IfcColumn: BS_28_SCO_LE_Poteau HE-A_HEA120_3, BS_28_SCO_LE_Poteau HE-A:HEA120:1698623
In: ETAGE -1
Classification: 28. OSSATURE (https://www.csiresources.org/standards/uniformat); Material: BS_28_Métal
Pset_XX_AsBuilt - Catégorie: Poteaux porteurs; Classification BBsfB: 28.; Numéro d'article du CCTB: 23.14.1a.01; Fabricant: RS Construction; Fournisseur/Installateur: De Graeve; Famille: BS_28_SCO_LE_Poteau HE-A; Type: HEA120; Identifiant: C.0.44; Niveau: ETAGE 00 (0); Durée de garantie (mois): 0; Périodicité de contrôle (mois): 0
Pset_XX_Colonnes - Résistance au feu: RF60

# IfcColumn: BS_28_SCO_LE_Poteau HE-A_HEA120_5, BS_28_SCO_LE_Poteau HE-A:HEA120:1698656
In: ETAGE -1
Classification: 28. OSSATURE (https://www.csiresources.org/standards/uniformat); Material: BS_28_Métal
Pset_XX_AsBuilt - Catégorie: Poteaux porteurs; Classification BBsfB: 28.; Numéro d'article du CCTB: 23.14.1a.01; Fabricant: RS Construction; Fournisseur/Installateur: De Graeve; Famille: BS_28_SCO_LE_Poteau HE-A; Type: HEA120; Identifiant: C.0.45; Niveau: ETAGE 00 (0); Durée de garantie (mois): 0; Périodicité de contrôle (mois): 0
Pset_XX_Colonnes - Résistance au feu: RF60

# IfcColumn: BS_28_SCO_LE_Poteau HE-A_HEA140, BS_28_SCO_LE_Poteau HE-A:HEA140:1302277
In: ETAGE 00 (0)
Classification: 28. OSSATURE (https://www.csiresources.org/standards/uniformat); Material: BS_28_Métal
Pset_XX_AsBuilt - Catégorie: Poteaux porteurs; Classification BBsfB: 28.; Numéro d'article du CCTB: 23.14.1a.02; Fabricant: RS Construction; Fournisseur/Installateur: De Graeve; Famille: BS_28_SCO_LE_Poteau HE-A; Type: HEA140; Identifiant: C.0.30; Niveau: ETAGE 00 (0); Durée de garantie (mois): 0; Périodicité de contrôle (mois): 0
Pset_XX_Colonnes - Résistance au feu: RF60

# IfcColumn: BS_28_SCO_LE_Poteau HE-A_HEA140_1, BS_28_SCO_LE_Poteau HE-A:HEA140:1386850
In: ETAGE 00 (0)
Classification: 28. OSSATURE (https://www.csiresources.org/standards/uniformat); Material: BS_28_Métal
Pset_XX_AsBuilt - Catégorie: Poteaux porteurs; Classification BBsfB: 28.; Numéro d'article du CCTB: 23.14.1a.02; Fabricant: RS Construction; Fournisseur/Installateur: De Graeve; Famille: BS_28_SCO_LE_Poteau HE-A; Type: HEA140; Identifiant: C.0.36; Niveau: ETAGE 00 (0); Durée de garantie (mois): 0; Périodicité de contrôle (mois): 0
Pset_XX_Colonnes - Résistance au feu: RF60

# IfcColumn: BS_28_SCO_LE_Poteau HE-A_HEA140_11, BS_28_SCO_LE_Poteau HE-A:HEA140:1940692
In: ETAGE 00 (0)
Classification: 28. OSSATURE (https://www.csiresources.org/standards/uniformat); Material: BS_28_Métal
Pset_XX_AsBuilt - Catégorie: Poteaux porteurs; Classification BBsfB: 28.; Numéro d'article du CCTB: 23.14.1a.02; Fabricant: RS Construction; Fournisseur/Installateur: De Graeve; Famille: BS_28_SCO_LE_Poteau HE-A; Type: HEA140; Identifiant: C.0.50; Niveau: GO 00 (0); Durée de garantie (mois): 0; Périodicité de contrôle (mois): 0
Pset_XX_Colonnes - Résistance au feu: RF60

# IfcColumn: BS_28_SCO_LE_Poteau HE-A_HEA140_13, BS_28_SCO_LE_Poteau HE-A:HEA140:1945153
In: ETAGE 00 (0)
Classification: 28. OSSATURE (https://www.csiresources.org/standards/uniformat); Material: BS_28_Métal
Pset_XX_AsBuilt - Catégorie: Poteaux porteurs; Classification BBsfB: 28.; Numéro d'article du CCTB: 23.14.1a.02; Fabricant: RS Construction; Fournisseur/Installateur: De Graeve; Famille: BS_28_SCO_LE_Poteau HE-A; Type: HEA140; Identifiant: C.1.14; Niveau: GO 10 (1); Durée de garantie (mois): 0; Périodicité de contrôle (mois): 0
Pset_XX_Colonnes - Résistance au feu: RF60

# IfcColumn: BS_28_SCO_LE_Poteau HE-A_HEA140_3, BS_28_SCO_LE_Poteau HE-A:HEA140:1424727
In: ETAGE 00 (0)
Classification: 28. OSSATURE (https://www.csiresources.org/standards/uniformat); Material: BS_28_Métal
Pset_XX_AsBuilt - Catégorie: Poteaux porteurs; Classification BBsfB: 28.; Numéro d'article du CCTB: 23.14.1a.02; Fabricant: RS Construction; Fournisseur/Installateur: De Graeve; Famille: BS_28_SCO_LE_Poteau HE-A; Type: HEA140; Identifiant: C.0.39; Niveau: ETAGE 00 (0); Durée de garantie (mois): 0; Périodicité de contrôle (mois): 0
Pset_XX_Colonnes - Résistance au feu: RF60

# IfcColumn: BS_28_SCO_LE_Poteau HE-A_HEA140_5, BS_28_SCO_LE_Poteau HE-A:HEA140:1424783
In: ETAGE 00 (0)
Classification: 28. OSSATURE (https://www.csiresources.org/standards/uniformat); Material: BS_28_Métal
Pset_XX_AsBuilt - Catégorie: Poteaux porteurs; Classification BBsfB: 28.; Numéro d'article du CCTB: 23.14.1a.02; Fabricant: RS Construction; Fournisseur/Installateur: De Graeve; Famille: BS_28_SCO_LE_Poteau HE-A; Type: HEA140; Identifiant: C.0.40; Niveau: ETAGE 00 (0); Durée de garantie (mois): 0; Périodicité de contrôle (mois): 0
Pset_XX_Colonnes - Résistance au feu: RF60

# IfcColumn: BS_28_SCO_LE_Poteau HE-A_HEA140_7, BS_28_SCO_LE_Poteau HE-A:HEA140:1424814
In: ETAGE 00 (0)
Classification: 28. OSSATURE (https://www.csiresources.org/standards/uniformat); Material: BS_28_Métal
Pset_XX_AsBuilt - Catégorie: Poteaux porteurs; Classification BBsfB: 28.; Numéro d'article du CCTB: 23.14.1a.02; Fabricant: RS Construction; Fournisseur/Installateur: De Graeve; Famille: BS_28_SCO_LE_Poteau HE-A; Type: HEA140; Identifiant: C.0.41; Niveau: ETAGE 00 (0); Durée de garantie (mois): 0; Périodicité de contrôle (mois): 0
Pset_XX_Colonnes - Résistance au feu: RF60

# IfcColumn: BS_28_SCO_LE_Poteau HE-A_HEA140_9, BS_28_SCO_LE_Poteau HE-A:HEA140:1888999
In: ETAGE 00 (0)
Classification: 28. OSSATURE (https://www.csiresources.org/standards/uniformat); Material: BS_28_Métal
Pset_XX_AsBuilt - Catégorie: Poteaux porteurs; Classification BBsfB: 28.; Numéro d'article du CCTB: 23.14.1a.02; Fabricant: RS Construction; Fournisseur/Installateur: De Graeve; Famille: BS_28_SCO_LE_Poteau HE-A; Type: HEA140; Identifiant: C.1.12; Niveau: GO 10 (1); Durée de garantie (mois): 0; Périodicité de contrôle (mois): 0
Pset_XX_Colonnes - Résistance au feu: RF60

# IfcColumn: BS_28_SCO_LE_Poteau HE-A_HEA180, BS_28_SCO_LE_Poteau HE-A:HEA180:1295772
In: ETAGE 00 (0)
Classification: 28. OSSATURE (https://www.csiresources.org/standards/uniformat); Material: BS_28_Métal
Pset_XX_AsBuilt - Catégorie: Poteaux porteurs; Classification BBsfB: 28.; Numéro d'article du CCTB: 23.14.1a.03; Fabricant: RS Construction; Fournisseur/Installateur: De Graeve; Famille: BS_28_SCO_LE_Poteau HE-A; Type: HEA180; Identifiant: C.1.1; Niveau: GO 10 (1); Durée de garantie (mois): 0; Périodicité de contrôle (mois): 0
Pset_XX_Colonnes - Résistance au feu: RF60

# IfcColumn: BS_28_SCO_LE_Poteau HE-A_HEA180_1, BS_28_SCO_LE_Poteau HE-A:HEA180:1295783
In: ETAGE 00 (0)
Classification: 28. OSSATURE (https://www.csiresources.org/standards/uniformat); Material: BS_28_Métal
Pset_XX_AsBuilt - Catégorie: Poteaux porteurs; Classification BBsfB: 28.; Numéro d'article du CCTB: 23.14.1a.03; Fabricant: RS Construction; Fournisseur/Installateur: De Graeve; Famille: BS_28_SCO_LE_Poteau HE-A; Type: HEA180; Identifiant: C.1.2; Niveau: GO 10 (1); Durée de garantie (mois): 0; Périodicité de contrôle (mois): 0
Pset_XX_Colonnes - Résistance au feu: RF60

# IfcColumn: BS_28_SCO_LE_Poteau HE-A_HEA180_3, BS_28_SCO_LE_Poteau HE-A:HEA180:1297991
In: ETAGE 00 (0)
Classification: 28. OSSATURE (https://www.csiresources.org/standards/uniformat); Material: BS_28_Métal
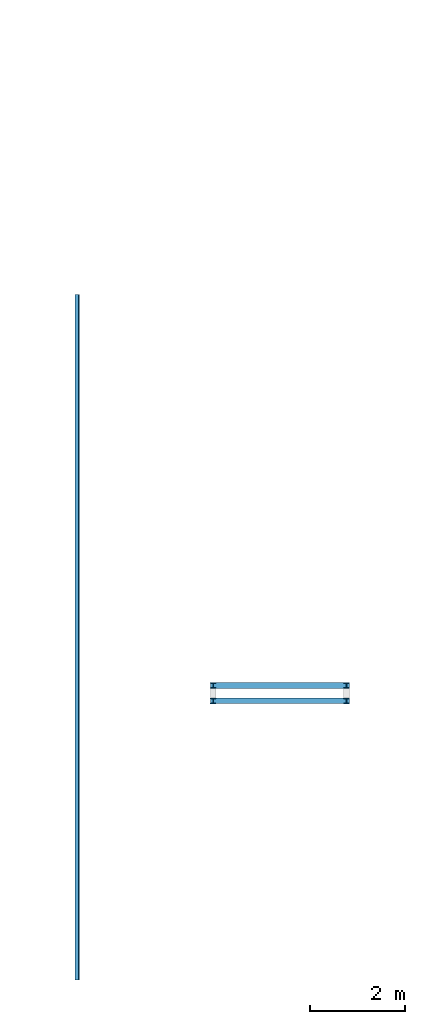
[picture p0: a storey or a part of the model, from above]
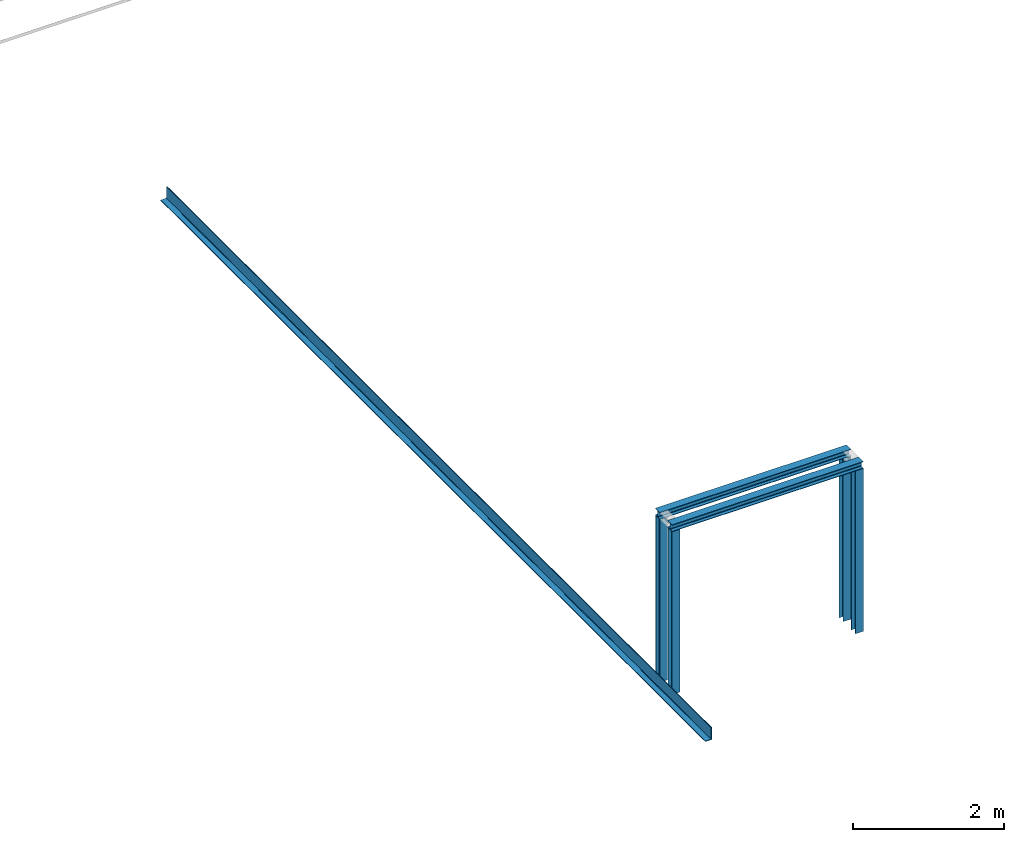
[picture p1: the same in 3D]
Properties of the parts of a building model (IFC4X3_ADD2), part 3 of 4

# IfcColumn: BS_28_SCO_LE_Poteau HE-A_HEA180_3, BS_28_SCO_LE_Poteau HE-A:HEA180:1297991
Pset_XX_AsBuilt - Catégorie: Poteaux porteurs; Classification BBsfB: 28.; Numéro d'article du CCTB: 23.14.1a.03; Fabricant: RS Construction; Fournisseur/Installateur: De Graeve; Famille: BS_28_SCO_LE_Poteau HE-A; Type: HEA180; Identifiant: C.1.3; Niveau: GO 10 (1); Durée de garantie (mois): 0; Périodicité de contrôle (mois): 0
Pset_XX_Colonnes - Résistance au feu: RF60

# IfcColumn: BS_28_SCO_LE_Poteau HE-A_HEA180_5, BS_28_SCO_LE_Poteau HE-A:HEA180:1297993
In: ETAGE 00 (0)
Classification: 28. OSSATURE (https://www.csiresources.org/standards/uniformat); Material: BS_28_Métal
Pset_XX_AsBuilt - Catégorie: Poteaux porteurs; Classification BBsfB: 28.; Numéro d'article du CCTB: 23.14.1a.03; Fabricant: RS Construction; Fournisseur/Installateur: De Graeve; Famille: BS_28_SCO_LE_Poteau HE-A; Type: HEA180; Identifiant: C.1.4; Niveau: GO 10 (1); Durée de garantie (mois): 0; Périodicité de contrôle (mois): 0
Pset_XX_Colonnes - Résistance au feu: RF60

# IfcColumn: BS_28_SCO_LE_Poteau HE-A_HEA200, BS_28_SCO_LE_Poteau HE-A:HEA200:1281571
In: FOND 00 (0)
Classification: 28. OSSATURE (https://www.csiresources.org/standards/uniformat); Material: BS_28_Métal
Pset_XX_AsBuilt - Catégorie: Poteaux porteurs; Classification BBsfB: 28.; Numéro d'article du CCTB: 23.14.1a.04; Fabricant: RS Construction; Fournisseur/Installateur: De Graeve; Famille: BS_28_SCO_LE_Poteau HE-A; Type: HEA200; Identifiant: C.0.9; Niveau: FOND 00 (0); Durée de garantie (mois): 0; Périodicité de contrôle (mois): 0
Pset_XX_Colonnes - Résistance au feu: RF60

# IfcColumn: BS_28_SCO_LE_Poteau HE-A_HEA200_1, BS_28_SCO_LE_Poteau HE-A:HEA200:1391466
In: FOND 00 (0)
Classification: 28. OSSATURE (https://www.csiresources.org/standards/uniformat); Material: BS_28_Métal
Pset_XX_AsBuilt - Catégorie: Poteaux porteurs; Classification BBsfB: 28.; Numéro d'article du CCTB: 23.14.1a.04; Fabricant: RS Construction; Fournisseur/Installateur: De Graeve; Famille: BS_28_SCO_LE_Poteau HE-A; Type: HEA200; Identifiant: C.0.38; Niveau: FOND 00 (0); Durée de garantie (mois): 0; Périodicité de contrôle (mois): 0
Pset_XX_Colonnes - Résistance au feu: RF60

# IfcColumn: BS_28_SCO_LE_Poteau RO (EN 10219-2)_CHS 193.7x10, BS_28_SCO_LE_Poteau RO (EN 10219-2):CHS 193.7x10:1758470
In: FOND 00 (0)
Classification: 28. OSSATURE (https://www.csiresources.org/standards/uniformat); Material: BS_28_Métal
Pset_XX_AsBuilt - Catégorie: Poteaux porteurs; Classification BBsfB: 28.; Numéro d'article du CCTB: 23.14.1a.07; Fabricant: RS Construction; Fournisseur/Installateur: De Graeve; Famille: BS_28_SCO_LE_Poteau RO (EN 10219-2); Type: CHS 193.7x10; Identifiant: C.0.46; Niveau: FOND 00 (0); Durée de garantie (mois): 0; Périodicité de contrôle (mois): 0
Pset_XX_Colonnes - Résistance au feu: RF60

# IfcColumn: BS_28_SCO_LE_Poteau RO (EN 10219-2)_CHS 193.7x10_1, BS_28_SCO_LE_Poteau RO (EN 10219-2):CHS 193.7x10:1759053
In: FOND 00 (0)
Classification: 28. OSSATURE (https://www.csiresources.org/standards/uniformat); Material: BS_28_Métal
Pset_XX_AsBuilt - Catégorie: Poteaux porteurs; Classification BBsfB: 28.; Numéro d'article du CCTB: 23.14.1a.07; Fabricant: RS Construction; Fournisseur/Installateur: De Graeve; Famille: BS_28_SCO_LE_Poteau RO (EN 10219-2); Type: CHS 193.7x10; Identifiant: C.0.47; Niveau: FOND 00 (0); Durée de garantie (mois): 0; Périodicité de contrôle (mois): 0
Pset_XX_Colonnes - Résistance au feu: RF60

# IfcColumn: BS_28_SCO_LE_Poteau RO (EN 10219-2)_CHS 193.7x10_3, BS_28_SCO_LE_Poteau RO (EN 10219-2):CHS 193.7x10:1759359
In: FOND 00 (0)
Classification: 28. OSSATURE (https://www.csiresources.org/standards/uniformat); Material: BS_28_Métal
Pset_XX_AsBuilt - Catégorie: Poteaux porteurs; Classification BBsfB: 28.; Numéro d'article du CCTB: 23.14.1a.07; Fabricant: RS Construction; Fournisseur/Installateur: De Graeve; Famille: BS_28_SCO_LE_Poteau RO (EN 10219-2); Type: CHS 193.7x10; Identifiant: C.0.48; Niveau: FOND 00 (0); Durée de garantie (mois): 0; Périodicité de contrôle (mois): 0
Pset_XX_Colonnes - Résistance au feu: RF60

# IfcColumn: D28 (128)
Description: D28; Group: Groupe de modèles:IFC ERGON 14122021 (membre exclu):2154686
Pset_XX_AsBuilt - Catégorie: Poteaux porteurs; Famille: Forme directe; Type: D28; Durée de garantie (mois): 0; Périodicité de contrôle (mois): 0
Name | In
12 x ZW9 | ETAGE 00 (0)
76 x ZW9 | ETAGE 10 (1)
40 x ZW9 | ETAGE 20 (2)

# IfcColumn: EB_CR_390*390*15 (28)
Description: EB_CR_390*390*15; Classification: 28. OSSATURE (https://www.csiresources.org/standards/uniformat); Group: Groupe de modèles:IFC ERGON 14122021 (membre exclu):2154686
Pset_XX_AsBuilt - Catégorie: Poteaux porteurs; Classification BBsfB: 28.; Numéro d'article du CCTB: 22.14.2b; Fabricant: ERGON; Fournisseur/Installateur: De Graeve; Famille: Forme directe; Type: EB_CR_390*390*15; Durée de garantie (mois): 0; Périodicité de contrôle (mois): 0
Pset_XX_Colonnes - Résistance au feu: RF60; Construction: Préfabriqué
Name | In | Identifiant | Taux de ferraillage (kg/m³)
COLUMN | FOND 00 (0) | K29 | 398.15
2 x COLUMN | FOND 00 (0) | K22 | 83.68
COLUMN | FOND 00 (0) | K23 | 84.75
COLUMN | FOND 00 (0) | K24 | 118.06
COLUMN | FOND 00 (0) | K30 | 118.06
COLUMN | FOND 00 (0) | K35 | 77.25
COLUMN | FOND 00 (0) | K12 | 77.69
COLUMN | FOND 00 (0) | K10 | 77.51
COLUMN | FOND 00 (0) | K11 | 77.51
COLUMN | FOND 00 (0) | K14 | 90.62
COLUMN | FOND 00 (0) | K9 | 82.92
COLUMN | FOND 00 (0) | K20 | 89.4
COLUMN | FOND 00 (0) | K16 | 74.45
COLUMN | FOND 00 (0) | K21 | 404.31
COLUMN | FOND 00 (0) | K19 | 72.04
COLUMN | FOND 00 (0) | K18 | 72.62
COLUMN | FOND 00 (0) | K17 | 72.79
COLUMN | FOND 00 (0) | K1 | 105.59
COLUMN | FOND 00 (0) | K2 | 105.82
COLUMN | FOND 00 (0) | K3 | 106.05
COLUMN | FOND 00 (0) | K15 | 94.51
COLUMN | ETAGE 10 (1) | K25 | 101.59
COLUMN | ETAGE 10 (1) | K32 | 100.16
COLUMN | ETAGE 10 (1) | K31 | 100.22
COLUMN | ETAGE 10 (1) | K26 | 83.82
COLUMN | ETAGE 10 (1) | K34 | 81.71
COLUMN | ETAGE 10 (1) | K33 | 83.82

# IfcColumn: EB_CR_700*390*15 (11)
In: FOND 00 (0)
Description: EB_CR_700*390*15; Classification: 28. OSSATURE (https://www.csiresources.org/standards/uniformat); Group: Groupe de modèles:IFC ERGON 14122021 (membre exclu):2154686
Pset_XX_AsBuilt - Catégorie: Poteaux porteurs; Classification BBsfB: 28.; Numéro d'article du CCTB: 22.14.2b; Fabricant: ERGON; Fournisseur/Installateur: De Graeve; Famille: Forme directe; Type: EB_CR_700*390*15; Durée de garantie (mois): 0; Périodicité de contrôle (mois): 0
Pset_XX_Colonnes - Résistance au feu: RF60; Construction: Préfabriqué
Name | Identifiant | Taux de ferraillage (kg/m³)
COLUMN | K4 | 78.75
COLUMN | K6 | 78.89
2 x COLUMN | K27 | 79.35
2 x COLUMN | K7 | 79.49
2 x COLUMN | K28 | 79.36
2 x COLUMN | K36 | 79.28
COLUMN | K8 | 98.33

# IfcColumn: HEA160, COLUMN
In: FOND 00 (0)
Description: HEA160; Classification: 28. OSSATURE (https://www.csiresources.org/standards/uniformat); Group: Groupe de modèles:IFC ERGON 14122021 (membre exclu):2154686
Pset_XX_AsBuilt - Catégorie: Poteaux porteurs; Classification BBsfB: 28.; Numéro d'article du CCTB: 23.14.1a.04; Fabricant: RS Construction; Fournisseur/Installateur: De Graeve; Famille: Forme directe; Type: HEA160; Durée de garantie (mois): 0; Périodicité de contrôle (mois): 0
Pset_XX_Colonnes - Résistance au feu: RF60

# IfcElementAssembly: Assemblage Ossature:non repris au plan structure métallique, Assemblage Ossature:non repris au plan structure métallique:2169053
In: ETAGE -1
PredefinedType: USERDEFINED

# IfcPlate: Aucun (96)
Description: -; Material: Acier - B 500 B
Pset_PlateCommon - Reference: Pas défini; IsExternal: no; LoadBearing: no
Name | In
6 x - | FOND 00 (0)
11 x - | ETAGE 00 (0)
67 x - | ETAGE 10 (1)
12 x - | ETAGE 20 (2)

# IfcPlate: PL15*100 (6)
In: ETAGE 10 (1)
Description: PL15*100; Group: Groupe de modèles:IFC ERGON 14122021 (membre exclu):2154686
Pset_XX_AsBuilt - Catégorie: Ossature; Famille: Forme directe; Type: PL15*100; Durée de garantie (mois): 0; Périodicité de contrôle (mois): 0
Pset_XX_Poutres - Résistance au feu: RF60
Name | Identifiant
PLATE | A1
2 x PLATE | A2
PLATE | A3
PLATE | A4
PLATE | A5

# IfcPlate: PL8*250 (5)
In: ETAGE 20 (2)
Description: PL8*250; Group: Groupe de modèles:IFC ERGON 14122021 (membre exclu):2154686
Pset_XX_AsBuilt - Catégorie: Ossature; Famille: Forme directe; Type: PL8*250; Durée de garantie (mois): 0; Périodicité de contrôle (mois): 0
Pset_XX_Poutres - Résistance au feu: RF60
Name | Identifiant
2 x PS2 | 339
3 x PS2 | 340

# IfcRoof: BS_27_RO_Isolant toiture PIR:BS_27_RO_Isolant toiture PIR, BS_27_RO_Isolant toiture PIR:BS_27_RO_Isolant toiture PIR:2187767
In: ETAGE 10 (1)
Classification: 27. TOITURES (https://www.csiresources.org/standards/uniformat)
Pset_XX_AsBuilt - Catégorie: Toits; Classification BBsfB: 27.; Numéro d'article du CCTB: Isolant : 34.017.03 / Pare-vapeur : 34.24; Fabricant: Isolant : IKO / Pare-vapeur : SOPREMA; Fournisseur/Installateur: Reno-Tech; Famille: BS_27_RO_Isolant toiture PIR; Type: BS_27_RO_Isolant toiture PIR; Durée de garantie (mois): 0; Périodicité de contrôle (mois): 0; Référence FT**: Isolant : F-T_005 / Pare-vapeur : F-T_006; Modèle: Isolant : Enetherm alu / Pare-vapeur : SOPRAVAP STICK C15
Pset_XX_Isolant thermique du toit - Réaction au feu: Classe B-s2,d0; Fonction: Intérieur

# IfcRoof: BS_47_RO_Etanchéité acrotère 1 bureaux:BS_47_RO_Etanchéité acrotère 1 bureaux, BS_47_RO_Etanchéité acrotère 1 bureaux:BS_47_RO_Etanchéité acrotère 1 bureaux:3795449
In: ETAGE 10 (1)
Classification: 47.71 TOITURES-TERRASSES, ETANCHEITE ET ISOLATION (https://www.csiresources.org/standards/uniformat)
Pset_XX_AsBuilt - Catégorie: Toits; Classification BBsfB: 47.71; Numéro d'article du CCTB: 35.30.02; Fabricant: Flag; Fournisseur/Installateur: Reno-Tech; Famille: BS_47_RO_Etanchéité acrotère 1 bureaux; Type: BS_47_RO_Etanchéité acrotère 1 bureaux; Référence FT**: F-T_004; Modèle: Flagon EP/PR DE
Pset_XX_Remontée étanchéité - Réaction au feu: Classe E

# IfcRoof: BS_47_RO_Etanchéité acrotère 1 hall:BS_47_RO_Etanchéité acrotère hall, BS_47_RO_Etanchéité acrotère 1 hall:BS_47_RO_Etanchéité acrotère hall:3790973
In: ETAGE 20 (2)
Classification: 47.71 TOITURES-TERRASSES, ETANCHEITE ET ISOLATION (https://www.csiresources.org/standards/uniformat)
Pset_XX_AsBuilt - Catégorie: Toits; Classification BBsfB: 47.71; Numéro d'article du CCTB: 35.30.02; Fabricant: Flag; Fournisseur/Installateur: Reno-Tech; Famille: BS_47_RO_Etanchéité acrotère 1 hall; Type: BS_47_RO_Etanchéité acrotère hall; Référence FT**: F-T_004; Modèle: Flagon EP/PR DE
Pset_XX_Remontée étanchéité - Réaction au feu: Classe E

# IfcRoof: BS_47_RO_Etanchéité acrotère 1 technology:BS_47_RO_Etanchéité acrotère 1 technology, BS_47_RO_Etanchéité acrotère 1 technology:BS_47_RO_Etanchéité acrotère 1 technology:3793464
In: ETAGE 10 (1)
Classification: 47.71 TOITURES-TERRASSES, ETANCHEITE ET ISOLATION (https://www.csiresources.org/standards/uniformat)
Pset_XX_AsBuilt - Catégorie: Toits; Classification BBsfB: 47.71; Numéro d'article du CCTB: 35.30.02; Fabricant: Flag; Fournisseur/Installateur: Reno-Tech; Famille: BS_47_RO_Etanchéité acrotère 1 technology; Type: BS_47_RO_Etanchéité acrotère 1 technology; Référence FT**: F-T_004; Modèle: Flagon EP/PR DE
Pset_XX_Remontée étanchéité - Réaction au feu: Classe E

# IfcRoof: BS_47_RO_Etanchéité acrotère 2 bureaux:BS_47_RO_Etanchéité acrotère 1 bureaux, BS_47_RO_Etanchéité acrotère 2 bureaux:BS_47_RO_Etanchéité acrotère 1 bureaux:3795692
In: ETAGE 10 (1)
Classification: 47.71 TOITURES-TERRASSES, ETANCHEITE ET ISOLATION (https://www.csiresources.org/standards/uniformat)
Pset_XX_AsBuilt - Catégorie: Toits; Classification BBsfB: 47.71; Numéro d'article du CCTB: 35.30.02; Fabricant: Flag; Fournisseur/Installateur: Reno-Tech; Famille: BS_47_RO_Etanchéité acrotère 2 bureaux; Type: BS_47_RO_Etanchéité acrotère 1 bureaux; Référence FT**: F-T_004; Modèle: Flagon EP/PR DE
Pset_XX_Remontée étanchéité - Réaction au feu: Classe E

# IfcRoof: BS_47_RO_Etanchéité acrotère 2 hall:BS_47_RO_Etanchéité acrotère hall, BS_47_RO_Etanchéité acrotère 2 hall:BS_47_RO_Etanchéité acrotère hall:3791065
In: ETAGE 20 (2)
Classification: 47.71 TOITURES-TERRASSES, ETANCHEITE ET ISOLATION (https://www.csiresources.org/standards/uniformat)
Pset_XX_AsBuilt - Catégorie: Toits; Classification BBsfB: 47.71; Numéro d'article du CCTB: 35.30.02; Fabricant: Flag; Fournisseur/Installateur: Reno-Tech; Famille: BS_47_RO_Etanchéité acrotère 2 hall; Type: BS_47_RO_Etanchéité acrotère hall; Référence FT**: F-T_004; Modèle: Flagon EP/PR DE
Pset_XX_Remontée étanchéité - Réaction au feu: Classe E

# IfcRoof: BS_47_RO_Etanchéité acrotère 2 technology:BS_47_RO_Etanchéité acrotère 1 technology, BS_47_RO_Etanchéité acrotère 2 technology:BS_47_RO_Etanchéité acrotère 1 technology:3793660
In: ETAGE 10 (1)
Classification: 47.71 TOITURES-TERRASSES, ETANCHEITE ET ISOLATION (https://www.csiresources.org/standards/uniformat)
Pset_XX_AsBuilt - Catégorie: Toits; Classification BBsfB: 47.71; Numéro d'article du CCTB: 35.30.02; Fabricant: Flag; Fournisseur/Installateur: Reno-Tech; Famille: BS_47_RO_Etanchéité acrotère 2 technology; Type: BS_47_RO_Etanchéité acrotère 1 technology; Référence FT**: F-T_004; Modèle: Flagon EP/PR DE
Pset_XX_Remontée étanchéité - Réaction au feu: Classe E

# IfcRoof: BS_47_RO_Etanchéité acrotère 3 bureaux:BS_47_RO_Etanchéité acrotère 3 bureaux, BS_47_RO_Etanchéité acrotère 3 bureaux:BS_47_RO_Etanchéité acrotère 3 bureaux:3796049
In: ETAGE 10 (1)
Classification: 47.71 TOITURES-TERRASSES, ETANCHEITE ET ISOLATION (https://www.csiresources.org/standards/uniformat)
Pset_XX_AsBuilt - Catégorie: Toits; Classification BBsfB: 47.71; Numéro d'article du CCTB: 35.30.02; Fabricant: Flag; Fournisseur/Installateur: Reno-Tech; Famille: BS_47_RO_Etanchéité acrotère 3 bureaux; Type: BS_47_RO_Etanchéité acrotère 3 bureaux; Référence FT**: F-T_004; Modèle: Flagon EP/PR DE
Pset_XX_Remontée étanchéité - Réaction au feu: Classe E

# IfcRoof: BS_47_RO_Etanchéité acrotère 3 hall:BS_47_RO_Etanchéité acrotère hall 2, BS_47_RO_Etanchéité acrotère 3 hall:BS_47_RO_Etanchéité acrotère hall 2:3791719
In: ETAGE 20 (2)
Classification: 47.71 TOITURES-TERRASSES, ETANCHEITE ET ISOLATION (https://www.csiresources.org/standards/uniformat)
Pset_XX_AsBuilt - Catégorie: Toits; Classification BBsfB: 47.71; Numéro d'article du CCTB: 35.30.02; Fabricant: Flag; Fournisseur/Installateur: Reno-Tech; Famille: BS_47_RO_Etanchéité acrotère 3 hall; Type: BS_47_RO_Etanchéité acrotère hall 2; Référence FT**: F-T_004; Modèle: Flagon EP/PR DE
Pset_XX_Remontée étanchéité - Réaction au feu: Classe E

# IfcRoof: BS_47_RO_Etanchéité acrotère 3 technology:BS_47_RO_Etanchéité acrotère 3 technology, BS_47_RO_Etanchéité acrotère 3 technology:BS_47_RO_Etanchéité acrotère 3 technology:3794097
In: ETAGE 10 (1)
Classification: 47.71 TOITURES-TERRASSES, ETANCHEITE ET ISOLATION (https://www.csiresources.org/standards/uniformat)
Pset_XX_AsBuilt - Catégorie: Toits; Classification BBsfB: 47.71; Numéro d'article du CCTB: 35.30.02; Fabricant: Flag; Fournisseur/Installateur: Reno-Tech; Famille: BS_47_RO_Etanchéité acrotère 3 technology; Type: BS_47_RO_Etanchéité acrotère 3 technology; Référence FT**: F-T_004; Modèle: Flagon EP/PR DE
Pset_XX_Remontée étanchéité - Réaction au feu: Classe E

# IfcRoof: BS_47_RO_Etanchéité acrotère 4 hall:BS_47_RO_Etanchéité acrotère 3, BS_47_RO_Etanchéité acrotère 4 hall:BS_47_RO_Etanchéité acrotère 3:3792363
In: ETAGE 20 (2)
Classification: 47.71 TOITURES-TERRASSES, ETANCHEITE ET ISOLATION (https://www.csiresources.org/standards/uniformat)
Pset_XX_AsBuilt - Catégorie: Toits; Classification BBsfB: 47.71; Numéro d'article du CCTB: 35.30.02; Fabricant: Flag; Fournisseur/Installateur: Reno-Tech; Famille: BS_47_RO_Etanchéité acrotère 4 hall; Type: BS_47_RO_Etanchéité acrotère 3; Référence FT**: F-T_004; Modèle: Flagon EP/PR DE
Pset_XX_Remontée étanchéité - Réaction au feu: Classe E

# IfcRoof: Toit de base:BS_27_RO_BACMET153 (3)
In: ETAGE 20 (2)
Classification: 27. TOITURES (https://www.csiresources.org/standards/uniformat)
Pset_XX_AsBuilt - Catégorie: Toits; Classification BBsfB: 27.; Numéro d'article du CCTB: 31.22.1a.02; Fabricant: Joriside; Fournisseur/Installateur: D-Tech; Famille: Toit de base; Type: BS_27_RO_BACMET153; Durée de garantie (mois): 0; Périodicité de contrôle (mois): 0; Référence FT**: F-T_001; Modèle: JI 153-280-840
Pset_XX_Support toiture - Résistance au feu: RF30; Surcharge admissible (kN/m²): 0.8
Name (Toit de base:BS_27_RO_BACMET153:...)
1301982 | Pset_XX_AsBuilt - Identifiant: T..3
2170852
2171053

# IfcRoof: Toit de base:BS_27_RO_Isolant toiture PIR (3)
In: ETAGE 20 (2)
Classification: 27. TOITURES (https://www.csiresources.org/standards/uniformat)
Pset_XX_AsBuilt - Catégorie: Toits; Classification BBsfB: 27.; Numéro d'article du CCTB: Isolant : 34.017.03 / Pare-vapeur : 34.24; Fabricant: Isolant : IKO / Pare-vapeur : SOPREMA; Fournisseur/Installateur: Reno-Tech; Famille: Toit de base; Type: BS_27_RO_Isolant toiture PIR; Durée de garantie (mois): 0; Périodicité de contrôle (mois): 0; Référence FT**: Isolant : F-T_005 / Pare-vapeur : F-T_006; Modèle: Isolant : Enetherm alu / Pare-vapeur : SOPRAVAP STICK C15
Pset_XX_Isolant thermique du toit - Réaction au feu: Classe B-s2,d0; Fonction: Intérieur
Pset_XX_Support toiture - Résistance au feu: RF30
Name (Toit de base:BS_27_RO_Isolant toiture PIR:...)
1288570 | Pset_XX_AsBuilt - Identifiant: T..1
2171016
2171041

# IfcRoof: Toit de base:BS_47_RO_Etanchéité toiture (3)
In: ETAGE 20 (2)
Classification: 47.71 TOITURES-TERRASSES, ETANCHEITE ET ISOLATION (https://www.csiresources.org/standards/uniformat)
Pset_XX_AsBuilt - Catégorie: Toits; Classification BBsfB: 47.71; Numéro d'article du CCTB: 35.30.01; Fabricant: Flag; Fournisseur/Installateur: Reno-Tech; Famille: Toit de base; Type: BS_47_RO_Etanchéité toiture; Durée de garantie (mois): 0; Périodicité de contrôle (mois): 0; Référence FT**: F-T_004; Modèle: Flagon EP/PR DE
Pset_XX_Couverture toiture - Réaction au feu: Classe E
Pset_XX_Support toiture - Résistance au feu: RF30
Name (Toit de base:BS_47_RO_Etanchéité toiture:...)
3789089
3789334
3789432

# IfcSlab: BS_13_Sable stabilisé(Remblai) 0 (19)
In: FOND 00 (0)
Type - PredefinedType: FLOOR; Material: BS_13_Sable stabilisé(Remblai)
Pset_XX_AsBuilt - Catégorie: Sols; Niveau: FOND 00 (0); Durée de garantie (mois): 0; Périodicité de contrôle (mois): 0
Name | Famille | Type
Remblai 9:Remblai 9:1656924 | Remblai 9 | Remblai 9 | Pset_XX_AsBuilt - Identifiant: S.0.08
Remblai 10:Remblai 10:1967810 | Remblai 10 | Remblai 10
Remblai 12:Remblai 12:1968138 | Remblai 12 | Remblai 12
Remblai 7:Remblai 7:2127803 | Remblai 7 | Remblai 7
Remblai 13:Remblai 13:2128150 | Remblai 13 | Remblai 13
Remblai 4:Remblai 4:2128933 | Remblai 4 | Remblai 4
Remblai 5:Remblai 5:2129254 | Remblai 5 | Remblai 5
Remblai 21:Remblai 4:2129337 | Remblai 21 | Remblai 4
Remblai 3:Remblai 3:2130057 | Remblai 3 | Remblai 3 | Pset_XX_AsBuilt - Numéro d'article du CCTB: -
Remblai 15:Remblai 15:2130583 | Remblai 15 | Remblai 15
Remblai 16:Remblai 16:2131442 | Remblai 16 | Remblai 16
Remblai 17:Remblai 17:2131638 | Remblai 17 | Remblai 17 | Pset_xx_Fondations - Résistance au feu: -
Remblai 14:Remblai 14:2131789 | Remblai 14 | Remblai 14
Remblai 11:Remblai 11:2131845 | Remblai 11 | Remblai 11
Remblai 6:Remblai 6:2132118 | Remblai 6 | Remblai 6
Remblai 20:Remblai 20:2132588 | Remblai 20 | Remblai 20
Remblai 18:Remblai 18:2132838 | Remblai 18 | Remblai 18
Remblai 19:Remblai 19:2133062 | Remblai 19 | Remblai 19
Remblai 2:Remblai 2:2203357 | Remblai 2 | Remblai 2 | Pset_XX_AsBuilt - Numéro d'article du CCTB: -

# IfcSlab: BS_16_Plot en béton armé coulé sur place 400 (22)
In: FOND 00 (0)
Type - PredefinedType: FLOOR; Material: BS_16_Plot en béton armé coulé sur place
PredefinedType: BASESLAB; Classification: 17. PIEUX (https://www.csiresources.org/standards/uniformat)
Pset_XX_AsBuilt - Catégorie: Fondations; Classification BBsfB: 17.; Numéro d'article du CCTB: 12.32.1a.01; Fournisseur/Installateur: De Graeve; Famille: BS_17_SFO_UN_Plot rectangulaire; Niveau: FOND 00 (0); Durée de garantie (mois): 0; Périodicité de contrôle (mois): 0
Pset_xx_Fondations - Résistance au feu: RF60; Construction: Coulé; Taux de ferraillage (kg/m³): 140
Name (BS_17_SFO_UN_Plot rectangulaire:...) | Type | Identifiant
B.A. 300x250x40cm:1563273 | B.A. 300x250x40cm | 11
B.A. 300x250x40cm:1563332 | B.A. 300x250x40cm | 12
B.A. 300x250x40cm:1563342 | B.A. 300x250x40cm | 13
B.A. 485x360x40cm:1564056 | B.A. 485x360x40cm | 29
B.A. 380x300x40cm:1564351 | B.A. 380x300x40cm | 31
B.A. 340x260x40cm:1564424 | B.A. 340x260x40cm | 19
B.A. 340x260x40cm:1564433 | B.A. 340x260x40cm | 20
B.A. 340x260x40cm:1564442 | B.A. 340x260x40cm | 21
B.A. 300x300x40cm:1564537 | B.A. 300x300x40cm | 15
B.A. 300x300x40cm:1564988 | B.A. 300x300x40cm | 16
B.A. 350x350x40cm:1565168 | B.A. 350x350x40cm | 28
B.A. 340x340x40cm:1565225 | B.A. 340x340x40cm | 25
B.A. 380x300x40cm:1565266 | B.A. 380x300x40cm | 30
B.A. 340x340x40cm:1565638 | B.A. 340x340x40cm | 26
B.A. 340x340x40cm:1565736 | B.A. 340x340x40cm | 27
B.A. 380x380x40cm:1565817 | B.A. 380x380x40cm | 32
B.A. 340x340x40cm:1935872 | B.A. 340x340x40cm | 14
B.A. 340x260x40cm:1938071 | B.A. 340x260x40cm | 22
B.A. 175x125x40cm:2039855 | B.A. 175x125x40cm | 01
B.A. 340x642x40cm:2046803 | B.A. 340x642x40cm | 23
B.A. 300x300x40cm:2202918 | B.A. 300x300x40cm | 02
B.A. 300x300x40cm:2203946 | B.A. 300x300x40cm | 37

# IfcSlab: BS_16_Plot en béton armé coulé sur place 450 (6)
In: FOND 00 (0)
Type - PredefinedType: FLOOR; Material: BS_16_Plot en béton armé coulé sur place
PredefinedType: BASESLAB; Classification: 17. PIEUX (https://www.csiresources.org/standards/uniformat)
Pset_XX_AsBuilt - Catégorie: Fondations; Classification BBsfB: 17.; Numéro d'article du CCTB: 12.32.1a.01; Fournisseur/Installateur: De Graeve; Famille: BS_17_SFO_UN_Plot rectangulaire; Niveau: FOND 00 (0); Durée de garantie (mois): 0; Périodicité de contrôle (mois): 0
Pset_xx_Fondations - Résistance au feu: RF60; Construction: Coulé; Taux de ferraillage (kg/m³): 140
Name (BS_17_SFO_UN_Plot rectangulaire:...) | Type | Identifiant
B.A. 300x400x45cm:1562739 | B.A. 300x400x45cm | 18
B.A. 300x400x45cm:1562959 | B.A. 300x400x45cm | 17
B.A. 380x380x45cm:1564962 | B.A. 380x380x45cm | 33
B.A. 420x420x45cm:1565376 | B.A. 420x420x45cm | 34
B.A. 420x420x45cm:1565579 | B.A. 420x420x45cm | 35
B.A. 420x450x45cm:1566332 | B.A. 420x450x45cm | 36

# IfcSlab: BS_16_Plot en béton armé coulé sur place 500 (8)
In: FOND 00 (0)
Type - PredefinedType: FLOOR; Material: BS_16_Plot en béton armé coulé sur place
PredefinedType: BASESLAB; Classification: 17. PIEUX (https://www.csiresources.org/standards/uniformat)
Pset_XX_AsBuilt - Catégorie: Fondations; Classification BBsfB: 17.; Numéro d'article du CCTB: 12.32.1a.01; Fournisseur/Installateur: De Graeve; Famille: BS_17_SFO_UN_Plot rectangulaire; Type: B.A. 250x580x50cm; Niveau: FOND 00 (0); Durée de garantie (mois): 0; Périodicité de contrôle (mois): 0
Pset_xx_Fondations - Résistance au feu: RF60; Construction: Coulé; Taux de ferraillage (kg/m³): 140
Name (BS_17_SFO_UN_Plot rectangulaire:B.A. 250x580x50cm:...) | Identifiant
1563802 | 03
1563821 | 04
1563838 | 05
1564050 | 06
1564052 | 07
1564054 | 08
1566768 | 09
1621600 | 10

# IfcSlab: BS_16_Plot en béton maigre 0, BS_17_SFO_UN_Plot rectangulaire:B.A. 300x300x300cm (béton maigre):2202885
In: FOND 00 (0)
Type - PredefinedType: FLOOR; Material: BS_16_Plot en béton maigre
PredefinedType: BASESLAB; Classification: 17. PIEUX (https://www.csiresources.org/standards/uniformat)
Pset_XX_AsBuilt - Catégorie: Fondations; Classification BBsfB: 17.; Numéro d'article du CCTB: 11.32.1x; Fournisseur/Installateur: De Graeve; Famille: BS_17_SFO_UN_Plot rectangulaire; Type: B.A. 300x300x300cm (béton maigre); Niveau: FOND 00 (0); Durée de garantie (mois): 0; Périodicité de contrôle (mois): 0

# IfcSlab: BS_16_Plot en béton maigre 1100 (6)
In: FOND 00 (0)
Type - PredefinedType: FLOOR; Material: BS_16_Plot en béton maigre
PredefinedType: BASESLAB; Classification: 17. PIEUX (https://www.csiresources.org/standards/uniformat)
Pset_XX_AsBuilt - Catégorie: Fondations; Classification BBsfB: 17.; Numéro d'article du CCTB: 11.32.1x; Fournisseur/Installateur: De Graeve; Famille: BS_17_SFO_UN_Plot rectangulaire; Type: B.A. 250x580x110cm (béton maigre); Identifiant: -; Niveau: FOND 00 (0); Durée de garantie (mois): 0; Périodicité de contrôle (mois): 0
Name (BS_17_SFO_UN_Plot rectangulaire:B.A. 250x580x110cm (béton maigre):...)
1563775
1621908
1621917
1622232
1622241
1622250

# IfcSlab: BS_16_Plot en béton maigre 1150 (2)
In: FOND 00 (0)
Type - PredefinedType: FLOOR; Material: BS_16_Plot en béton maigre
PredefinedType: BASESLAB; Classification: 17. PIEUX (https://www.csiresources.org/standards/uniformat)
Pset_XX_AsBuilt - Catégorie: Fondations; Classification BBsfB: 17.; Numéro d'article du CCTB: 11.32.1x; Fournisseur/Installateur: De Graeve; Famille: BS_17_SFO_UN_Plot rectangulaire; Type: B.A. 300x400x115cm (béton maigre); Identifiant: -; Niveau: FOND 00 (0); Durée de garantie (mois): 0; Périodicité de contrôle (mois): 0
Name (BS_17_SFO_UN_Plot rectangulaire:B.A. 300x400x115cm (béton maigre):...)
1621960
1624485

# IfcSlab: BS_16_Plot en béton maigre 1200 (3)
In: FOND 00 (0)
Type - PredefinedType: FLOOR; Material: BS_16_Plot en béton maigre
PredefinedType: BASESLAB; Classification: 17. PIEUX (https://www.csiresources.org/standards/uniformat)
Pset_XX_AsBuilt - Catégorie: Fondations; Classification BBsfB: 17.; Numéro d'article du CCTB: 11.32.1x; Fournisseur/Installateur: De Graeve; Famille: BS_17_SFO_UN_Plot rectangulaire; Type: B.A. 300x250x120cm (béton maigre); Identifiant: -; Niveau: FOND 00 (0); Durée de garantie (mois): 0; Périodicité de contrôle (mois): 0
Name (BS_17_SFO_UN_Plot rectangulaire:B.A. 300x250x120cm (béton maigre):...)
1622011
1622078
1622087

# IfcSlab: BS_16_Plot en béton maigre 1250, BS_17_SFO_UN_Plot rectangulaire:B.A. 175x125x320cm (béton maigre):2039991
In: FOND 00 (0)
Type - PredefinedType: FLOOR; Material: BS_16_Plot en béton maigre
PredefinedType: BASESLAB; Classification: 17. PIEUX (https://www.csiresources.org/standards/uniformat)
Pset_XX_AsBuilt - Catégorie: Fondations; Classification BBsfB: 17.; Numéro d'article du CCTB: 11.32.1x; Fournisseur/Installateur: De Graeve; Famille: BS_17_SFO_UN_Plot rectangulaire; Type: B.A. 175x125x320cm (béton maigre); Niveau: FOND 00 (0); Durée de garantie (mois): 0; Périodicité de contrôle (mois): 0

# IfcSlab: BS_16_Plot en béton maigre 2000 (2)
Type - PredefinedType: FLOOR; Material: BS_16_Plot en béton maigre
PredefinedType: BASESLAB; Classification: 17. PIEUX (https://www.csiresources.org/standards/uniformat)
Pset_XX_AsBuilt - Catégorie: Fondations; Classification BBsfB: 17.; Numéro d'article du CCTB: 11.32.1x; Fournisseur/Installateur: De Graeve; Famille: BS_17_SFO_UN_Plot rectangulaire; Durée de garantie (mois): 0; Périodicité de contrôle (mois): 0
Name (BS_17_SFO_UN_Plot rectangulaire:...) | In | Type | Niveau
B.A. 340x340x200cm (béton maigre):1935874 | FOND 00 (0) | B.A. 340x340x200cm (béton maigre) | FOND 00 (0) | Pset_XX_AsBuilt - Identifiant: -
B.A. 300x300x200cm (béton maigre):2204829 | ETAGE 00 (0) | B.A. 300x300x200cm (béton maigre) | ETAGE 00 (0)

# IfcSlab: BS_16_Plot en béton maigre 2100 (2)
In: FOND 00 (0)
Type - PredefinedType: FLOOR; Material: BS_16_Plot en béton maigre
PredefinedType: BASESLAB; Classification: 17. PIEUX (https://www.csiresources.org/standards/uniformat)
Pset_XX_AsBuilt - Catégorie: Fondations; Classification BBsfB: 17.; Numéro d'article du CCTB: 11.32.1x; Fournisseur/Installateur: De Graeve; Famille: BS_17_SFO_UN_Plot rectangulaire; Type: B.A. 250x580x210cm (béton maigre); Identifiant: -; Niveau: FOND 00 (0); Durée de garantie (mois): 0; Périodicité de contrôle (mois): 0
Name (BS_17_SFO_UN_Plot rectangulaire:B.A. 250x580x210cm (béton maigre):...)
1621926
1622259

# IfcSlab: BS_16_Plot en béton maigre 2150 (2)
In: FOND 00 (0)
Type - PredefinedType: FLOOR; Material: BS_16_Plot en béton maigre
PredefinedType: BASESLAB; Classification: 17. PIEUX (https://www.csiresources.org/standards/uniformat)
Pset_XX_AsBuilt - Catégorie: Fondations; Classification BBsfB: 17.; Numéro d'article du CCTB: 11.32.1x; Fournisseur/Installateur: De Graeve; Famille: BS_17_SFO_UN_Plot rectangulaire; Identifiant: -; Niveau: FOND 00 (0); Durée de garantie (mois): 0; Périodicité de contrôle (mois): 0
Name (BS_17_SFO_UN_Plot rectangulaire:...) | Type
B.A. 420x450x215cm (béton maigre):1622631 | B.A. 420x450x215cm (béton maigre)
B.A. 380x380x215cm (béton maigre):1622692 | B.A. 380x380x215cm (béton maigre)

# IfcSlab: BS_16_Plot en béton maigre 2200 (12)
In: FOND 00 (0)
Type - PredefinedType: FLOOR; Material: BS_16_Plot en béton maigre
PredefinedType: BASESLAB; Classification: 17. PIEUX (https://www.csiresources.org/standards/uniformat)
Pset_XX_AsBuilt - Catégorie: Fondations; Classification BBsfB: 17.; Numéro d'article du CCTB: 11.32.1x; Fournisseur/Installateur: De Graeve; Famille: BS_17_SFO_UN_Plot rectangulaire; Identifiant: -; Niveau: FOND 00 (0); Durée de garantie (mois): 0; Périodicité de contrôle (mois): 0
Name (BS_17_SFO_UN_Plot rectangulaire:...) | Type
B.A. 380x300x220cm (béton maigre):1622472 | B.A. 380x300x220cm (béton maigre)
B.A. 380x300x220cm (béton maigre):1622570 | B.A. 380x300x220cm (béton maigre)
B.A. 300x300x220cm (béton maigre):1622824 | B.A. 300x300x220cm (béton maigre)
B.A. 300x300x220cm (béton maigre):1622860 | B.A. 300x300x220cm (béton maigre)
B.A. 380x380x220cm (béton maigre):1622901 | B.A. 380x380x220cm (béton maigre)
B.A. 350x350x220cm (béton maigre):1622973 | B.A. 350x350x220cm (béton maigre)
B.A. 340x382x220cm (béton maigre):1623102 | B.A. 340x382x220cm (béton maigre)
B.A. 340x260x220cm (béton maigre):1623152 | B.A. 340x260x220cm (béton maigre)
B.A. 340x260x220cm (béton maigre):1623212 | B.A. 340x260x220cm (béton maigre)
B.A. 340x260x220cm (béton maigre):1623237 | B.A. 340x260x220cm (béton maigre)
B.A. 340x260x220cm (béton maigre):1623246 | B.A. 340x260x220cm (béton maigre)
B.A. 340x260x220cm (béton maigre):1938239 | B.A. 340x260x220cm (béton maigre)

# IfcSlab: BS_16_Plot en béton maigre 3150 (2)
In: FOND 00 (0)
Type - PredefinedType: FLOOR; Material: BS_16_Plot en béton maigre
PredefinedType: BASESLAB; Classification: 17. PIEUX (https://www.csiresources.org/standards/uniformat)
Pset_XX_AsBuilt - Catégorie: Fondations; Classification BBsfB: 17.; Numéro d'article du CCTB: 11.32.1x; Fournisseur/Installateur: De Graeve; Famille: BS_17_SFO_UN_Plot rectangulaire; Type: B.A. 420x420x315cm (béton maigre); Identifiant: -; Niveau: FOND 00 (0); Durée de garantie (mois): 0; Périodicité de contrôle (mois): 0
Name (BS_17_SFO_UN_Plot rectangulaire:B.A. 420x420x315cm (béton maigre):...)
1622396
1622548

# IfcSlab: BS_16_Plot en béton maigre 3200 (4)
In: FOND 00 (0)
Type - PredefinedType: FLOOR; Material: BS_16_Plot en béton maigre
PredefinedType: BASESLAB; Classification: 17. PIEUX (https://www.csiresources.org/standards/uniformat)
Pset_XX_AsBuilt - Catégorie: Fondations; Classification BBsfB: 17.; Numéro d'article du CCTB: 11.32.1x; Fournisseur/Installateur: De Graeve; Famille: BS_17_SFO_UN_Plot rectangulaire; Identifiant: -; Niveau: FOND 00 (0); Durée de garantie (mois): 0; Périodicité de contrôle (mois): 0
Name (BS_17_SFO_UN_Plot rectangulaire:...) | Type
B.A. 360x360x320cm (béton maigre):1622299 | B.A. 360x360x320cm (béton maigre)
B.A. 340x340x320cm (béton maigre):1623020 | B.A. 340x340x320cm (béton maigre)
B.A. 340x340x320cm (béton maigre):1623262 | B.A. 340x340x320cm (béton maigre)
B.A. 340x340x320cm (béton maigre):1623293 | B.A. 340x340x320cm (béton maigre)

# IfcSlab: BS_27_RO_Isolant toiture PIR:BS_27_RO_Isolant toiture PIR, BS_27_RO_Isolant toiture PIR:BS_27_RO_Isolant toiture PIR:2187767:1
In: ETAGE 10 (1)
PredefinedType: ROOF; Classification: 27. TOITURES (https://www.csiresources.org/standards/uniformat)
Pset_XX_AsBuilt - Catégorie: Toits; Classification BBsfB: 27.; Numéro d'article du CCTB: Isolant : 34.017.03 / Pare-vapeur : 34.24; Fabricant: Isolant : IKO / Pare-vapeur : SOPREMA; Fournisseur/Installateur: Reno-Tech; Famille: BS_27_RO_Isolant toiture PIR; Type: BS_27_RO_Isolant toiture PIR; Durée de garantie (mois): 0; Périodicité de contrôle (mois): 0; Référence FT**: Isolant : F-T_005 / Pare-vapeur : F-T_006; Modèle: Isolant : Enetherm alu / Pare-vapeur : SOPRAVAP STICK C15
Pset_XX_Isolant thermique du toit - Réaction au feu: Classe B-s2,d0; Fonction: Intérieur

# IfcSlab: BS_47_RO_Etanchéité acrotère 3 bureaux:BS_47_RO_Etanchéité acrotère 3 bureaux, BS_47_RO_Etanchéité acrotère 3 bureaux:BS_47_RO_Etanchéité acrotère 3 bureaux:3796049:1
In: ETAGE 10 (1)
PredefinedType: ROOF; Classification: 47.71 TOITURES-TERRASSES, ETANCHEITE ET ISOLATION (https://www.csiresources.org/standards/uniformat)
Pset_XX_AsBuilt - Catégorie: Toits; Classification BBsfB: 47.71; Numéro d'article du CCTB: 35.30.02; Fabricant: Flag; Fournisseur/Installateur: Reno-Tech; Famille: BS_47_RO_Etanchéité acrotère 3 bureaux; Type: BS_47_RO_Etanchéité acrotère 3 bureaux; Référence FT**: F-T_004; Modèle: Flagon EP/PR DE
Pset_XX_Remontée étanchéité - Réaction au feu: Classe E

# IfcSlab: BS_47_RO_Etanchéité acrotère 3 hall:BS_47_RO_Etanchéité acrotère hall 2, BS_47_RO_Etanchéité acrotère 3 hall:BS_47_RO_Etanchéité acrotère hall 2:3791719:1
In: ETAGE 20 (2)
PredefinedType: ROOF; Classification: 47.71 TOITURES-TERRASSES, ETANCHEITE ET ISOLATION (https://www.csiresources.org/standards/uniformat)
Pset_XX_AsBuilt - Catégorie: Toits; Classification BBsfB: 47.71; Numéro d'article du CCTB: 35.30.02; Fabricant: Flag; Fournisseur/Installateur: Reno-Tech; Famille: BS_47_RO_Etanchéité acrotère 3 hall; Type: BS_47_RO_Etanchéité acrotère hall 2; Référence FT**: F-T_004; Modèle: Flagon EP/PR DE
Pset_XX_Remontée étanchéité - Réaction au feu: Classe E

# IfcSlab: BS_47_RO_Etanchéité acrotère 3 technology:BS_47_RO_Etanchéité acrotère 3 technology, BS_47_RO_Etanchéité acrotère 3 technology:BS_47_RO_Etanchéité acrotère 3 technology:3794097:1
In: ETAGE 10 (1)
PredefinedType: ROOF; Classification: 47.71 TOITURES-TERRASSES, ETANCHEITE ET ISOLATION (https://www.csiresources.org/standards/uniformat)
Pset_XX_AsBuilt - Catégorie: Toits; Classification BBsfB: 47.71; Numéro d'article du CCTB: 35.30.02; Fabricant: Flag; Fournisseur/Installateur: Reno-Tech; Famille: BS_47_RO_Etanchéité acrotère 3 technology; Type: BS_47_RO_Etanchéité acrotère 3 technology; Référence FT**: F-T_004; Modèle: Flagon EP/PR DE
Pset_XX_Remontée étanchéité - Réaction au feu: Classe E

# IfcSlab: BS_47_RO_Etanchéité acrotère 4 hall:BS_47_RO_Etanchéité acrotère 3, BS_47_RO_Etanchéité acrotère 4 hall:BS_47_RO_Etanchéité acrotère 3:3792363:1
In: ETAGE 20 (2)
PredefinedType: ROOF; Classification: 47.71 TOITURES-TERRASSES, ETANCHEITE ET ISOLATION (https://www.csiresources.org/standards/uniformat)
Pset_XX_AsBuilt - Catégorie: Toits; Classification BBsfB: 47.71; Numéro d'article du CCTB: 35.30.02; Fabricant: Flag; Fournisseur/Installateur: Reno-Tech; Famille: BS_47_RO_Etanchéité acrotère 4 hall; Type: BS_47_RO_Etanchéité acrotère 3; Référence FT**: F-T_004; Modèle: Flagon EP/PR DE
Pset_XX_Remontée étanchéité - Réaction au feu: Classe E

# IfcSlab: Remblai 1:Remblai 1, Remblai 1:Remblai 1:2127736
In: FOND 00 (0)
PredefinedType: FLOOR
Pset_XX_AsBuilt - Catégorie: Sols; Numéro d'article du CCTB: -; Famille: Remblai 1; Type: Remblai 1; Niveau: FOND 00 (0); Durée de garantie (mois): 0; Périodicité de contrôle (mois): 0

# IfcSlab: Sol:BS_13_FL_BTbordure en beton (3)
In: ETAGE 00 (0)
Type - PredefinedType: FLOOR; Material: 21_Bordure_BetonPrefabrique_500
Classification: 13. COUCHES SUR SOL, PLANCHERS SUR SOL (https://www.csiresources.org/standards/uniformat)
Pset_XX_AsBuilt - Catégorie: Sols; Classification BBsfB: 13.; Famille: Sol; Type: BS_13_FL_BTbordure en beton; Niveau: ETAGE 00 (0); Durée de garantie (mois): 0; Périodicité de contrôle (mois): 0
Name (Sol:BS_13_FL_BTbordure en beton:...)
3616622
3616622:2
3617128

# IfcSlab: Sol:BS_13_FL_BTcoulé200, Sol:BS_13_FL_BTcoulé200:1497587
In: ETAGE 00 (0)
PredefinedType: FLOOR; Classification: 13. COUCHES SUR SOL, PLANCHERS SUR SOL (https://www.csiresources.org/standards/uniformat)
Pset_XX_AsBuilt - Catégorie: Sols; Classification BBsfB: 13.; Numéro d'article du CCTB: 12.41.1b.03; Fournisseur/Installateur: De Graeve; Famille: Sol; Type: BS_13_FL_BTcoulé200; Identifiant: P.0.04; Niveau: GO 00 (0); Durée de garantie (mois): 0; Périodicité de contrôle (mois): 0
Pset_XX_Dalle de sol - Fonction: Intérieur; Construction: Coulé sur place; Résistance au feu: RF60; Surcharge admissible (kN/m²): 10; Taux de ferraillage (kg/m³): 90; Structure: yes

# IfcSlab: Sol:BS_13_FL_BTcoulé200 (7)
In: ETAGE 00 (0)
Type - PredefinedType: FLOOR; Material: BS_13_Ossature en béton armé - Eléments coulé sur place
Classification: 13. COUCHES SUR SOL, PLANCHERS SUR SOL (https://www.csiresources.org/standards/uniformat)
Pset_XX_AsBuilt - Catégorie: Sols; Classification BBsfB: 13.; Numéro d'article du CCTB: 12.41.1b.03; Fournisseur/Installateur: De Graeve; Famille: Sol; Type: BS_13_FL_BTcoulé200; Durée de garantie (mois): 0; Périodicité de contrôle (mois): 0
Pset_XX_Dalle de sol - Fonction: Intérieur; Construction: Coulé sur place; Résistance au feu: RF60; Taux de ferraillage (kg/m³): 90; Structure: yes
Name (Sol:BS_13_FL_BTcoulé200:...) | Identifiant | Niveau | Surcharge admissible (kN/m²)
1299259 | P.0.01 | GO 00 (0) | 10
1299615 | P.0.02 | GO 00 (0) | 10
1582823 | P.0.10 | GO 00 (0) | 5
1702368 | P.0.15 | GO 00 (0) | 5
3100534 |  | GO 00 (0) | 10
3101531 |  | GO 00 (0) | 10
3101624 |  | ETAGE 00 (0) | 10

# IfcSlab: Sol:BS_13_FL_BTcoulé250, Sol:BS_13_FL_BTcoulé250:1528337
In: ETAGE 00 (0)
Classification: 13. COUCHES SUR SOL, PLANCHERS SUR SOL (https://www.csiresources.org/standards/uniformat)
Pset_XX_AsBuilt - Catégorie: Sols; Classification BBsfB: 13.; Numéro d'article du CCTB: 12.41.1a.03; Fournisseur/Installateur: De Graeve; Famille: Sol; Type: BS_13_FL_BTcoulé250; Identifiant: P.0.06; Niveau: GO 00 (0); Durée de garantie (mois): 0; Périodicité de contrôle (mois): 0
Pset_XX_Dalle de sol - Fonction: Intérieur; Construction: Coulé sur place; Résistance au feu: RF60; Surcharge admissible (kN/m²): 50; Taux de ferraillage (kg/m³): 95; Structure: yes

# IfcSlab: Sol:BS_13_FL_BTcoulé250 (12)
In: ETAGE 00 (0)
Type - PredefinedType: FLOOR; Material: BS_13_Ossature en béton armé - Eléments coulé sur place
Classification: 13. COUCHES SUR SOL, PLANCHERS SUR SOL (https://www.csiresources.org/standards/uniformat)
Pset_XX_AsBuilt - Catégorie: Sols; Classification BBsfB: 13.; Numéro d'article du CCTB: 12.41.1a.03; Fournisseur/Installateur: De Graeve; Famille: Sol; Type: BS_13_FL_BTcoulé250; Niveau: GO 00 (0); Durée de garantie (mois): 0; Périodicité de contrôle (mois): 0
Pset_XX_Dalle de sol - Fonction: Intérieur; Construction: Coulé sur place; Résistance au feu: RF60; Surcharge admissible (kN/m²): 50; Taux de ferraillage (kg/m³): 95; Structure: yes
Name (Sol:BS_13_FL_BTcoulé250:...) | Identifiant
10 x 1528337 | P.0.06
1581426 | P.0.08
1974090

# IfcSlab: Sol:BS_13_FL_BTcoulé280, Sol:BS_13_FL_BTcoulé280:1584566
In: ETAGE 00 (0)
Type - PredefinedType: FLOOR; Material: BS_13_Ossature en béton armé - Eléments coulé sur place
Classification: 13. COUCHES SUR SOL, PLANCHERS SUR SOL (https://www.csiresources.org/standards/uniformat)
Pset_XX_AsBuilt - Catégorie: Sols; Classification BBsfB: 13.; Numéro d'article du CCTB: 12.41.1b.01; Fournisseur/Installateur: De Graeve; Famille: Sol; Type: BS_13_FL_BTcoulé280; Identifiant: P.0.12; Niveau: GO 00 (0); Durée de garantie (mois): 0; Périodicité de contrôle (mois): 0
Pset_XX_Dalle de sol - Fonction: Intérieur; Construction: Coulé sur place; Résistance au feu: RF60; Surcharge admissible (kN/m²): 50; Taux de ferraillage (kg/m³): 95; Structure: yes

# IfcSlab: Sol:BS_13_FL_BTcoulé500 exterieur 500 (2)
In: ETAGE 00 (0)
Type - PredefinedType: FLOOR; Material: BS_92_Klinker 200 mm, BS_13_Sable stabilisé 150 mm, BS_13_Empierrement sous dalle 150 mm
Classification: 13. COUCHES SUR SOL, PLANCHERS SUR SOL (https://www.csiresources.org/standards/uniformat)
Pset_XX_AsBuilt - Catégorie: Sols; Classification BBsfB: 13.; Famille: Sol; Type: BS_13_FL_BTcoulé500 exterieur; Niveau: GO 00 (0); Durée de garantie (mois): 0; Périodicité de contrôle (mois): 0
Name (Sol:BS_13_FL_BTcoulé500 exterieur:...)
3612897
3615348

# IfcSlab: Sol:BS_13_FL_STAB50-EMPI250 (4)
In: ETAGE 00 (0)
PredefinedType: FLOOR; Classification: 13. COUCHES SUR SOL, PLANCHERS SUR SOL (https://www.csiresources.org/standards/uniformat)
Pset_XX_AsBuilt - Catégorie: Sols; Classification BBsfB: 13.; Numéro d'article du CCTB: 12.1; Famille: Sol; Type: BS_13_FL_STAB50-EMPI250; Durée de garantie (mois): 0; Périodicité de contrôle (mois): 0
Name (Sol:BS_13_FL_STAB50-EMPI250:...) | Identifiant | Niveau
1497924 | P.0.05 | GO 00 (0)
1528401 | P.0.07 | GO 00 (0)
1591935 | P.0.14 | GO 00 (0)
1977083 |  | ETAGE 00 (0)

# IfcSlab: Sol:BS_13_FL_STAB50-EMPI250 2 300 (4)
In: ETAGE 00 (0)
Type - PredefinedType: FLOOR; Material: BS_13_Sable stabilisé 50 mm, BS_13_Empierrement sous dalle 250 mm
Classification: 13. COUCHES SUR SOL, PLANCHERS SUR SOL (https://www.csiresources.org/standards/uniformat)
Pset_XX_AsBuilt - Catégorie: Sols; Classification BBsfB: 13.; Numéro d'article du CCTB: 12.1; Famille: Sol; Niveau: GO 00 (0); Durée de garantie (mois): 0; Périodicité de contrôle (mois): 0
Name (Sol:...) | Type | Identifiant
BS_13_FL_STAB50-EMPI250 2:1340380 | BS_13_FL_STAB50-EMPI250 2 | P.0.03
BS_13_FL_STAB50-EMPI250:1582682 | BS_13_FL_STAB50-EMPI250 | P.0.09
BS_13_FL_STAB50-EMPI250:1582962 | BS_13_FL_STAB50-EMPI250 | P.0.11
BS_13_FL_STAB50-EMPI250:1704663 | BS_13_FL_STAB50-EMPI250 | P.0.16

# IfcSlab: Sol:BS_13_FL_STAB50-EMPI250_EpVar, Sol:BS_13_FL_STAB50-EMPI250_EpVar:3106317
In: ETAGE 00 (0)
PredefinedType: FLOOR; Classification: 13. COUCHES SUR SOL, PLANCHERS SUR SOL (https://www.csiresources.org/standards/uniformat)
Pset_XX_AsBuilt - Catégorie: Sols; Classification BBsfB: 13.; Numéro d'article du CCTB: 12.1; Famille: Sol; Type: BS_13_FL_STAB50-EMPI250_EpVar; Niveau: GO 00 (0); Durée de garantie (mois): 0; Périodicité de contrôle (mois): 0

# IfcSlab: Sol:BS_23_FL_BTcoulé270 (2)
In: ETAGE 00 (0)
Type - PredefinedType: FLOOR; Material: BS_28_Ossature en béton armé - Eléments coulé sur place
Classification: 23.31 PLANCHERS EN BETON COULE SUR PLACE (https://www.csiresources.org/standards/uniformat)
Pset_XX_AsBuilt - Catégorie: Sols; Classification BBsfB: 23.31; Numéro d'article du CCTB: 22.15.1; Fournisseur/Installateur: De Graeve; Famille: Sol; Type: BS_23_FL_BTcoulé270; Niveau: GO 10 (1)
Pset_XX_Dalle hors sol - Fonction: Intérieur; Construction: Coulé sur place; Structure: yes; Surcharge admissible (kN/m²): 3; Résistance au feu: RF60; Taux de ferraillage (kg/m³): 100
Name (Sol:BS_23_FL_BTcoulé270:...) | Identifiant
1781658 | Salle BIM | Pset_XX_AsBuilt - Durée de garantie (mois): 0; Périodicité de contrôle (mois): 0
3688214 | Palier escalier

# IfcSlab: Sol:BS_23_FL_BTcoulé70 (5)
In: ETAGE 00 (0)
Type - PredefinedType: FLOOR; Material: BS_28_Ossature en béton armé - Eléments coulé sur place
Classification: 23. PLANCHERS (https://www.csiresources.org/standards/uniformat)
Pset_XX_AsBuilt - Catégorie: Sols; Classification BBsfB: 23.; Numéro d'article du CCTB: 22.15.3d; Fournisseur/Installateur: De Graeve; Famille: Sol; Type: BS_23_FL_BTcoulé70; Niveau: GO 10 (1)
Pset_xx_Chape de compression - Structure: yes; Résistance au feu: RF60; Taux de ferraillage (kg/m³): 42; Construction: Coulé
Name (Sol:BS_23_FL_BTcoulé70:...) | Identifiant | Surcharge admissible (kN/m²)
3684876 | Bureaux | 3
3685154 | Locaux techniques | 5
3685335 | Salle BIM | 3
3685513 | Local électricité | 5
3685594 | Technology room | 3

# IfcSlab: Sol:BS_23_FL_BTremplissage chape de compression (21)
In: ETAGE 00 (0)
Type - PredefinedType: FLOOR; Material: BS_28_Ossature en béton armé - Eléments coulé sur place
Classification: 23. PLANCHERS (https://www.csiresources.org/standards/uniformat)
Pset_XX_AsBuilt - Catégorie: Sols; Classification BBsfB: 23.; Numéro d'article du CCTB: 22.15.3d; Fournisseur/Installateur: De Graeve; Famille: Sol; Type: BS_23_FL_BTremplissage chape de compression; Identifiant: Remplissage; Niveau: GO 10 (1)
Pset_xx_Chape de compression - Structure: yes; Résistance au feu: RF60; Construction: Coulé
Name (Sol:BS_23_FL_BTremplissage chape de compression:...)
3686161
3686161:2
3686161:3
3686161:4
3686161:5
3686161:6
3686161:7
3686161:8
3686161:9
3686161:10
3686161:11
3686161:12
3686161:13
3686161:14
3686161:15
3686161:16
3686161:17
3686161:18
3686161:19
3686161:20
3686161:21

# IfcSlab: Sol:BS_43_FL_CHlissée100 (3)
In: ETAGE 10 (1)
Type - PredefinedType: FLOOR; Material: BS_43_Chape
Classification: 23. PLANCHERS (https://www.csiresources.org/standards/uniformat)
Pset_XX_AsBuilt - Catégorie: Sols; Classification BBsfB: 23.; Numéro d'article du CCTB: 52.71; Fournisseur/Installateur: De Graeve; Famille: Sol; Type: BS_43_FL_CHlissée100; Niveau: ETAGE 10 (1)
Pset_xx_Chape - Taux de ferraillage (kg/m³): 45,25; Structure: yes; Résistance au feu: RF60; Construction: Coulé
Name (Sol:BS_43_FL_CHlissée100:...) | Identifiant | Durée de garantie (mois) = Périodicité de contrôle (mois) | Surcharge admissible (kN/m²)
1522460 | Bureaux | 0 | 3
1721785 | Locaux techniques | 0 | 5
3684544 | Local électricité |  | 5

# IfcSlab: Sol:BS_43_FL_CHlissée130, Sol:BS_43_FL_CHlissée130:3788494
In: ETAGE 10 (1)
Type - PredefinedType: FLOOR; Material: BS_43_Chape
Classification: 23. PLANCHERS (https://www.csiresources.org/standards/uniformat)
Pset_XX_AsBuilt - Catégorie: Sols; Classification BBsfB: 23.; Numéro d'article du CCTB: 52.71; Fournisseur/Installateur: De Graeve; Famille: Sol; Type: BS_43_FL_CHlissée130; Identifiant: Palier escalier secours; Niveau: ETAGE 10 (1)
Pset_xx_Chape - Taux de ferraillage (kg/m³): 45,25; Structure: yes; Résistance au feu: RF60; Surcharge admissible (kN/m²): 3; Construction: Coulé

# IfcSlab: Sol:BS_43_FL_CHsèche acoustique45 45, Sol:BS_43_FL_CHsèche acoustique45:3683763
In: ETAGE 10 (1)
Type - PredefinedType: FLOOR; Material: BS_43_Plaques fibres-gypse (Fermacell) 25 mm, BS_43_Laine minérale 20 mm
Classification: 23. PLANCHERS (https://www.csiresources.org/standards/uniformat)
Pset_XX_AsBuilt - Catégorie: Sols; Classification BBsfB: 23.; Numéro d'article du CCTB: 52.64; Fournisseur/Installateur: De Graeve; Famille: Sol; Type: BS_43_FL_CHsèche acoustique45; Identifiant: Salle BIM; Niveau: GO 20 (2); Durée de garantie (mois): 0; Périodicité de contrôle (mois): 0; Référence FT**: F-T_036
Pset_xx_Chape - Taux de ferraillage (kg/m³): 0; Structure: yes; Résistance au feu: RF60; Surcharge admissible (kN/m²): 0

# IfcSlab: Sol:BS_43_FL_CHsèche98-Lino2 100, Sol:BS_43_FL_CHsèche98-Lino2:3684019
In: ETAGE 10 (1)
Type - PredefinedType: FLOOR; Material: BS_43_Revêtement de sol souple 2 mm, BS_43_Chape 98 mm
Classification: 23. PLANCHERS (https://www.csiresources.org/standards/uniformat)
Pset_XX_AsBuilt - Catégorie: Sols; Classification BBsfB: 23.; Numéro d'article du CCTB: 52.51; Fournisseur/Installateur: De Graeve; Famille: Sol; Type: BS_43_FL_CHsèche98-Lino2; Identifiant: Technology room; Niveau: ETAGE 10 (1)
Pset_xx_Chape - Taux de ferraillage (kg/m³): 45,25; Structure: yes; Résistance au feu: RF60; Surcharge admissible (kN/m²): 3; Construction: Coulé

# IfcSlab: Sol:BS_43_FL_REV10-OSB18-ISOacou16-SUPP 100, Sol:BS_43_FL_REV10-OSB18-ISOacou16-SUPP:1519029
In: ETAGE 10 (1)
Type - PredefinedType: FLOOR; Material: BS_43_Revêtement de sol souple 10 mm, BS_43_Panneau OSB 18 mm, BS_43_Acoustix Pan-Terre 16 mm, BS_43_Laine minérale 56 mm
Classification: 23. PLANCHERS (https://www.csiresources.org/standards/uniformat)
Pset_XX_AsBuilt - Catégorie: Sols; Classification BBsfB: 23.; Numéro d'article du CCTB: 52.46; Fournisseur/Installateur: De Graeve; Famille: Sol; Type: BS_43_FL_REV10-OSB18-ISOacou16-SUPP; Identifiant: Salle BIM; Niveau: ETAGE 10 (1); Durée de garantie (mois): 0; Périodicité de contrôle (mois): 0; Référence FT**: F-T_007
Pset_xx_Chape - Taux de ferraillage (kg/m³): 0; Structure: yes; Résistance au feu: RF60; Surcharge admissible (kN/m²): 0

# IfcSlab: Sol:DG_23_FL_SocleEquipement100mm (3)
In: ETAGE 10 (1)
Type - PredefinedType: FLOOR; Material: BS_28_Ossature en béton armé - Eléments coulé sur place
Classification: 23. PLANCHERS (https://www.csiresources.org/standards/uniformat)
Pset_XX_AsBuilt - Catégorie: Sols; Classification BBsfB: 23.; Numéro d'article du CCTB: 22.22.2b; Famille: Sol; Type: DG_23_FL_SocleEquipement100mm; Niveau: ETAGE 10 (1); Durée de garantie (mois): 0; Périodicité de contrôle (mois): 0
Name (Sol:DG_23_FL_SocleEquipement100mm:...)
3354992
3356005
3356860

# IfcSlab: Sol:DG_35_FL_Métal déployé, Sol:DG_35_FL_Métal déployé:3448187
In: ETAGE 10 (1)
Type - PredefinedType: FLOOR; Material: BS_41_Bardage en tôle perforé
Classification: 23. PLANCHERS (https://www.csiresources.org/standards/uniformat)
Pset_XX_AsBuilt - Catégorie: Sols; Classification BBsfB: 23.; Numéro d'article du CCTB: 22.22.2b; Famille: Sol; Type: DG_35_FL_Métal déployé; Niveau: ETAGE 10 (1); Durée de garantie (mois): 0; Périodicité de contrôle (mois): 0

# IfcSlab: Sol_BS_13_FL_STAB50-EMPI250, Sol:BS_13_FL_STAB50-EMPI250:1974598
In: ETAGE 00 (0)
PredefinedType: FLOOR; Classification: 13. COUCHES SUR SOL, PLANCHERS SUR SOL (https://www.csiresources.org/standards/uniformat)
Pset_XX_AsBuilt - Catégorie: Sols; Classification BBsfB: 13.; Numéro d'article du CCTB: 12.1; Famille: Sol; Type: BS_13_FL_STAB50-EMPI250; Niveau: ETAGE 00 (0); Durée de garantie (mois): 0; Périodicité de contrôle (mois): 0

# IfcStair: Escalier accueil:BS_24_STR_Escalier accueil (2)
In: ETAGE 00 (0)
Name (Escalier accueil:BS_24_STR_Escalier accueil:...)
3084451 | Classification: 24.42 ESCALIERS EN BETON (https://www.csiresources.org/standards/uniformat); Pset_XX_AsBuilt - Catégorie: Escalier; Classification BBsfB: 24.42; Numéro d'article du CCTB: 22.31.2; Fabricant: Delmar; Fournisseur/Installateur: De Graeve; Famille: Escalier accueil; Type: BS_24_STR_Escalier accueil; Niveau: ETAGE 00 (0); Durée de garantie (mois): 0; Périodicité de contrôle (mois): 0; Référence FT**: PLA_023; Pset_XX_Escalier intérieur - Réaction au feu: Non inflammable
3084451 | Material: BS_28_Ossature en béton armé - Eléments préfabriqués

# IfcStair: Escalier coulé sur place:BS_24_STR_Escalier menuiserie, Escalier coulé sur place:Escalier:1628013
In: ETAGE 00 (0)
PredefinedType: STRAIGHT_RUN_STAIR; Classification: 24.42 ESCALIERS EN BETON (https://www.csiresources.org/standards/uniformat)
Pset_XX_AsBuilt - Catégorie: Escalier; Classification BBsfB: 24.42; Numéro d'article du CCTB: 22.31.1; Fabricant: De Graeve; Fournisseur/Installateur: De Graeve; Famille: Escalier coulé sur place; Type: BS_24_STR_Escalier menuiserie; Identifiant: Es..1; Durée de garantie (mois): 0; Périodicité de contrôle (mois): 0
Pset_XX_Escalier intérieur - Réaction au feu: Non inflammable

# IfcStair: Escalier secours:BS_24_STR_Escalier secours (2)
In: ETAGE 00 (0)
Name (Escalier secours:BS_24_STR_Escalier secours:...)
3787614 | Classification: 24.42 ESCALIERS EN BETON (https://www.csiresources.org/standards/uniformat); Pset_XX_AsBuilt - Catégorie: Escalier; Classification BBsfB: 24.42; Numéro d'article du CCTB: 22.31.2; Fabricant: Delmar; Fournisseur/Installateur: De Graeve; Famille: Escalier secours; Type: BS_24_STR_Escalier secours; Niveau: ETAGE 00 (0); Référence FT**: PLA_024; Pset_XX_Escalier intérieur - Réaction au feu: Non inflammable
3787614 | Material: BS_28_Ossature en béton armé - Eléments préfabriqués

# IfcStairFlight: Volée monobloc:BS_24_STR_Volée monobloc, Escalier coulé sur place:Escalier:1628013 Run 1
In: ETAGE 00 (0)
NumberOfTreads: 2; RiserHeight: 0.546807 mm; TreadLength: 0.82021 mm; Classification: 24.42 ESCALIERS EN BETON (https://www.csiresources.org/standards/uniformat)
Pset_XX_AsBuilt - Catégorie: Escalier: Volées; Classification BBsfB: 24.; Famille: Volée monobloc; Type: BS_24_STR_Volée monobloc

# IfcWall: BS_16_Isolation des murs extérieurs 80, DG_JonctionMursRideau:DG_JonctionMursRideau:3089351
In: ETAGE 00 (0)
Type - Material: BS_16_Isolation des murs extérieurs
Pset_XX_AsBuilt - Catégorie: Murs; Famille: DG_JonctionMursRideau; Type: DG_JonctionMursRideau; Durée de garantie (mois): 0; Périodicité de contrôle (mois): 0

# IfcWall: Mur de base:BS_13_WA_XPS80 (6)
In: FOND 00 (0)
Classification: 13. COUCHES SUR SOL, PLANCHERS SUR SOL (https://www.csiresources.org/standards/uniformat)
Pset_XX_AsBuilt - Catégorie: Murs; Classification BBsfB: 13.; Numéro d'article du CCTB: 16.12; Fabricant: SOPREMA; Fournisseur/Installateur: De Graeve; Famille: Mur de base; Type: BS_13_WA_XPS80; Durée de garantie (mois): 0; Périodicité de contrôle (mois): 0; Référence FT**: F-T_001; Modèle: SOPRA XPS SL
Name (Mur de base:BS_13_WA_XPS80:...)
2130647
2131220
2131481
2131872
2132282
2132698

# IfcWall: Mur de base:BS_13_WA_XPS80 (18)
Type - Material: BS_13_Isolation sur sols XPS
Classification: 13. COUCHES SUR SOL, PLANCHERS SUR SOL (https://www.csiresources.org/standards/uniformat)
Pset_XX_AsBuilt - Catégorie: Murs; Classification BBsfB: 13.; Numéro d'article du CCTB: 16.12; Fabricant: SOPREMA; Fournisseur/Installateur: De Graeve; Famille: Mur de base; Type: BS_13_WA_XPS80; Durée de garantie (mois): 0; Périodicité de contrôle (mois): 0; Référence FT**: F-T_001; Modèle: SOPRA XPS SL
Name (Mur de base:BS_13_WA_XPS80:...) | In
2127376 | FOND 00 (0)
2127582 | FOND 00 (0)
2128060 | FOND 00 (0)
2128276 | FOND 00 (0)
2128324 | FOND 00 (0)
2128369 | FOND 00 (0)
2128849 | FOND 00 (0)
2128962 | FOND 00 (0)
2129415 | FOND 00 (0)
2129816 | FOND 00 (0)
2130133 | FOND 00 (0)
2130414 | FOND 00 (0)
2132915 | FOND 00 (0)
2133096 | FOND 00 (0)
2126530 | ETAGE 00 (0)
2133463 | ETAGE 00 (0)
2203252 | ETAGE 00 (0)
2203588 | ETAGE 00 (0)

# IfcWall: Mur de base:BS_21_WA_BTpréfab90-ISO100-BTlissépréfab60, Mur de base:BS_21_WA_BTpréfab90-ISO100-BTlissépréfab60:2056228
In: FOND 00 (0)
Classification: 21. MURS EXTERIEURS (https://www.csiresources.org/standards/uniformat)
Pset_XX_AsBuilt - Catégorie: Murs; Classification BBsfB: 21.; Numéro d'article du CCTB: 26.21.01; Fabricant: SCHELFHOUT; Fournisseur/Installateur: De Graeve; Famille: Mur de base; Type: BS_21_WA_BTpréfab90-ISO100-BTlissépréfab60; Identifiant: D6; Durée de garantie (mois): 0; Périodicité de contrôle (mois): 0; Modèle: SANBEK 25-10
Pset_xx_Panneaux sandwich - Résistance thermique (R): 5.25974; Fonction: Extérieur; Construction: Préfabriqué; Structure: Porteur

# IfcWall: Mur de base:BS_21_WA_BTpréfab90-ISO100-BTlissépréfab60 (porte-à-faux) 250 (2)
Type - Material: BS_28_Ossature en béton armé - Eléments préfabriqués(panneau façade) 90 mm, BS_21_Isolation des murs extérieurs 100 mm, BS_28_Ossature en béton armé - Eléments préfabriqués(panneau façade) 60 mm
Classification: 21. MURS EXTERIEURS (https://www.csiresources.org/standards/uniformat)
Pset_XX_AsBuilt - Catégorie: Murs; Classification BBsfB: 21.; Numéro d'article du CCTB: 26.21.01; Fabricant: SCHELFHOUT; Fournisseur/Installateur: De Graeve; Famille: Mur de base; Type: BS_21_WA_BTpréfab90-ISO100-BTlissépréfab60 (porte-à-faux); Durée de garantie (mois): 0; Périodicité de contrôle (mois): 0; Modèle: SANBEK 25-10
Pset_xx_Panneaux sandwich - Résistance thermique (R): 5.25974; Fonction: Extérieur; Construction: Préfabriqué; Structure: Porteur
Name (Mur de base:BS_21_WA_BTpréfab90-ISO100-BTlissépréfab60 (porte-à-faux):...) | In | Identifiant
2082442 | ETAGE 00 (0) | G20
2064607 | ETAGE 10 (1) | E5

# IfcWall: Mur de base:BS_21_WA_BTpréfab90-ISO100-BTlissépréfab60 (sous porte-à-faux) 250 (2)
In: ETAGE 00 (0)
Type - Material: BS_28_Ossature en béton armé - Eléments préfabriqués(panneau façade) 90 mm, BS_21_Isolation des murs extérieurs 100 mm, BS_28_Ossature en béton armé - Eléments préfabriqués(panneau façade) 60 mm
Classification: 21. MURS EXTERIEURS (https://www.csiresources.org/standards/uniformat)
Pset_XX_AsBuilt - Catégorie: Murs; Classification BBsfB: 21.; Numéro d'article du CCTB: 26.21.01; Fabricant: SCHELFHOUT; Fournisseur/Installateur: De Graeve; Famille: Mur de base; Type: BS_21_WA_BTpréfab90-ISO100-BTlissépréfab60 (sous porte-à-faux); Durée de garantie (mois): 0; Périodicité de contrôle (mois): 0; Modèle: SANBEK 25-10
Pset_xx_Panneaux sandwich - Résistance thermique (R): 5.25974; Fonction: Extérieur; Construction: Préfabriqué; Structure: Porteur
Name (Mur de base:BS_21_WA_BTpréfab90-ISO100-BTlissépréfab60 (sous porte-à-faux):...) | Identifiant
2061463 | F4
2061989 | F5

# IfcWall: Mur de base:BS_21_WA_BTpréfab90-ISO100-BTlissépréfab60 (toit plat arrière) (2)
In: ACROTERE (4)
Classification: 21. MURS EXTERIEURS (https://www.csiresources.org/standards/uniformat)
Pset_XX_AsBuilt - Catégorie: Murs; Classification BBsfB: 21.; Numéro d'article du CCTB: 26.21.01; Fabricant: SCHELFHOUT; Fournisseur/Installateur: De Graeve; Famille: Mur de base; Type: BS_21_WA_BTpréfab90-ISO100-BTlissépréfab60 (toit plat arrière); Durée de garantie (mois): 0; Périodicité de contrôle (mois): 0; Modèle: SANBEK 25-10
Pset_xx_Panneaux sandwich - Résistance thermique (R): 5.25974; Fonction: Extérieur; Construction: Préfabriqué; Structure: Porteur
Name (Mur de base:BS_21_WA_BTpréfab90-ISO100-BTlissépréfab60 (toit plat arrière):...) | Identifiant
2071787 | B2
2071810 | B1

# IfcWall: Mur de base:BS_21_WA_BTpréfab90-ISO100-BTlissépréfab60 (toit plat avant) (2)
In: ACROTERE (4)
Classification: 21. MURS EXTERIEURS (https://www.csiresources.org/standards/uniformat)
Pset_XX_AsBuilt - Catégorie: Murs; Classification BBsfB: 21.; Numéro d'article du CCTB: 26.21.01; Fabricant: SCHELFHOUT; Fournisseur/Installateur: De Graeve; Famille: Mur de base; Type: BS_21_WA_BTpréfab90-ISO100-BTlissépréfab60 (toit plat avant); Durée de garantie (mois): 0; Périodicité de contrôle (mois): 0; Modèle: SANBEK 25-10
Pset_xx_Panneaux sandwich - Résistance thermique (R): 5.25974; Fonction: Extérieur; Construction: Préfabriqué; Structure: Porteur
Name (Mur de base:BS_21_WA_BTpréfab90-ISO100-BTlissépréfab60 (toit plat avant):...) | Identifiant
2059643 | D14
2059667 | D15

# IfcWall: Mur de base:BS_21_WA_BTpréfab90-ISO100-BTlissépréfab60 250 (89)
Type - Material: BS_28_Ossature en béton armé - Eléments préfabriqués(panneau façade) 90 mm, BS_21_Isolation des murs extérieurs 100 mm, BS_28_Ossature en béton armé - Eléments préfabriqués(panneau façade) 60 mm
Classification: 21. MURS EXTERIEURS (https://www.csiresources.org/standards/uniformat)
Pset_XX_AsBuilt - Catégorie: Murs; Classification BBsfB: 21.; Numéro d'article du CCTB: 26.21.01; Fabricant: SCHELFHOUT; Fournisseur/Installateur: De Graeve; Famille: Mur de base; Type: BS_21_WA_BTpréfab90-ISO100-BTlissépréfab60; Durée de garantie (mois): 0; Périodicité de contrôle (mois): 0; Modèle: SANBEK 25-10
Pset_xx_Panneaux sandwich - Résistance thermique (R): 5.25974; Fonction: Extérieur; Construction: Préfabriqué; Structure: Porteur
Name (Mur de base:BS_21_WA_BTpréfab90-ISO100-BTlissépréfab60:...) | In | Identifiant
1345764 | FOND 00 (0) | B5 | Pset_xx_Panneaux sandwich - Résistance au feu: -
1346243 | FOND 00 (0) | C3 | Pset_xx_Panneaux sandwich - Résistance au feu: -
1444608 | FOND 00 (0) | D11 | Pset_xx_Panneaux sandwich - Résistance au feu: -
1461986 | FOND 00 (0) | A1 | Pset_xx_Panneaux sandwich - Résistance au feu: -
1462092 | FOND 00 (0) | E1 | Pset_xx_Panneaux sandwich - Résistance au feu: -
1497428 | FOND 00 (0) | F2 | Pset_xx_Panneaux sandwich - Résistance au feu: -
1499280 | FOND 00 (0) | G6 | Pset_xx_Panneaux sandwich - Résistance au feu: -
1981076 | FOND 00 (0) | G8 | Pset_xx_Panneaux sandwich - Résistance au feu: -
2057024 | FOND 00 (0) | D1
2057645 | FOND 00 (0) | D2
2057952 | FOND 00 (0) | D3
2058139 | FOND 00 (0) | D10
2058598 | FOND 00 (0) | D4 / D5
2061949 | FOND 00 (0) | F3
2066003 | FOND 00 (0) | C6
2066784 | FOND 00 (0) | C4
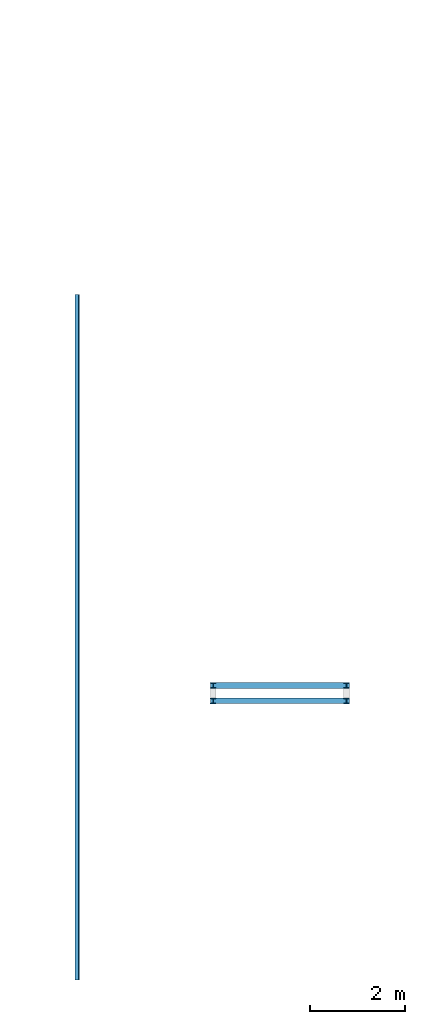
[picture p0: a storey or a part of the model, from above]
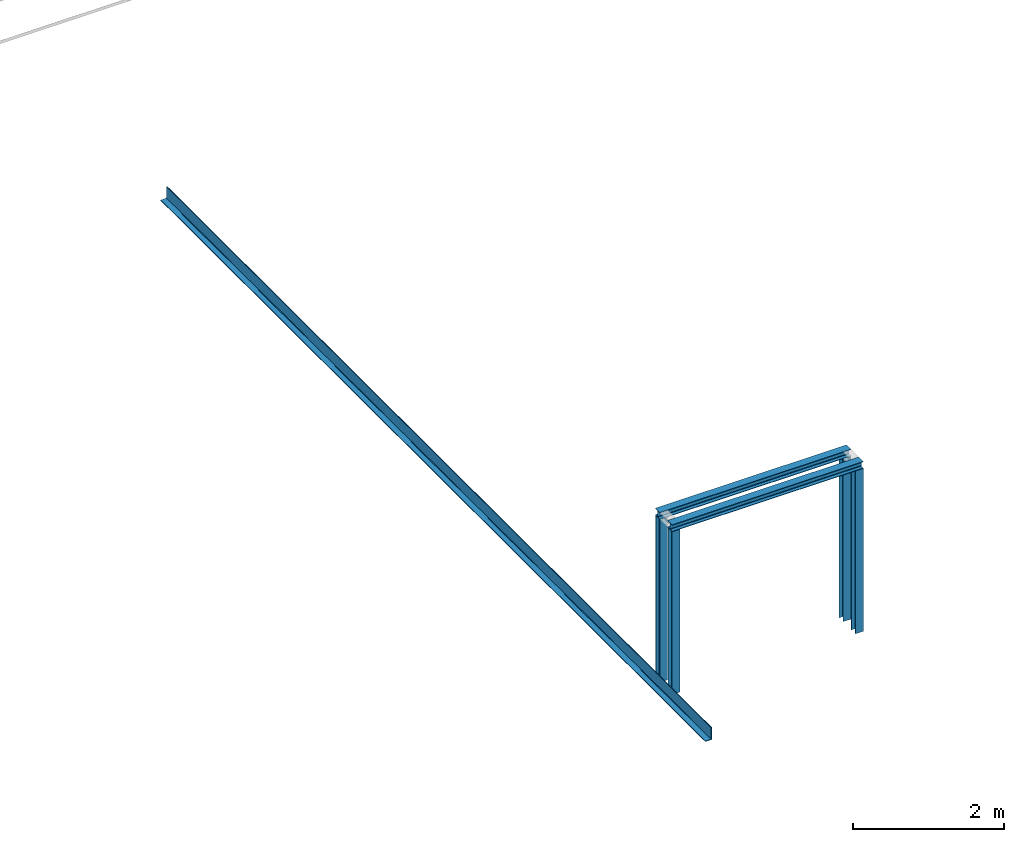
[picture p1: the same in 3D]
Properties of the parts of a building model (IFC4X3_ADD2), part 4 of 4

# IfcWall: Mur de base:BS_21_WA_BTpréfab90-ISO100-BTlissépréfab60 250 (89)
Name (Mur de base:BS_21_WA_BTpréfab90-ISO100-BTlissépréfab60:...) | In | Identifiant
2066936 | FOND 00 (0) | C5
2066955 | FOND 00 (0) | C5
2067022 | FOND 00 (0) | C1
2067060 | FOND 00 (0) | C2
2067124 | FOND 00 (0) | C2
2068965 | FOND 00 (0) | B10
2069462 | FOND 00 (0) | B9
2069655 | FOND 00 (0) | B8
2069692 | FOND 00 (0) | B7
2069850 | FOND 00 (0) | B6
2070420 | FOND 00 (0) | B11/B12
2072621 | FOND 00 (0) | H7
2074295 | FOND 00 (0) | H2
2074645 | FOND 00 (0) | H8
2074660 | FOND 00 (0) | H9
2074842 | FOND 00 (0) | G9
2075926 | FOND 00 (0) | G10
2078914 | FOND 00 (0) | G28
2079186 | FOND 00 (0) | G17
2079277 | FOND 00 (0) | G25
2079333 | FOND 00 (0) | G7
2079789 | FOND 00 (0) | G5
2080415 | FOND 00 (0) | G29
2080466 | FOND 00 (0) | G30
2080629 | FOND 00 (0) | G31
2081256 | FOND 00 (0) | G15
2081853 | FOND 00 (0) | G13
2082815 | FOND 00 (0) | G13
2083271 | FOND 00 (0) | G14
2083557 | FOND 00 (0) | G4
2083630 | FOND 00 (0) | G2
2084130 | FOND 00 (0) | G1
2091036 | FOND 00 (0) | F1 | Pset_xx_Panneaux sandwich - Résistance au feu: -
3111313 | FOND 00 (0) | A2 | Pset_xx_Panneaux sandwich - Résistance au feu: -
3840454 | FOND 00 (0) | H1 | Pset_xx_Panneaux sandwich - Résistance au feu: -
3840720 | FOND 00 (0) | H3
2056634 | ETAGE 00 (0) | D13
2058441 | ETAGE 00 (0) | D8
2058655 | ETAGE 00 (0) | D7
2058749 | ETAGE 00 (0) | D9
2058840 | ETAGE 00 (0) | D12
2066074 | ETAGE 00 (0) | C9
2066608 | ETAGE 00 (0) | C7
2066644 | ETAGE 00 (0) | C8
2066664 | ETAGE 00 (0) | C8
2067938 | ETAGE 00 (0) | A3 | Pset_xx_Panneaux sandwich - Résistance au feu: -
2068013 | ETAGE 00 (0) | A5 | Pset_xx_Panneaux sandwich - Résistance au feu: -
2068392 | ETAGE 00 (0) | A4
2068511 | ETAGE 00 (0) | A6
2069164 | ETAGE 00 (0) | B3
2070524 | ETAGE 00 (0) | B15
2070586 | ETAGE 00 (0) | B14
2070743 | ETAGE 00 (0) | B13
2071062 | ETAGE 00 (0) | B4
2074526 | ETAGE 00 (0) | H5
2075091 | ETAGE 00 (0) | G18
2075704 | ETAGE 00 (0) | G26
2076293 | ETAGE 00 (0) | G11
2078553 | ETAGE 00 (0) | G27
2078637 | ETAGE 00 (0) | G19
2080207 | ETAGE 00 (0) | G16
2080846 | ETAGE 00 (0) | G24
2081484 | ETAGE 00 (0) | G23
2081728 | ETAGE 00 (0) | G21
2082688 | ETAGE 00 (0) | G21
2083192 | ETAGE 00 (0) | G22
2083968 | ETAGE 00 (0) | G3
3838927 | ETAGE 00 (0) | H4
3839025 | ETAGE 00 (0) | H6
1462508 | ETAGE 10 (1) | G12 | Pset_xx_Panneaux sandwich - Résistance au feu: -
1708391 | ETAGE 10 (1) | E3 | Pset_xx_Panneaux sandwich - Résistance au feu: -
2053322 | ETAGE 10 (1) | E2
2065179 | ETAGE 10 (1) | E4

# IfcWall: Mur de base:BS_21_WA_ISO80, Mur de base:BS_21_WA_ISO80:1707866
In: ETAGE 10 (1)
Type - Material: BS_21_Isolation des murs extérieurs
Classification: 21. MURS EXTERIEURS (https://www.csiresources.org/standards/uniformat)
Pset_XX_AsBuilt - Catégorie: Murs; Classification BBsfB: 21.; Numéro d'article du CCTB: -; Famille: Mur de base; Type: BS_21_WA_ISO80; Identifiant: M.0.33; Durée de garantie (mois): 0; Périodicité de contrôle (mois): 0

# IfcWall: Mur de base:BS_22_WA_BBTlourd190 (4)
In: ETAGE 00 (0)
Classification: 22. MURS INTERIEURS (https://www.csiresources.org/standards/uniformat)
Pset_XX_AsBuilt - Catégorie: Murs; Classification BBsfB: 22.; Numéro d'article du CCTB: 20.24.01; Fournisseur/Installateur: De Graeve; Famille: Mur de base; Type: BS_22_WA_BBTlourd190; Durée de garantie (mois): 0; Périodicité de contrôle (mois): 0
Pset_XX_Cloisons - Résistance au feu: RF60; Structure/porteur: Non porteur
Name (Mur de base:BS_22_WA_BBTlourd190:...) | Identifiant
1329465 | M.0.08
1329628 | M.0.11
1330170 | M.0.13
1824962 | M.0.35

# IfcWall: Mur de base:BS_22_WA_BBTlourd190 (10)
Type - Material: BS_22_Maçonnerie intérieure - Type4 - en béton
Classification: 22. MURS INTERIEURS (https://www.csiresources.org/standards/uniformat)
Pset_XX_AsBuilt - Catégorie: Murs; Classification BBsfB: 22.; Numéro d'article du CCTB: 20.24.01; Fournisseur/Installateur: De Graeve; Famille: Mur de base; Type: BS_22_WA_BBTlourd190; Durée de garantie (mois): 0; Périodicité de contrôle (mois): 0
Pset_XX_Cloisons - Résistance au feu: RF60
Name (Mur de base:BS_22_WA_BBTlourd190:...) | In | Identifiant | Structure/porteur
1328839 | ETAGE 00 (0) | M.0.02 | Porteur
1328960 | ETAGE 00 (0) | M.0.04 | Non porteur
1329112 | ETAGE 00 (0) | M.0.05 | Non porteur
1329226 | ETAGE 00 (0) | M.0.06 | Non porteur
1329399 | ETAGE 00 (0) | M.0.07 | Non porteur
1329521 | ETAGE 00 (0) | M.0.09 | Non porteur
1329571 | ETAGE 00 (0) | M.0.10 | Non porteur
1330093 | ETAGE 00 (0) | M.0.12 | Non porteur
2983586 | ETAGE 00 (0) |  | Non porteur
1827973 | ETAGE 10 (1) | M.0.36 | Non porteur

# IfcWall: Mur de base:BS_22_WA_C1, Mur de base:BS_22_WA_C1:1649434
In: ETAGE 00 (0)
Classification: 22. MURS INTERIEURS (https://www.csiresources.org/standards/uniformat)
Pset_XX_AsBuilt - Catégorie: Murs; Classification BBsfB: 22.; Numéro d'article du CCTB: 51.11.01; Fabricant: Gyproc Saint-Gobain; Fournisseur/Installateur: CF Consulting; Famille: Mur de base; Type: BS_22_WA_C1; Identifiant: M.0.31; Durée de garantie (mois): 0; Périodicité de contrôle (mois): 0
Pset_XX_Cloisons - Résistance au feu: RF60; Structure/porteur: Non porteur

# IfcWall: Mur de base:BS_22_WA_C1 136 (20)
Type - Material: BS_42_Revêtement mural en plaques - type A (gyproc) 12.5 mm, BS_42_Panneau OSB 18 mm, BS_42_ContreCloison-Laine minérale 75 mm, BS_42_Panneau OSB 18 mm, BS_42_Revêtement mural en plaques - type A (gyproc) 12.5 mm
Classification: 22. MURS INTERIEURS (https://www.csiresources.org/standards/uniformat)
Pset_XX_AsBuilt - Catégorie: Murs; Classification BBsfB: 22.; Numéro d'article du CCTB: 51.11.01; Fabricant: Gyproc Saint-Gobain; Fournisseur/Installateur: CF Consulting; Famille: Mur de base; Type: BS_22_WA_C1; Durée de garantie (mois): 0; Périodicité de contrôle (mois): 0
Pset_XX_Cloisons - Résistance au feu: RF60; Structure/porteur: Non porteur
Name (Mur de base:BS_22_WA_C1:...) | In | Identifiant
1491305 | ETAGE 00 (0) | M.0.24
1491345 | ETAGE 00 (0) | M.0.25
1649501 | ETAGE 00 (0) | M.0.32
1727969 | ETAGE 00 (0) | M.1.28
1869710 | ETAGE 00 (0) | M.1.62
1523058 | ETAGE 10 (1) | M.1.08
1523167 | ETAGE 10 (1) | M.1.09
1727963 | ETAGE 10 (1) | M.1.26
1727965 | ETAGE 10 (1) | M.1.27
1727972 | ETAGE 10 (1) | M.1.29
1727976 | ETAGE 10 (1) | M.1.30
1727978 | ETAGE 10 (1) | M.1.31
1727983 | ETAGE 10 (1) | M.1.32
1727997 | ETAGE 10 (1) | M.1.38
2963977 | ETAGE 10 (1)
2985439 | ETAGE 10 (1)
2985513 | ETAGE 10 (1)
2985872 | ETAGE 10 (1)
2985972 | ETAGE 10 (1)
3557789 | ETAGE 10 (1)

# IfcWall: Mur de base:BS_22_WA_C2, Mur de base:BS_22_WA_C2:1851446
In: ETAGE 10 (1)
Classification: 22. MURS INTERIEURS (https://www.csiresources.org/standards/uniformat)
Pset_XX_AsBuilt - Catégorie: Murs; Classification BBsfB: 22.; Numéro d'article du CCTB: 51.11.02; Fabricant: Gyproc Saint-Gobain; Fournisseur/Installateur: CF Consulting; Famille: Mur de base; Type: BS_22_WA_C2; Identifiant: M.1.46; Durée de garantie (mois): 0; Périodicité de contrôle (mois): 0
Pset_XX_Cloisons - Résistance au feu: RF60; Structure/porteur: Non porteur

# IfcWall: Mur de base:BS_22_WA_C2 136 (5)
In: ETAGE 10 (1)
Type - Material: BS_42_Revêtement mural en plaques - type WR (gyproc) 12.5 mm, BS_42_Panneau OSB 18 mm, BS_42_ContreCloison-Laine minérale 37.5 mm, BS_42_ContreCloison-Laine minérale 37.5 mm, BS_42_Panneau OSB 18 mm, BS_42_Revêtement mural en plaques - type A (gyproc) 12.5 mm
Classification: 22. MURS INTERIEURS (https://www.csiresources.org/standards/uniformat)
Pset_XX_AsBuilt - Catégorie: Murs; Classification BBsfB: 22.; Numéro d'article du CCTB: 51.11.02; Fabricant: Gyproc Saint-Gobain; Fournisseur/Installateur: CF Consulting; Famille: Mur de base; Type: BS_22_WA_C2; Durée de garantie (mois): 0; Périodicité de contrôle (mois): 0
Pset_XX_Cloisons - Résistance au feu: RF60; Structure/porteur: Non porteur
Name (Mur de base:BS_22_WA_C2:...) | Identifiant
1524021 | M.1.12
1524931 | M.1.13
1828860 | M.1.44
1852621 | M.1.52
1852881 | M.1.54

# IfcWall: Mur de base:BS_22_WA_C3 136 (5)
In: ETAGE 10 (1)
Type - Material: BS_42_Revêtement mural en plaques - type WR (gyproc) 12.5 mm, BS_42_Panneau OSB 18 mm, BS_42_ContreCloison-Laine minérale 37.5 mm, BS_42_ContreCloison-Laine minérale 37.5 mm, BS_42_Panneau OSB 18 mm, BS_42_Revêtement mural en plaques - type WR (gyproc) 12.5 mm
Classification: 22. MURS INTERIEURS (https://www.csiresources.org/standards/uniformat)
Pset_XX_AsBuilt - Catégorie: Murs; Classification BBsfB: 22.; Numéro d'article du CCTB: 51.11.03; Fabricant: Gyproc Saint-Gobain; Fournisseur/Installateur: CF Consulting; Famille: Mur de base; Type: BS_22_WA_C3; Durée de garantie (mois): 0; Périodicité de contrôle (mois): 0
Pset_XX_Cloisons - Résistance au feu: RF60; Structure/porteur: Non porteur
Name (Mur de base:BS_22_WA_C3:...) | Identifiant
1521466 | M.1.07
1727951 | M.1.22
1727960 | M.1.25
1727987 | M.1.33
1851758 | M.1.48

# IfcWall: Mur de base:BS_22_WA_C4 125 (2)
In: ETAGE 10 (1)
Type - Material: BS_42_Revêtement mural en plaques - type Rf (gyproc) 12.5 mm, BS_42_Revêtement mural en plaques - type Rf (gyproc) 12.5 mm, BS_42_ContreCloison-Laine minérale 37.5 mm, BS_42_ContreCloison-Laine minérale 37.5 mm, BS_42_Revêtement mural en plaques - type Rf (gyproc) 12.5 mm, BS_42_Revêtement mural en plaques - type Rf (gyproc) 12.5 mm
Classification: 22. MURS INTERIEURS (https://www.csiresources.org/standards/uniformat)
Pset_XX_AsBuilt - Catégorie: Murs; Classification BBsfB: 22.; Numéro d'article du CCTB: 51.11.04; Fabricant: Gyproc Saint-Gobain; Fournisseur/Installateur: CF Consulting; Famille: Mur de base; Type: BS_22_WA_C4; Durée de garantie (mois): 0; Périodicité de contrôle (mois): 0
Pset_XX_Cloisons - Structure/porteur: Non porteur
Name (Mur de base:BS_22_WA_C4:...) | Identifiant | Résistance au feu
1520181 | M.1.04 | RF60
1676507 | M.1.19 | RF120

# IfcWall: Mur de base:BS_22_WA_C5 130.5 (2)
In: ETAGE 10 (1)
Type - Material: BS_42_Revêtement mural en plaques - type Rf (gyproc) 12.5 mm, BS_42_Revêtement mural en plaques - type Rf (gyproc) 12.5 mm, BS_42_ContreCloison-Laine minérale 37.5 mm, BS_42_ContreCloison-Laine minérale 37.5 mm, BS_42_Panneau OSB 18 mm, BS_42_Revêtement mural en plaques - type WR (gyproc) 12.5 mm
Classification: 22. MURS INTERIEURS (https://www.csiresources.org/standards/uniformat)
Pset_XX_AsBuilt - Catégorie: Murs; Classification BBsfB: 22.; Numéro d'article du CCTB: 51.11.05; Fabricant: Gyproc Saint-Gobain; Fournisseur/Installateur: CF Consulting; Famille: Mur de base; Type: BS_22_WA_C5; Durée de garantie (mois): 0; Périodicité de contrôle (mois): 0
Pset_XX_Cloisons - Structure/porteur: Non porteur
Name (Mur de base:BS_22_WA_C5:...) | Identifiant | Résistance au feu
1520704 | M.1.05 | RF120
1727957 | M.1.24 | RF60

# IfcWall: Mur de base:BS_22_WA_C6 130.5 (7)
In: ETAGE 10 (1)
Type - Material: BS_42_Revêtement mural en plaques - type Rf (gyproc) 12.5 mm, BS_42_Revêtement mural en plaques - type Rf (gyproc) 12.5 mm, BS_42_ContreCloison-Laine minérale 37.5 mm, BS_42_ContreCloison-Laine minérale 37.5 mm, BS_42_Panneau OSB 18 mm, BS_42_Revêtement mural en plaques - type A (gyproc) 12.5 mm
Classification: 22. MURS INTERIEURS (https://www.csiresources.org/standards/uniformat)
Pset_XX_AsBuilt - Catégorie: Murs; Classification BBsfB: 22.; Numéro d'article du CCTB: 51.11.06; Fabricant: Gyproc Saint-Gobain; Fournisseur/Installateur: CF Consulting; Famille: Mur de base; Type: BS_22_WA_C6
Pset_XX_Cloisons - Structure/porteur: Non porteur
Name (Mur de base:BS_22_WA_C6:...) | Identifiant | Durée de garantie (mois) = Périodicité de contrôle (mois) | Résistance au feu
1519206 | M.1.03 | 0 | RF60
1523943 | M.1.11 | 0 | RF60
1677083 | M.1.20 | 0 | RF60
1727999 | M.1.39 | 0 | RF60
1850406 | M.1.45 | 0 | RF60
3358612 |  | 0 | RF60
3783348 |  |  | RF120

# IfcWall: Mur de base:BS_22_WA_CC1 25 (3)
Type - Material: BS_42_Revêtement mural en plaques - type A (gyproc) 12.5 mm, BS_42_Revêtement mural en plaques - type A (gyproc) 12.5 mm
Classification: 22. MURS INTERIEURS (https://www.csiresources.org/standards/uniformat)
Pset_XX_AsBuilt - Catégorie: Murs; Classification BBsfB: 22.; Numéro d'article du CCTB: 51.20.01; Fabricant: Gyproc Saint-Gobain; Fournisseur/Installateur: CF Consulting; Famille: Mur de base; Type: BS_22_WA_CC1; Durée de garantie (mois): 0; Périodicité de contrôle (mois): 0
Pset_XX_Cloisons - Résistance au feu: RF60; Structure/porteur: Non porteur
Name (Mur de base:BS_22_WA_CC1:...) | In
3087543 | ETAGE 00 (0)
3087652 | ETAGE 00 (0)
2990437 | ETAGE 10 (1)

# IfcWall: Mur de base:BS_22_WA_CC2 (3)
Classification: 22. MURS INTERIEURS (https://www.csiresources.org/standards/uniformat)
Pset_XX_AsBuilt - Catégorie: Murs; Classification BBsfB: 22.; Numéro d'article du CCTB: 51.20.02; Fabricant: Gyproc Saint-Gobain; Fournisseur/Installateur: CF Consulting; Famille: Mur de base; Type: BS_22_WA_CC2; Durée de garantie (mois): 0; Périodicité de contrôle (mois): 0
Pset_XX_Cloisons - Résistance au feu: RF60; Structure/porteur: Non porteur
Name (Mur de base:BS_22_WA_CC2:...) | In
2198389 | ETAGE 00 (0)
2977243 | ETAGE 00 (0)
3023814 | ETAGE 10 (1)

# IfcWall: Mur de base:BS_22_WA_CC2 80.5 (19)
Type - Material: BS_42_ContreCloison-Laine minérale 25 mm, BS_42_ContreCloison-Laine minérale 25 mm, BS_42_Panneau OSB 18 mm, BS_42_Revêtement mural en plaques - type A (gyproc) 12.5 mm
Classification: 22. MURS INTERIEURS (https://www.csiresources.org/standards/uniformat)
Pset_XX_AsBuilt - Catégorie: Murs; Classification BBsfB: 22.; Numéro d'article du CCTB: 51.20.02; Fabricant: Gyproc Saint-Gobain; Fournisseur/Installateur: CF Consulting; Famille: Mur de base; Type: BS_22_WA_CC2; Durée de garantie (mois): 0; Périodicité de contrôle (mois): 0
Pset_XX_Cloisons - Résistance au feu: RF60; Structure/porteur: Non porteur
Name (Mur de base:BS_22_WA_CC2:...) | In
1826111 | ETAGE 00 (0) | Pset_XX_AsBuilt - Identifiant: M.1.41
1828156 | ETAGE 00 (0) | Pset_XX_AsBuilt - Identifiant: M.1.42
1828316 | ETAGE 00 (0) | Pset_XX_AsBuilt - Identifiant: M.1.43
1865386 | ETAGE 00 (0) | Pset_XX_AsBuilt - Identifiant: M.1.61
2198590 | ETAGE 00 (0)
2199022 | ETAGE 00 (0)
2971117 | ETAGE 00 (0)
2989096 | ETAGE 00 (0)
1727991 | ETAGE 10 (1) | Pset_XX_AsBuilt - Identifiant: M.1.35
1862378 | ETAGE 10 (1) | Pset_XX_AsBuilt - Identifiant: M.1.59
1868441 | ETAGE 10 (1) | Pset_XX_AsBuilt - Identifiant: M.2.01
1871953 | ETAGE 10 (1) | Pset_XX_AsBuilt - Identifiant: M.2.02
2960778 | ETAGE 10 (1)
2961029 | ETAGE 10 (1)
2961224 | ETAGE 10 (1)
2961225 | ETAGE 10 (1)
2962858 | ETAGE 10 (1)
2962955 | ETAGE 10 (1)
3634100 | ETAGE 10 (1)

# IfcWall: Mur de base:BS_22_WA_CC3 105.5 (16)
Type - Material: BS_42_ContreCloison-Laine minérale 37.5 mm, BS_42_ContreCloison-Laine minérale 37.5 mm, BS_42_Panneau OSB 18 mm, BS_42_Revêtement mural en plaques - type A (gyproc) 12.5 mm
Classification: 22. MURS INTERIEURS (https://www.csiresources.org/standards/uniformat)
Pset_XX_AsBuilt - Catégorie: Murs; Classification BBsfB: 22.; Numéro d'article du CCTB: 51.20.03; Fabricant: Gyproc Saint-Gobain; Fournisseur/Installateur: CF Consulting; Famille: Mur de base; Type: BS_22_WA_CC3; Durée de garantie (mois): 0; Périodicité de contrôle (mois): 0
Pset_XX_Cloisons - Résistance au feu: RF60; Structure/porteur: Non porteur
Name (Mur de base:BS_22_WA_CC3:...) | In
1520927 | ETAGE 00 (0) | Pset_XX_AsBuilt - Identifiant: M.1.06
1527240 | ETAGE 00 (0) | Pset_XX_AsBuilt - Identifiant: M.1.15
2201120 | ETAGE 00 (0)
2201359 | ETAGE 00 (0)
2201636 | ETAGE 00 (0)
2201773 | ETAGE 00 (0)
3090243 | ETAGE 00 (0)
3090300 | ETAGE 00 (0)
1673179 | ETAGE 10 (1) | Pset_XX_AsBuilt - Identifiant: M.1.17
1727953 | ETAGE 10 (1) | Pset_XX_AsBuilt - Identifiant: M.1.23
1852243 | ETAGE 10 (1) | Pset_XX_AsBuilt - Identifiant: M.1.51
1853842 | ETAGE 10 (1) | Pset_XX_AsBuilt - Identifiant: M.1.55
1854392 | ETAGE 10 (1) | Pset_XX_AsBuilt - Identifiant: M.1.57
1854441 | ETAGE 10 (1) | Pset_XX_AsBuilt - Identifiant: M.1.58
3088467 | ETAGE 10 (1)
3088536 | ETAGE 10 (1)

# IfcWall: Mur de base:BS_22_WA_CC4, Mur de base:BS_22_WA_CC4:1497228
In: ETAGE 00 (0)
Classification: 22. MURS INTERIEURS (https://www.csiresources.org/standards/uniformat)
Pset_XX_AsBuilt - Catégorie: Murs; Classification BBsfB: 22.; Numéro d'article du CCTB: 51.20.04; Fabricant: Gyproc Saint-Gobain; Fournisseur/Installateur: CF Consulting; Famille: Mur de base; Type: BS_22_WA_CC4; Identifiant: M.0.26; Durée de garantie (mois): 0; Périodicité de contrôle (mois): 0
Pset_XX_Cloisons - Résistance au feu: RF60; Structure/porteur: Non porteur

# IfcWall: Mur de base:BS_22_WA_CC4 155.5, Mur de base:BS_22_WA_CC4:1498531
In: ETAGE 00 (0)
Type - Material: BS_42_ContreCloison-Laine minérale 62.5 mm, BS_42_ContreCloison-Laine minérale 62.5 mm, BS_42_Panneau OSB 18 mm, BS_42_Revêtement mural en plaques - type A (gyproc) 12.5 mm
Classification: 22. MURS INTERIEURS (https://www.csiresources.org/standards/uniformat)
Pset_XX_AsBuilt - Catégorie: Murs; Classification BBsfB: 22.; Numéro d'article du CCTB: 51.20.04; Fabricant: Gyproc Saint-Gobain; Fournisseur/Installateur: CF Consulting; Famille: Mur de base; Type: BS_22_WA_CC4; Identifiant: M.0.28; Durée de garantie (mois): 0; Périodicité de contrôle (mois): 0
Pset_XX_Cloisons - Résistance au feu: RF60; Structure/porteur: Non porteur

# IfcWall: Mur de base:BS_22_WA_CC5 93 (2)
Type - Material: BS_42_ContreCloison-Laine minérale 25 mm, BS_42_ContreCloison-Laine minérale 25 mm, BS_42_Panneau OSB 18 mm, BS_42_Revêtement mural en plaques - type Rf (gyproc) 12.5 mm, BS_42_Revêtement mural en plaques - type Rf (gyproc) 12.5 mm
Classification: 22. MURS INTERIEURS (https://www.csiresources.org/standards/uniformat)
Pset_XX_AsBuilt - Catégorie: Murs; Classification BBsfB: 22.; Numéro d'article du CCTB: 51.20.05; Fabricant: Gyproc Saint-Gobain; Fournisseur/Installateur: CF Consulting; Famille: Mur de base; Type: BS_22_WA_CC5; Durée de garantie (mois): 0; Périodicité de contrôle (mois): 0
Pset_XX_Cloisons - Résistance au feu: RF60; Structure/porteur: Non porteur
Name (Mur de base:BS_22_WA_CC5:...) | In | Identifiant
1525179 | ETAGE 00 (0) | M.1.14
1872049 | ETAGE 10 (1) | M.1.63

# IfcWall: Mur de base:BS_22_WA_CC6 118, Mur de base:BS_22_WA_CC6:1854058
In: ETAGE 10 (1)
Type - Material: BS_42_ContreCloison-Laine minérale 37.5 mm, BS_42_ContreCloison-Laine minérale 37.5 mm, BS_42_Panneau OSB 18 mm, BS_42_Revêtement mural en plaques - type Rf (gyproc) 12.5 mm, BS_42_Revêtement mural en plaques - type Rf (gyproc) 12.5 mm
Classification: 22. MURS INTERIEURS (https://www.csiresources.org/standards/uniformat)
Pset_XX_AsBuilt - Catégorie: Murs; Classification BBsfB: 22.; Numéro d'article du CCTB: 51.20.06; Fabricant: Gyproc Saint-Gobain; Fournisseur/Installateur: CF Consulting; Famille: Mur de base; Type: BS_22_WA_CC6; Identifiant: M.1.56; Durée de garantie (mois): 0; Périodicité de contrôle (mois): 0
Pset_XX_Cloisons - Résistance au feu: RF60; Structure/porteur: Non porteur

# IfcWall: Mur de base:BS_22_WA_CC7 80.5 (5)
Type - Material: BS_42_ContreCloison-Laine minérale 50 mm, BS_42_Panneau OSB 18 mm, BS_42_Revêtement mural en plaques - type WR (gyproc) 12.5 mm
Classification: 22. MURS INTERIEURS (https://www.csiresources.org/standards/uniformat)
Pset_XX_AsBuilt - Catégorie: Murs; Classification BBsfB: 22.; Numéro d'article du CCTB: 51.20.07; Fabricant: Gyproc Saint-Gobain; Fournisseur/Installateur: CF Consulting; Famille: Mur de base; Type: BS_22_WA_CC7
Pset_XX_Cloisons - Résistance au feu: RF60; Structure/porteur: Non porteur
Name (Mur de base:BS_22_WA_CC7:...) | In | Identifiant | Durée de garantie (mois) = Périodicité de contrôle (mois)
1852154 | ETAGE 00 (0) | M.1.50 | 0
3781519 | ETAGE 00 (0)
3781521 | ETAGE 00 (0)
1851987 | ETAGE 10 (1) | M.1.49 | 0
1852802 | ETAGE 10 (1) | M.1.53 | 0

# IfcWall: Mur de base:BS_22_WA_CC8 105.5, Mur de base:BS_22_WA_CC8:1673280
In: ETAGE 10 (1)
Type - Material: BS_42_ContreCloison-Laine minérale 37.5 mm, BS_42_ContreCloison-Laine minérale 37.5 mm, BS_42_Panneau OSB 18 mm, BS_42_Revêtement mural en plaques - type WR (gyproc) 12.5 mm
Classification: 22. MURS INTERIEURS (https://www.csiresources.org/standards/uniformat)
Pset_XX_AsBuilt - Catégorie: Murs; Classification BBsfB: 22.; Numéro d'article du CCTB: 51.20.08; Fabricant: Gyproc Saint-Gobain; Fournisseur/Installateur: CF Consulting; Famille: Mur de base; Type: BS_22_WA_CC8; Identifiant: M.1.18; Durée de garantie (mois): 0; Périodicité de contrôle (mois): 0
Pset_XX_Cloisons - Résistance au feu: RF60; Structure/porteur: Non porteur

# IfcWall: Mur de base:BS_22_WA_CC9 75 (2)
In: ETAGE 10 (1)
Type - Material: BS_42_ContreCloison-Laine minérale 22.5 mm, BS_42_ContreCloison-Laine minérale 22.5 mm, BS_42_Panneau OSB 18 mm, BS_42_Revêtement mural en plaque fibrociment 12 mm
Classification: 22. MURS INTERIEURS (https://www.csiresources.org/standards/uniformat)
Pset_XX_AsBuilt - Catégorie: Murs; Classification BBsfB: 22.; Numéro d'article du CCTB: 51.20.09; Fabricant: Gyproc Saint-Gobain; Fournisseur/Installateur: CF Consulting; Famille: Mur de base; Type: BS_22_WA_CC9; Durée de garantie (mois): 0; Périodicité de contrôle (mois): 0
Pset_XX_Cloisons - Résistance au feu: RF60; Structure/porteur: Non porteur
Name (Mur de base:BS_22_WA_CC9:...) | Identifiant
1946391 | M..64
1946578 | M..65

# IfcWall: Mur de base:BS_22_WA_ContreCloison acoustique 140.5 (30)
In: ETAGE 00 (0)
Type - Material: BS_00_Vide d'air 10 mm, BS_42_ContreCloison-Laine minérale 100 mm, BS_42_Panneau OSB 18 mm, BS_42_Revêtement mural en plaques - type A (gyproc) 12.5 mm
Classification: 22. MURS INTERIEURS (https://www.csiresources.org/standards/uniformat)
Pset_XX_AsBuilt - Catégorie: Murs; Classification BBsfB: 22.; Numéro d'article du CCTB: 51.20.; Fabricant: Gyproc Saint-Gobain; Fournisseur/Installateur: CF Consulting; Famille: Mur de base; Type: BS_22_WA_ContreCloison acoustique; Durée de garantie (mois): 0; Périodicité de contrôle (mois): 0
Pset_XX_Cloisons - Résistance au feu: RF60; Structure/porteur: Non porteur
Name (Mur de base:BS_22_WA_ContreCloison acoustique:...)
2945829
2946150
2946249
2946440
2947371
2947957
2948092
2948097
2948105
2948109
2948115
2948496
2949282
2949589
2949841
2949883
2950167
2950318
2950380
2950392
2950400
2950404
2954345
2954360
2956236
2956308
2956516
3077600
3078268
3078540

# IfcWall: Mur de base:BS_28_WA_BTcoulé250, Mur de base:BS_28_WA_BTcoulé250:1583358
In: FOND 00 (0)
Classification: 28. OSSATURE (https://www.csiresources.org/standards/uniformat)
Pset_XX_AsBuilt - Catégorie: Murs; Classification BBsfB: 28.; Numéro d'article du CCTB: 22.16.1a; Fournisseur/Installateur: De Graeve; Famille: Mur de base; Type: BS_28_WA_BTcoulé250; Identifiant: V.0.03; Durée de garantie (mois): 0; Périodicité de contrôle (mois): 0

# IfcWall: Mur de base:BS_28_WA_BTcoulé250 (16)
Type - Material: BS_28_Ossature en béton armé - Eléments coulé sur place
Classification: 28. OSSATURE (https://www.csiresources.org/standards/uniformat)
Pset_XX_AsBuilt - Catégorie: Murs; Classification BBsfB: 28.; Numéro d'article du CCTB: 22.16.1a; Fournisseur/Installateur: De Graeve; Famille: Mur de base; Type: BS_28_WA_BTcoulé250; Durée de garantie (mois): 0; Périodicité de contrôle (mois): 0
Name (Mur de base:BS_28_WA_BTcoulé250:...) | In
1583429 | FOND 00 (0) | Pset_XX_AsBuilt - Identifiant: V.0.04
1583488 | FOND 00 (0) | Pset_XX_AsBuilt - Identifiant: V.0.05
1583531 | FOND 00 (0) | Pset_XX_AsBuilt - Identifiant: V.0.06
1625670 | FOND 00 (0) | Pset_XX_AsBuilt - Identifiant: V.0.07
1973130 | FOND 00 (0)
1973465 | FOND 00 (0)
1975354 | FOND 00 (0)
1975468 | FOND 00 (0)
1975668 | FOND 00 (0)
1975842 | FOND 00 (0)
1976202 | FOND 00 (0)
1345022 | ETAGE 00 (0) | Pset_XX_AsBuilt - Identifiant: V.0.01
1498175 | ETAGE 00 (0) | Pset_XX_AsBuilt - Identifiant: V.0.02
1656408 | ETAGE 00 (0) | Pset_XX_AsBuilt - Identifiant: V.0.08
1969635 | ETAGE 00 (0)
1976839 | ETAGE 00 (0)

# IfcWall: Mur de base:BS_41_WA_TOLE MET10 (2)
In: ETAGE 10 (1)
Type - Material: BS_41_Bardage en tôle perforé
Classification: 21. MURS EXTERIEURS (https://www.csiresources.org/standards/uniformat)
Pset_XX_AsBuilt - Catégorie: Murs; Classification BBsfB: 21.; Famille: Mur de base; Type: BS_41_WA_TOLE MET10; Durée de garantie (mois): 0; Périodicité de contrôle (mois): 0
Name (Mur de base:BS_41_WA_TOLE MET10:...)
2012030
2012264

# IfcWall: Mur de base:BS_42_WA_Cloison bois_80, Mur de base:BS_42_WA_Cloison bois_80:1687628
In: ETAGE 00 (0)
Type - Material: BS_22_Cloison légère fixe (bois)
Classification: 42. REVETEMENTS MURAUX (https://www.csiresources.org/standards/uniformat)
Pset_XX_AsBuilt - Catégorie: Murs; Classification BBsfB: 42.; Numéro d'article du CCTB: -; Famille: Mur de base; Type: BS_42_WA_Cloison bois_80; Identifiant: M.1.21; Durée de garantie (mois): 0; Périodicité de contrôle (mois): 0

# IfcWall: Mur de base_BS_22_WA_BBTlourd190, Mur de base:BS_22_WA_BBTlourd190:1301141
In: ETAGE 00 (0)
Classification: 22. MURS INTERIEURS (https://www.csiresources.org/standards/uniformat); Material: BS_22_Maçonnerie intérieure - Type4 - en béton
Pset_XX_AsBuilt - Catégorie: Murs; Classification BBsfB: 22.; Numéro d'article du CCTB: 20.24.01; Fournisseur/Installateur: De Graeve; Famille: Mur de base; Type: BS_22_WA_BBTlourd190; Identifiant: M.0.01; Durée de garantie (mois): 0; Périodicité de contrôle (mois): 0
Pset_XX_Cloisons - Résistance au feu: RF60; Structure/porteur: Non porteur

# IfcWall: Mur de base_BS_22_WA_BBTlourd190_1, Mur de base:BS_22_WA_BBTlourd190:1328891
In: ETAGE 00 (0)
Classification: 22. MURS INTERIEURS (https://www.csiresources.org/standards/uniformat); Material: BS_22_Maçonnerie intérieure - Type4 - en béton
Pset_XX_AsBuilt - Catégorie: Murs; Classification BBsfB: 22.; Numéro d'article du CCTB: 20.24.01; Fournisseur/Installateur: De Graeve; Famille: Mur de base; Type: BS_22_WA_BBTlourd190; Identifiant: M.0.03; Durée de garantie (mois): 0; Périodicité de contrôle (mois): 0
Pset_XX_Cloisons - Résistance au feu: RF60; Structure/porteur: Non porteur
